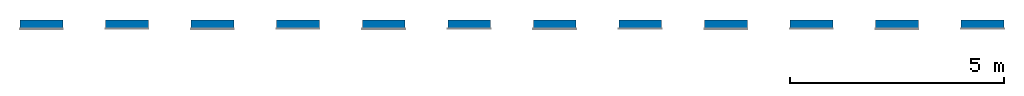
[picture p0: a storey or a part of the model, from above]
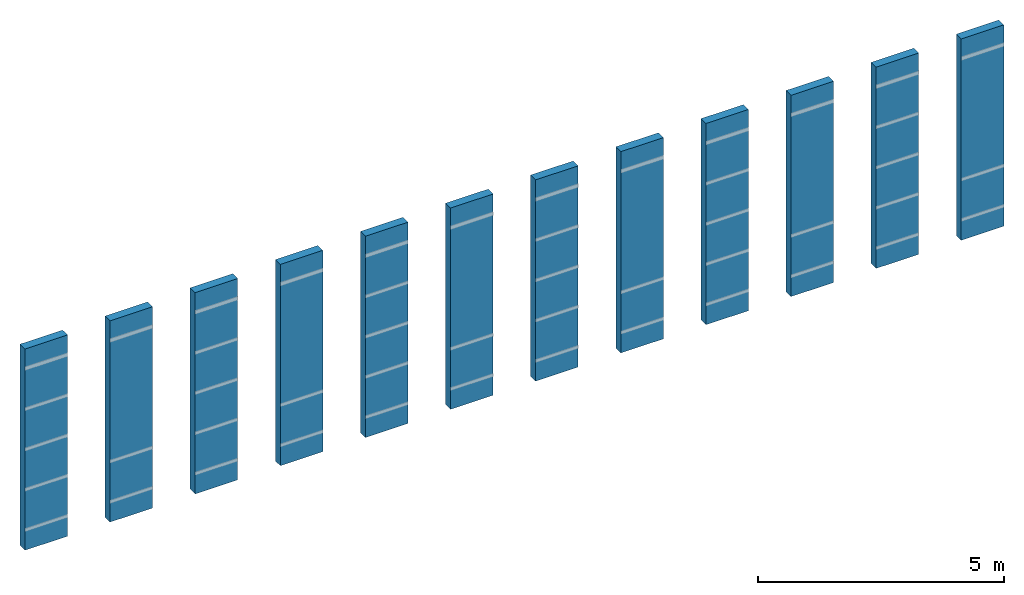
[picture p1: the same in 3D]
Properties of the parts of a building model (IFC2X3), part 1 of 3

# File
Description: ViewDefinition [CoordinationView_V2.0]
Time: 2025-06-20T15:58:29
Written by: The EXPRESS Data Manager Version 5.02.0100.07 : 28 Aug 2013
Made in: 21.1.90.15 - Exporter 21.1.90.15 - Alternate UI 21.1.90.15
Comment: STEP Physical File produced by: The EXPRESS Data Manager Version 5.02.0100.07 : 28 Aug 2013 * Module: EDMstepFileFactory/EDMstandAlone * Creation date: Fri Jun 20 15:58:29 2025 * Host: STB002 * Database: C:\Users\LARISS~1\AppData\Local\Temp\234e31d9-e186-458c-9206-d387dea7a233\60039892-82e4-4471-811b-854914402df2\ifc * Database version: 5507 * Database creation date: Fri Jun 20 15:58:27 2025 * Schema: IFC2X3 * Model: DataRepository.ifc * Model creation date: Fri Jun 20 15:58:28 2025 * Header model: DataRepository.ifc_HeaderModel * Header model creation date: Fri Jun 20 15:58:28 2025 * EDMuser: sdai-user * EDMgroup: sdai-group * License ID and type: 5605 : Permanent license. Expiry date: * EDMstepFileFactory options: 020000

# IfcSite, Default
RefLatitude: 42, 24, 53, 508911; RefLongitude: -71, -15, -29, -58837; RefElevation: 0 mm
Pset_ProductRequirements - Category: Project Information

# IfcBuilding
Pset_BuildingCommon - NumberOfStoreys: 1
Pset_ProductRequirements - Category: Project Information

# IfcBuildingStorey: Level:Level 1, Level 1
LongName: Level 1; Elevation: 0 mm
Pset_AirSideSystemInformation - Name: Level 1
Pset_ProductRequirements - Name: Level 1; Category: Levels

# IfcBuildingElementProxy: Wall Sweep:REVIGRÉS-URBAN-RB-8X120-RECT-ANTRACITE, Wall Sweep:REVIGRÉS-URBAN-RB-8X120-RECT-ANTRACITE:182745
In: Level 1
Type - Pset_ManufacturerTypeInformation - Manufacturer: REVIGRÉS
Type - Pset_ProductRequirements - Category: Wall Sweeps
Type - IFC.REVIGRÉS-Dados do fabricante-Wall Sweeps - FabricanteURL: https://www.revigres.pt/; ReferenciaModelo: Urban; Acabamento: RECT; IdentificadorDoOperadorEconomico: 501840856; UrlFabricanteArtigo: https://www.revigres.pt/colecoes/urban; PaisOrigem: Portugal
Type - IFC.REVIGRÉS-Dados de desempenho-Wall Sweeps - Rectilinearidade: ± 0.2% máx.± 0.8 mm; Ortogonalidade: ± 0.2% máx.± 1.5 mm; PlanaridadeDaSuperficie: ± 0.3% máx. ± 1.8 mm; AbsorcaoDeAgua: < 0.05%; ModuloDeRuptura: > 45 N/mm²; ResistenciaAFlexao: > 1500 N; ResistenciaAAbrasaoProfunda: < 120 mm³; DilatacaoTermicaLinear: ≤ 8,0x10-6 °C-1; ResistenciaAoChoqueTermico: Resiste; DurabilidadeResistenciaAoGeloDegelo: Resiste; ResistenciaAoEscorregamentoDIN51130: R9; ResistenciaAoEscorregamentoDIN51097: A; ResistenciaAoEscorregamentoENV51097: A; ResistenciaAoDeslizamentoENV12633: Class 1; ResistenciaAoEscorregamentoANSIA1371: ≥0,42; ResistenciaAoEscorregamentoENV12633: Class 1; ResistenciaAsManchas: Class 5; ResistenciaABaixasConcentracoesDeAcidosEAlcalis: Classe LA; ResistenciaAAltasConcentracoesDeAcidosEAlcalis: Classe HA; LibertacaoDeCadmio: 0; LibertacaoDeChumbo: 0
Type - IFC.REVIGRÉS-Dados de especificação-Wall Sweeps - VariacaoTonalidade: 2; NivelDeTrafego: 0; EPavimento: Não; ERevestimento: Sim; EExterno: Sim
Type - IFC.REVIGRÉS-Dados geométricos-Wall Sweeps - AlturaNominal: 9.8 mm; ComprimentoNominal: 8 mm; LarguraNominal: 1186 mm
Type - IFC.REVIGRÉS-Dados de sustentabilidade-Wall Sweeps - PotencialPrivacaoDeAguaConsumoDeAguaPonderado: 4.5; EnergiaTermicaExportada: 0; ItemENovo: Sim; ItemEParcialmenteReciclado: 0.29; ItemEReciclado: Sim; VidaÚtilEsperada: 50; SubstanciasPerigosas: Não; PotencialDeEsgotamentoAbioticoDosRecursosFosseis: 203; PotencialDeEsgotamentoAbioticoDosRecursosNaoFosseisMineraisEMetais: 0.000701; PotencialDeAquecimentoGlobalBiogenico: -0.48; CombustiveisFosseisComPotencialDeAquecimentoGlobal: 13.9; PotencialDeAquecimentoGlobalUsoDoSoloEMudancaDeUsoDoSolo: 0.0246; PotencialDeEutrofizacaoFraccaoDeNutrientesQueAtingemOCompartimentoFinalDeAguaDoce: 0.000189; PotencialDeEutrofizacaoFraccaoDeNutrientesQueAtingemOCompartimentoFinalMarinho: 0.0122; EnergiaRecuperada: 0.00739; ConsumoDeAguaDoce: 0.113; UtilizacaoLiquidaDeAguaDoce: 0.113; ResiduosPerigososEliminados: 0.00221; ResiduosNaoPerigososEliminados: 1.83; MassaTotalDeResiduosRadioactivosEliminados: 0.000394; EnergiaElectricaExportada: 1.55; MateriaisParaRecuperacaoDeEnergia: 0.00739; MateriaisParaReciclagem: 0.0253; UnidadeEPD: 1 m²
Type - IFC.REVIGRÉS-Dados gerais-Wall Sweeps - Nome: REVIGRÉS-URBAN-RB-8X120-RECT-URBAN ANTRACITE; TipoProduto: Prensado a seco: grupo BIa UGL | Grés porcelânico técnico; NumeroDeRegistoDAP: EPD-REV-20240006-CCC1-EN; ReferenciaDAP: -; UrlDOP: -
Pset_ProvisionForVoid - Shape: Undefined; Width: 1000 mm; Depth: 1000 mm
IFC.REVIGRÉS-Dados do fabricante-Wall Sweeps - Type: Wall Sweep: REVIGRÉS-URBAN-RB-8X120-RECT-ANTRACITE
IFC.REVIGRÉS-Dados de desempenho-Wall Sweeps - Type: Wall Sweep: REVIGRÉS-URBAN-RB-8X120-RECT-ANTRACITE
IFC.REVIGRÉS-Dados de especificação-Wall Sweeps - Type: Wall Sweep: REVIGRÉS-URBAN-RB-8X120-RECT-ANTRACITE
IFC.REVIGRÉS-Dados geométricos-Wall Sweeps - Type: Wall Sweep: REVIGRÉS-URBAN-RB-8X120-RECT-ANTRACITE
IFC.REVIGRÉS-Dados de sustentabilidade-Wall Sweeps - Type: Wall Sweep: REVIGRÉS-URBAN-RB-8X120-RECT-ANTRACITE

# IfcBuildingElementProxy: Wall Sweep:REVIGRÉS-URBAN-RB-8X120-RECT-BONE, Wall Sweep:REVIGRÉS-URBAN-RB-8X120-RECT-BONE:182755
In: Level 1
Type - Pset_ManufacturerTypeInformation - Manufacturer: REVIGRÉS
Type - Pset_ProductRequirements - Category: Wall Sweeps
Type - IFC.REVIGRÉS-Dados do fabricante-Wall Sweeps - FabricanteURL: https://www.revigres.pt/; ReferenciaModelo: Urban; Acabamento: RECT; IdentificadorDoOperadorEconomico: 501840856; UrlFabricanteArtigo: https://www.revigres.pt/colecoes/urban; PaisOrigem: Portugal
Type - IFC.REVIGRÉS-Dados de desempenho-Wall Sweeps - Rectilinearidade: ± 0.2% máx.± 0.8 mm; Ortogonalidade: ± 0.2% máx.± 1.5 mm; PlanaridadeDaSuperficie: ± 0.3% máx. ± 1.8 mm; AbsorcaoDeAgua: < 0.05%; ModuloDeRuptura: > 45 N/mm²; ResistenciaAFlexao: > 1500 N; ResistenciaAAbrasaoProfunda: < 120 mm³; DilatacaoTermicaLinear: ≤ 8,0x10-6 °C-1; ResistenciaAoChoqueTermico: Resiste; DurabilidadeResistenciaAoGeloDegelo: Resiste; ResistenciaAoEscorregamentoDIN51130: R9; ResistenciaAoEscorregamentoDIN51097: A; ResistenciaAoEscorregamentoENV51097: A; ResistenciaAoDeslizamentoENV12633: Class 1; ResistenciaAoEscorregamentoANSIA1371: ≥0,42; ResistenciaAoEscorregamentoENV12633: Class 1; ResistenciaAsManchas: Class 5; ResistenciaABaixasConcentracoesDeAcidosEAlcalis: Classe LA; ResistenciaAAltasConcentracoesDeAcidosEAlcalis: Classe HA; LibertacaoDeCadmio: 0; LibertacaoDeChumbo: 0
Type - IFC.REVIGRÉS-Dados de especificação-Wall Sweeps - VariacaoTonalidade: 2; NivelDeTrafego: 0; EPavimento: Não; ERevestimento: Sim; EExterno: Sim
Type - IFC.REVIGRÉS-Dados geométricos-Wall Sweeps - AlturaNominal: 9.8 mm; ComprimentoNominal: 8 mm; LarguraNominal: 1186 mm
Type - IFC.REVIGRÉS-Dados de sustentabilidade-Wall Sweeps - PotencialPrivacaoDeAguaConsumoDeAguaPonderado: 4.5; EnergiaTermicaExportada: 0; ItemENovo: Sim; ItemEParcialmenteReciclado: 0.03; ItemEReciclado: Sim; VidaÚtilEsperada: 50; SubstanciasPerigosas: Não; PotencialDeEsgotamentoAbioticoDosRecursosFosseis: 203; PotencialDeEsgotamentoAbioticoDosRecursosNaoFosseisMineraisEMetais: 0.000701; PotencialDeAquecimentoGlobalBiogenico: -0.48; CombustiveisFosseisComPotencialDeAquecimentoGlobal: 13.9; PotencialDeAquecimentoGlobalUsoDoSoloEMudancaDeUsoDoSolo: 0.0246; PotencialDeEutrofizacaoFraccaoDeNutrientesQueAtingemOCompartimentoFinalDeAguaDoce: 0.000189; PotencialDeEutrofizacaoFraccaoDeNutrientesQueAtingemOCompartimentoFinalMarinho: 0.0122; EnergiaRecuperada: 0.00739; ConsumoDeAguaDoce: 0.113; UtilizacaoLiquidaDeAguaDoce: 0.113; ResiduosPerigososEliminados: 0.00221; ResiduosNaoPerigososEliminados: 1.83; MassaTotalDeResiduosRadioactivosEliminados: 0.000394; EnergiaElectricaExportada: 1.55; MateriaisParaRecuperacaoDeEnergia: 0.00739; MateriaisParaReciclagem: 0.0253; UnidadeEPD: 1 m²
Type - IFC.REVIGRÉS-Dados gerais-Wall Sweeps - Nome: REVIGRÉS-URBAN-RB-8X120-RECT-URBAN BONE; TipoProduto: Prensado a seco: grupo BIa UGL | Grés porcelânico técnico; NumeroDeRegistoDAP: EPD-REV-20240006-CCC1-EN; ReferenciaDAP: -; UrlDOP: -
Pset_ProvisionForVoid - Shape: Undefined; Width: 1000 mm; Depth: 1000 mm
IFC.REVIGRÉS-Dados do fabricante-Wall Sweeps - Type: Wall Sweep: REVIGRÉS-URBAN-RB-8X120-RECT-BONE
IFC.REVIGRÉS-Dados de desempenho-Wall Sweeps - Type: Wall Sweep: REVIGRÉS-URBAN-RB-8X120-RECT-BONE
IFC.REVIGRÉS-Dados de especificação-Wall Sweeps - Type: Wall Sweep: REVIGRÉS-URBAN-RB-8X120-RECT-BONE
IFC.REVIGRÉS-Dados geométricos-Wall Sweeps - Type: Wall Sweep: REVIGRÉS-URBAN-RB-8X120-RECT-BONE
IFC.REVIGRÉS-Dados de sustentabilidade-Wall Sweeps - Type: Wall Sweep: REVIGRÉS-URBAN-RB-8X120-RECT-BONE

# IfcBuildingElementProxy: Wall Sweep:REVIGRÉS-URBAN-RB-8X120-RECT-CRAFT, Wall Sweep:REVIGRÉS-URBAN-RB-8X120-RECT-CRAFT:182765
In: Level 1
Type - Pset_ManufacturerTypeInformation - Manufacturer: REVIGRÉS
Type - Pset_ProductRequirements - Category: Wall Sweeps
Type - IFC.REVIGRÉS-Dados do fabricante-Wall Sweeps - FabricanteURL: https://www.revigres.pt/; ReferenciaModelo: Urban; Acabamento: RECT; IdentificadorDoOperadorEconomico: 501840856; UrlFabricanteArtigo: https://www.revigres.pt/colecoes/urban; PaisOrigem: Portugal
Type - IFC.REVIGRÉS-Dados de desempenho-Wall Sweeps - Rectilinearidade: ± 0.2% máx.± 0.8 mm; Ortogonalidade: ± 0.2% máx.± 1.5 mm; PlanaridadeDaSuperficie: ± 0.3% máx. ± 1.8 mm; AbsorcaoDeAgua: < 0.05%; ModuloDeRuptura: > 45 N/mm²; ResistenciaAFlexao: > 1500 N; ResistenciaAAbrasaoProfunda: < 120 mm³; DilatacaoTermicaLinear: ≤ 8,0x10-6 °C-1; ResistenciaAoChoqueTermico: Resiste; DurabilidadeResistenciaAoGeloDegelo: Resiste; ResistenciaAoEscorregamentoDIN51130: R9; ResistenciaAoEscorregamentoDIN51097: A; ResistenciaAoEscorregamentoENV51097: A; ResistenciaAoDeslizamentoENV12633: Class 1; ResistenciaAoEscorregamentoANSIA1371: ≥0,42; ResistenciaAoEscorregamentoENV12633: Class 1; ResistenciaAsManchas: Class 5; ResistenciaABaixasConcentracoesDeAcidosEAlcalis: Classe LA; ResistenciaAAltasConcentracoesDeAcidosEAlcalis: Classe HA; LibertacaoDeCadmio: 0; LibertacaoDeChumbo: 0
Type - IFC.REVIGRÉS-Dados de especificação-Wall Sweeps - VariacaoTonalidade: 2; NivelDeTrafego: 0; EPavimento: Não; ERevestimento: Sim; EExterno: Sim
Type - IFC.REVIGRÉS-Dados geométricos-Wall Sweeps - AlturaNominal: 9.8 mm; ComprimentoNominal: 8 mm; LarguraNominal: 1186 mm
Type - IFC.REVIGRÉS-Dados de sustentabilidade-Wall Sweeps - PotencialPrivacaoDeAguaConsumoDeAguaPonderado: 4.5; EnergiaTermicaExportada: 0; ItemENovo: Sim; ItemEParcialmenteReciclado: 0.19; ItemEReciclado: Sim; VidaÚtilEsperada: 50; SubstanciasPerigosas: Não; PotencialDeEsgotamentoAbioticoDosRecursosFosseis: 203; PotencialDeEsgotamentoAbioticoDosRecursosNaoFosseisMineraisEMetais: 0.000701; PotencialDeAquecimentoGlobalBiogenico: -0.48; CombustiveisFosseisComPotencialDeAquecimentoGlobal: 13.9; PotencialDeAquecimentoGlobalUsoDoSoloEMudancaDeUsoDoSolo: 0.0246; PotencialDeEutrofizacaoFraccaoDeNutrientesQueAtingemOCompartimentoFinalDeAguaDoce: 0.000189; PotencialDeEutrofizacaoFraccaoDeNutrientesQueAtingemOCompartimentoFinalMarinho: 0.0122; EnergiaRecuperada: 0.00739; ConsumoDeAguaDoce: 0.113; UtilizacaoLiquidaDeAguaDoce: 0.113; ResiduosPerigososEliminados: 0.00221; ResiduosNaoPerigososEliminados: 1.83; MassaTotalDeResiduosRadioactivosEliminados: 0.000394; EnergiaElectricaExportada: 1.55; MateriaisParaRecuperacaoDeEnergia: 0.00739; MateriaisParaReciclagem: 0.0253; UnidadeEPD: 1 m²
Type - IFC.REVIGRÉS-Dados gerais-Wall Sweeps - Nome: REVIGRÉS-URBAN-RB-8X120-RECT-URBAN CRAFT; TipoProduto: Prensado a seco: grupo BIa UGL | Grés porcelânico técnico; NumeroDeRegistoDAP: EPD-REV-20240006-CCC1-EN; ReferenciaDAP: -; UrlDOP: -
Pset_ProvisionForVoid - Shape: Undefined; Width: 1000 mm; Depth: 1000 mm
IFC.REVIGRÉS-Dados do fabricante-Wall Sweeps - Type: Wall Sweep: REVIGRÉS-URBAN-RB-8X120-RECT-CRAFT
IFC.REVIGRÉS-Dados de desempenho-Wall Sweeps - Type: Wall Sweep: REVIGRÉS-URBAN-RB-8X120-RECT-CRAFT
IFC.REVIGRÉS-Dados de especificação-Wall Sweeps - Type: Wall Sweep: REVIGRÉS-URBAN-RB-8X120-RECT-CRAFT
IFC.REVIGRÉS-Dados geométricos-Wall Sweeps - Type: Wall Sweep: REVIGRÉS-URBAN-RB-8X120-RECT-CRAFT
IFC.REVIGRÉS-Dados de sustentabilidade-Wall Sweeps - Type: Wall Sweep: REVIGRÉS-URBAN-RB-8X120-RECT-CRAFT

# IfcBuildingElementProxy: Wall Sweep:REVIGRÉS-URBAN-RB-8X120-RECT-FOG, Wall Sweep:REVIGRÉS-URBAN-RB-8X120-RECT-FOG:182775
In: Level 1
Type - Pset_ManufacturerTypeInformation - Manufacturer: REVIGRÉS
Type - Pset_ProductRequirements - Category: Wall Sweeps
Type - IFC.REVIGRÉS-Dados do fabricante-Wall Sweeps - FabricanteURL: https://www.revigres.pt/; ReferenciaModelo: Urban; Acabamento: RECT; IdentificadorDoOperadorEconomico: 501840856; UrlFabricanteArtigo: https://www.revigres.pt/colecoes/urban; PaisOrigem: Portugal
Type - IFC.REVIGRÉS-Dados de desempenho-Wall Sweeps - Rectilinearidade: ± 0.2% máx.± 0.8 mm; Ortogonalidade: ± 0.2% máx.± 1.5 mm; PlanaridadeDaSuperficie: ± 0.3% máx. ± 1.8 mm; AbsorcaoDeAgua: < 0.05%; ModuloDeRuptura: > 45 N/mm²; ResistenciaAFlexao: > 1500 N; ResistenciaAAbrasaoProfunda: < 120 mm³; DilatacaoTermicaLinear: ≤ 8,0x10-6 °C-1; ResistenciaAoChoqueTermico: Resiste; DurabilidadeResistenciaAoGeloDegelo: Resiste; ResistenciaAoEscorregamentoDIN51130: R9; ResistenciaAoEscorregamentoDIN51097: A; ResistenciaAoEscorregamentoENV51097: A; ResistenciaAoDeslizamentoENV12633: Class 1; ResistenciaAoEscorregamentoANSIA1371: ≥0,42; ResistenciaAoEscorregamentoENV12633: Class 1; ResistenciaAsManchas: Class 5; ResistenciaABaixasConcentracoesDeAcidosEAlcalis: Classe LA; ResistenciaAAltasConcentracoesDeAcidosEAlcalis: Classe HA; LibertacaoDeCadmio: 0; LibertacaoDeChumbo: 0
Type - IFC.REVIGRÉS-Dados de especificação-Wall Sweeps - VariacaoTonalidade: 2; NivelDeTrafego: 0; EPavimento: Não; ERevestimento: Sim; EExterno: Sim
Type - IFC.REVIGRÉS-Dados geométricos-Wall Sweeps - AlturaNominal: 9.8 mm; ComprimentoNominal: 8 mm; LarguraNominal: 1186 mm
Type - IFC.REVIGRÉS-Dados de sustentabilidade-Wall Sweeps - PotencialPrivacaoDeAguaConsumoDeAguaPonderado: 4.5; EnergiaTermicaExportada: 0; ItemENovo: Sim; ItemEParcialmenteReciclado: 0.23; ItemEReciclado: Sim; VidaÚtilEsperada: 50; SubstanciasPerigosas: Não; PotencialDeEsgotamentoAbioticoDosRecursosFosseis: 203; PotencialDeEsgotamentoAbioticoDosRecursosNaoFosseisMineraisEMetais: 0.000701; PotencialDeAquecimentoGlobalBiogenico: -0.48; CombustiveisFosseisComPotencialDeAquecimentoGlobal: 13.9; PotencialDeAquecimentoGlobalUsoDoSoloEMudancaDeUsoDoSolo: 0.0246; PotencialDeEutrofizacaoFraccaoDeNutrientesQueAtingemOCompartimentoFinalDeAguaDoce: 0.000189; PotencialDeEutrofizacaoFraccaoDeNutrientesQueAtingemOCompartimentoFinalMarinho: 0.0122; EnergiaRecuperada: 0.00739; ConsumoDeAguaDoce: 0.113; UtilizacaoLiquidaDeAguaDoce: 0.113; ResiduosPerigososEliminados: 0.00221; ResiduosNaoPerigososEliminados: 1.83; MassaTotalDeResiduosRadioactivosEliminados: 0.000394; EnergiaElectricaExportada: 1.55; MateriaisParaRecuperacaoDeEnergia: 0.00739; MateriaisParaReciclagem: 0.0253; UnidadeEPD: 1 m²
Type - IFC.REVIGRÉS-Dados gerais-Wall Sweeps - Nome: REVIGRÉS-URBAN-RB-8X120-RECT-URBAN FOG; TipoProduto: Prensado a seco: grupo BIa UGL | Grés porcelânico técnico; NumeroDeRegistoDAP: EPD-REV-20240006-CCC1-EN; ReferenciaDAP: -; UrlDOP: -
Pset_ProvisionForVoid - Shape: Undefined; Width: 1000 mm; Depth: 1000 mm
IFC.REVIGRÉS-Dados do fabricante-Wall Sweeps - Type: Wall Sweep: REVIGRÉS-URBAN-RB-8X120-RECT-FOG
IFC.REVIGRÉS-Dados de desempenho-Wall Sweeps - Type: Wall Sweep: REVIGRÉS-URBAN-RB-8X120-RECT-FOG
IFC.REVIGRÉS-Dados de especificação-Wall Sweeps - Type: Wall Sweep: REVIGRÉS-URBAN-RB-8X120-RECT-FOG
IFC.REVIGRÉS-Dados geométricos-Wall Sweeps - Type: Wall Sweep: REVIGRÉS-URBAN-RB-8X120-RECT-FOG
IFC.REVIGRÉS-Dados de sustentabilidade-Wall Sweeps - Type: Wall Sweep: REVIGRÉS-URBAN-RB-8X120-RECT-FOG

# IfcBuildingElementProxy: Wall Sweep:REVIGRÉS-URBAN-RB-8X120-RECT-GRIS, Wall Sweep:REVIGRÉS-URBAN-RB-8X120-RECT-GRIS:182785
In: Level 1
Type - Pset_ManufacturerTypeInformation - Manufacturer: REVIGRÉS
Type - Pset_ProductRequirements - Category: Wall Sweeps
Type - IFC.REVIGRÉS-Dados do fabricante-Wall Sweeps - FabricanteURL: https://www.revigres.pt/; ReferenciaModelo: Urban; Acabamento: RECT; IdentificadorDoOperadorEconomico: 501840856; UrlFabricanteArtigo: https://www.revigres.pt/colecoes/urban; PaisOrigem: Portugal
Type - IFC.REVIGRÉS-Dados de desempenho-Wall Sweeps - Rectilinearidade: ± 0.2% máx.± 0.8 mm; Ortogonalidade: ± 0.2% máx.± 1.5 mm; PlanaridadeDaSuperficie: ± 0.3% máx. ± 1.8 mm; AbsorcaoDeAgua: < 0.05%; ModuloDeRuptura: > 45 N/mm²; ResistenciaAFlexao: > 1500 N; ResistenciaAAbrasaoProfunda: < 120 mm³; DilatacaoTermicaLinear: ≤ 8,0x10-6 °C-1; ResistenciaAoChoqueTermico: Resiste; DurabilidadeResistenciaAoGeloDegelo: Resiste; ResistenciaAoEscorregamentoDIN51130: R9; ResistenciaAoEscorregamentoDIN51097: A; ResistenciaAoEscorregamentoENV51097: A; ResistenciaAoDeslizamentoENV12633: Class 1; ResistenciaAoEscorregamentoANSIA1371: ≥0,42; ResistenciaAoEscorregamentoENV12633: Class 1; ResistenciaAsManchas: Class 5; ResistenciaABaixasConcentracoesDeAcidosEAlcalis: Classe LA; ResistenciaAAltasConcentracoesDeAcidosEAlcalis: Classe HA; LibertacaoDeCadmio: 0; LibertacaoDeChumbo: 0
Type - IFC.REVIGRÉS-Dados de especificação-Wall Sweeps - VariacaoTonalidade: 2; NivelDeTrafego: 0; EPavimento: Não; ERevestimento: Sim; EExterno: Sim
Type - IFC.REVIGRÉS-Dados geométricos-Wall Sweeps - AlturaNominal: 9.8 mm; ComprimentoNominal: 8 mm; LarguraNominal: 1186 mm
Type - IFC.REVIGRÉS-Dados de sustentabilidade-Wall Sweeps - PotencialPrivacaoDeAguaConsumoDeAguaPonderado: 4.5; EnergiaTermicaExportada: 0; ItemENovo: Sim; ItemEParcialmenteReciclado: 0.23; ItemEReciclado: Sim; VidaÚtilEsperada: 50; SubstanciasPerigosas: Não; PotencialDeEsgotamentoAbioticoDosRecursosFosseis: 203; PotencialDeEsgotamentoAbioticoDosRecursosNaoFosseisMineraisEMetais: 0.000701; PotencialDeAquecimentoGlobalBiogenico: -0.48; CombustiveisFosseisComPotencialDeAquecimentoGlobal: 13.9; PotencialDeAquecimentoGlobalUsoDoSoloEMudancaDeUsoDoSolo: 0.0246; PotencialDeEutrofizacaoFraccaoDeNutrientesQueAtingemOCompartimentoFinalDeAguaDoce: 0.000189; PotencialDeEutrofizacaoFraccaoDeNutrientesQueAtingemOCompartimentoFinalMarinho: 0.0122; EnergiaRecuperada: 0.00739; ConsumoDeAguaDoce: 0.113; UtilizacaoLiquidaDeAguaDoce: 0.113; ResiduosPerigososEliminados: 0.00221; ResiduosNaoPerigososEliminados: 1.83; MassaTotalDeResiduosRadioactivosEliminados: 0.000394; EnergiaElectricaExportada: 1.55; MateriaisParaRecuperacaoDeEnergia: 0.00739; MateriaisParaReciclagem: 0.0253; UnidadeEPD: 1 m²
Type - IFC.REVIGRÉS-Dados gerais-Wall Sweeps - Nome: REVIGRÉS-URBAN-RB-8X120-RECT-URBAN GRIS; TipoProduto: Prensado a seco: grupo BIa UGL | Grés porcelânico técnico; NumeroDeRegistoDAP: EPD-REV-20240006-CCC1-EN; ReferenciaDAP: -; UrlDOP: -
Pset_ProvisionForVoid - Shape: Undefined; Width: 1000 mm; Depth: 1000 mm
IFC.REVIGRÉS-Dados do fabricante-Wall Sweeps - Type: Wall Sweep: REVIGRÉS-URBAN-RB-8X120-RECT-GRIS
IFC.REVIGRÉS-Dados de desempenho-Wall Sweeps - Type: Wall Sweep: REVIGRÉS-URBAN-RB-8X120-RECT-GRIS
IFC.REVIGRÉS-Dados de especificação-Wall Sweeps - Type: Wall Sweep: REVIGRÉS-URBAN-RB-8X120-RECT-GRIS
IFC.REVIGRÉS-Dados geométricos-Wall Sweeps - Type: Wall Sweep: REVIGRÉS-URBAN-RB-8X120-RECT-GRIS
IFC.REVIGRÉS-Dados de sustentabilidade-Wall Sweeps - Type: Wall Sweep: REVIGRÉS-URBAN-RB-8X120-RECT-GRIS

# IfcBuildingElementProxy: Wall Sweep:REVIGRÉS-URBAN-RB-8X120-RECT-OFFWHITE, Wall Sweep:REVIGRÉS-URBAN-RB-8X120-RECT-OFFWHITE:182795
In: Level 1
Type - Pset_ManufacturerTypeInformation - Manufacturer: REVIGRÉS
Type - Pset_ProductRequirements - Category: Wall Sweeps
Type - IFC.REVIGRÉS-Dados do fabricante-Wall Sweeps - FabricanteURL: https://www.revigres.pt/; ReferenciaModelo: Urban; Acabamento: RECT; IdentificadorDoOperadorEconomico: 501840856; UrlFabricanteArtigo: https://www.revigres.pt/colecoes/urban; PaisOrigem: Portugal
Type - IFC.REVIGRÉS-Dados de desempenho-Wall Sweeps - Rectilinearidade: ± 0.2% máx.± 0.8 mm; Ortogonalidade: ± 0.2% máx.± 1.5 mm; PlanaridadeDaSuperficie: ± 0.3% máx. ± 1.8 mm; AbsorcaoDeAgua: < 0.05%; ModuloDeRuptura: > 45 N/mm²; ResistenciaAFlexao: > 1500 N; ResistenciaAAbrasaoProfunda: < 120 mm³; DilatacaoTermicaLinear: ≤ 8,0x10-6 °C-1; ResistenciaAoChoqueTermico: Resiste; DurabilidadeResistenciaAoGeloDegelo: Resiste; ResistenciaAoEscorregamentoDIN51130: R9; ResistenciaAoEscorregamentoDIN51097: A; ResistenciaAoEscorregamentoENV51097: A; ResistenciaAoDeslizamentoENV12633: Class 1; ResistenciaAoEscorregamentoANSIA1371: ≥0,42; ResistenciaAoEscorregamentoENV12633: Class 1; ResistenciaAsManchas: Class 5; ResistenciaABaixasConcentracoesDeAcidosEAlcalis: Classe LA; ResistenciaAAltasConcentracoesDeAcidosEAlcalis: Classe HA; LibertacaoDeCadmio: 0; LibertacaoDeChumbo: 0
Type - IFC.REVIGRÉS-Dados de especificação-Wall Sweeps - VariacaoTonalidade: 2; NivelDeTrafego: 0; EPavimento: Não; ERevestimento: Sim; EExterno: Sim
Type - IFC.REVIGRÉS-Dados geométricos-Wall Sweeps - AlturaNominal: 9.8 mm; ComprimentoNominal: 8 mm; LarguraNominal: 1186 mm
Type - IFC.REVIGRÉS-Dados de sustentabilidade-Wall Sweeps - PotencialPrivacaoDeAguaConsumoDeAguaPonderado: 4.5; EnergiaTermicaExportada: 0; ItemENovo: Sim; ItemEParcialmenteReciclado: 0.03; ItemEReciclado: Sim; VidaÚtilEsperada: 50; SubstanciasPerigosas: Não; PotencialDeEsgotamentoAbioticoDosRecursosFosseis: 203; PotencialDeEsgotamentoAbioticoDosRecursosNaoFosseisMineraisEMetais: 0.000701; PotencialDeAquecimentoGlobalBiogenico: -0.48; CombustiveisFosseisComPotencialDeAquecimentoGlobal: 13.9; PotencialDeAquecimentoGlobalUsoDoSoloEMudancaDeUsoDoSolo: 0.0246; PotencialDeEutrofizacaoFraccaoDeNutrientesQueAtingemOCompartimentoFinalDeAguaDoce: 0.000189; PotencialDeEutrofizacaoFraccaoDeNutrientesQueAtingemOCompartimentoFinalMarinho: 0.0122; EnergiaRecuperada: 0.00739; ConsumoDeAguaDoce: 0.113; UtilizacaoLiquidaDeAguaDoce: 0.113; ResiduosPerigososEliminados: 0.00221; ResiduosNaoPerigososEliminados: 1.83; MassaTotalDeResiduosRadioactivosEliminados: 0.000394; EnergiaElectricaExportada: 1.55; MateriaisParaRecuperacaoDeEnergia: 0.00739; MateriaisParaReciclagem: 0.0253; UnidadeEPD: 1 m²
Type - IFC.REVIGRÉS-Dados gerais-Wall Sweeps - Nome: REVIGRÉS-URBAN-RB-8X120-RECT-URBAN OFFWHITE; TipoProduto: Prensado a seco: grupo BIa UGL | Grés porcelânico técnico; NumeroDeRegistoDAP: EPD-REV-20240006-CCC1-EN; ReferenciaDAP: -; UrlDOP: -
Pset_ProvisionForVoid - Shape: Undefined; Width: 1000 mm; Depth: 1000 mm
IFC.REVIGRÉS-Dados do fabricante-Wall Sweeps - Type: Wall Sweep: REVIGRÉS-URBAN-RB-8X120-RECT-OFFWHITE
IFC.REVIGRÉS-Dados de desempenho-Wall Sweeps - Type: Wall Sweep: REVIGRÉS-URBAN-RB-8X120-RECT-OFFWHITE
IFC.REVIGRÉS-Dados de especificação-Wall Sweeps - Type: Wall Sweep: REVIGRÉS-URBAN-RB-8X120-RECT-OFFWHITE
IFC.REVIGRÉS-Dados geométricos-Wall Sweeps - Type: Wall Sweep: REVIGRÉS-URBAN-RB-8X120-RECT-OFFWHITE
IFC.REVIGRÉS-Dados de sustentabilidade-Wall Sweeps - Type: Wall Sweep: REVIGRÉS-URBAN-RB-8X120-RECT-OFFWHITE

# IfcBuildingElementProxy: Wall Sweep:REVIGRÉS-URBAN-RB-8X45-NAT-ANTRACITE, Wall Sweep:REVIGRÉS-URBAN-RB-8X45-NAT-ANTRACITE:182748
In: Level 1
Type - Pset_ManufacturerTypeInformation - Manufacturer: REVIGRÉS
Type - Pset_ProductRequirements - Category: Wall Sweeps
Type - IFC.REVIGRÉS-Dados do fabricante-Wall Sweeps - FabricanteURL: https://www.revigres.pt/; ReferenciaModelo: Urban; Acabamento: NAT; IdentificadorDoOperadorEconomico: 501840856; UrlFabricanteArtigo: https://www.revigres.pt/colecoes/urban; PaisOrigem: Portugal
Type - IFC.REVIGRÉS-Dados de desempenho-Wall Sweeps - Rectilinearidade: ± 0.3% máx. ± 1.5 mm; Ortogonalidade: ± 0.3% máx. ± 1.8 mm; PlanaridadeDaSuperficie: ± 0.3% máx. ± 1.8 mm; AbsorcaoDeAgua: < 0.05%; ModuloDeRuptura: > 45 N/mm²; ResistenciaAFlexao: > 2000 N; ResistenciaAAbrasaoProfunda: < 120 mm³; DilatacaoTermicaLinear: ≤ 8,0x10-6 °C-1; ResistenciaAoChoqueTermico: Resiste; DurabilidadeResistenciaAoGeloDegelo: Resiste; ResistenciaAoEscorregamentoDIN51130: R9; ResistenciaAoEscorregamentoDIN51097: A; ResistenciaAoEscorregamentoENV51097: A; ResistenciaAoDeslizamentoENV12633: Class 1; ResistenciaAoEscorregamentoANSIA1371: ≥0,42; ResistenciaAoEscorregamentoENV12633: Class 1; ResistenciaAsManchas: Class 5; ResistenciaABaixasConcentracoesDeAcidosEAlcalis: Classe LA; ResistenciaAAltasConcentracoesDeAcidosEAlcalis: Classe HA; LibertacaoDeCadmio: 0; LibertacaoDeChumbo: 0
Type - IFC.REVIGRÉS-Dados de especificação-Wall Sweeps - VariacaoTonalidade: 2; NivelDeTrafego: 0; EPavimento: Não; ERevestimento: Sim; EExterno: Sim
Type - IFC.REVIGRÉS-Dados geométricos-Wall Sweeps - AlturaNominal: 8.5 mm; ComprimentoNominal: 8 mm; LarguraNominal: 45 mm
Type - IFC.REVIGRÉS-Dados de sustentabilidade-Wall Sweeps - PotencialPrivacaoDeAguaConsumoDeAguaPonderado: 4.5; EnergiaTermicaExportada: 0; ItemENovo: Sim; ItemEParcialmenteReciclado: 0.29; ItemEReciclado: Sim; VidaÚtilEsperada: 50; SubstanciasPerigosas: Não; PotencialDeEsgotamentoAbioticoDosRecursosFosseis: 203; PotencialDeEsgotamentoAbioticoDosRecursosNaoFosseisMineraisEMetais: 0.000701; PotencialDeAquecimentoGlobalBiogenico: -0.48; CombustiveisFosseisComPotencialDeAquecimentoGlobal: 13.9; PotencialDeAquecimentoGlobalUsoDoSoloEMudancaDeUsoDoSolo: 0.0246; PotencialDeEutrofizacaoFraccaoDeNutrientesQueAtingemOCompartimentoFinalDeAguaDoce: 0.000189; PotencialDeEutrofizacaoFraccaoDeNutrientesQueAtingemOCompartimentoFinalMarinho: 0.0122; EnergiaRecuperada: 0.00739; ConsumoDeAguaDoce: 0.113; UtilizacaoLiquidaDeAguaDoce: 0.113; ResiduosPerigososEliminados: 0.00221; ResiduosNaoPerigososEliminados: 1.83; MassaTotalDeResiduosRadioactivosEliminados: 0.000394; EnergiaElectricaExportada: 1.55; MateriaisParaRecuperacaoDeEnergia: 0.00739; MateriaisParaReciclagem: 0.0253; UnidadeEPD: 1 m²
Type - IFC.REVIGRÉS-Dados gerais-Wall Sweeps - Nome: REVIGRÉS-URBAN-RB-8X45-NAT-URBAN ANTRACITE; TipoProduto: Prensado a seco: grupo BIa UGL | Grés porcelânico técnico; NumeroDeRegistoDAP: EPD-REV-20240006-CCC1-EN; ReferenciaDAP: -; UrlDOP: -
Pset_ProvisionForVoid - Shape: Undefined; Width: 1000 mm; Depth: 1000 mm
IFC.REVIGRÉS-Dados do fabricante-Wall Sweeps - Type: Wall Sweep: REVIGRÉS-URBAN-RB-8X45-NAT-ANTRACITE
IFC.REVIGRÉS-Dados de desempenho-Wall Sweeps - Type: Wall Sweep: REVIGRÉS-URBAN-RB-8X45-NAT-ANTRACITE
IFC.REVIGRÉS-Dados de especificação-Wall Sweeps - Type: Wall Sweep: REVIGRÉS-URBAN-RB-8X45-NAT-ANTRACITE
IFC.REVIGRÉS-Dados geométricos-Wall Sweeps - Type: Wall Sweep: REVIGRÉS-URBAN-RB-8X45-NAT-ANTRACITE
IFC.REVIGRÉS-Dados de sustentabilidade-Wall Sweeps - Type: Wall Sweep: REVIGRÉS-URBAN-RB-8X45-NAT-ANTRACITE

# IfcBuildingElementProxy: Wall Sweep:REVIGRÉS-URBAN-RB-8X45-NAT-BONE, Wall Sweep:REVIGRÉS-URBAN-RB-8X45-NAT-BONE:182758
In: Level 1
Type - Pset_ManufacturerTypeInformation - Manufacturer: REVIGRÉS
Type - Pset_ProductRequirements - Category: Wall Sweeps
Type - IFC.REVIGRÉS-Dados do fabricante-Wall Sweeps - FabricanteURL: https://www.revigres.pt/; ReferenciaModelo: Urban; Acabamento: NAT; IdentificadorDoOperadorEconomico: 501840856; UrlFabricanteArtigo: https://www.revigres.pt/colecoes/urban; PaisOrigem: Portugal
Type - IFC.REVIGRÉS-Dados de desempenho-Wall Sweeps - Rectilinearidade: ± 0.3% máx. ± 1.5 mm; Ortogonalidade: ± 0.3% máx. ± 1.8 mm; PlanaridadeDaSuperficie: ± 0.3% máx. ± 1.8 mm; AbsorcaoDeAgua: < 0.05%; ModuloDeRuptura: > 45 N/mm²; ResistenciaAFlexao: > 2000 N; ResistenciaAAbrasaoProfunda: < 120 mm³; DilatacaoTermicaLinear: ≤ 8,0x10-6 °C-1; ResistenciaAoChoqueTermico: Resiste; DurabilidadeResistenciaAoGeloDegelo: Resiste; ResistenciaAoEscorregamentoDIN51130: R9; ResistenciaAoEscorregamentoDIN51097: A; ResistenciaAoEscorregamentoENV51097: A; ResistenciaAoDeslizamentoENV12633: Class 1; ResistenciaAoEscorregamentoANSIA1371: ≥0,42; ResistenciaAoEscorregamentoENV12633: Class 1; ResistenciaAsManchas: Class 5; ResistenciaABaixasConcentracoesDeAcidosEAlcalis: Classe LA; ResistenciaAAltasConcentracoesDeAcidosEAlcalis: Classe HA; LibertacaoDeCadmio: 0; LibertacaoDeChumbo: 0
Type - IFC.REVIGRÉS-Dados de especificação-Wall Sweeps - VariacaoTonalidade: 2; NivelDeTrafego: 0; EPavimento: Não; ERevestimento: Sim; EExterno: Sim
Type - IFC.REVIGRÉS-Dados geométricos-Wall Sweeps - AlturaNominal: 8.5 mm; ComprimentoNominal: 8 mm; LarguraNominal: 45 mm
Type - IFC.REVIGRÉS-Dados de sustentabilidade-Wall Sweeps - PotencialPrivacaoDeAguaConsumoDeAguaPonderado: 4.5; EnergiaTermicaExportada: 0; ItemENovo: Sim; ItemEParcialmenteReciclado: 0.03; ItemEReciclado: Sim; VidaÚtilEsperada: 50; SubstanciasPerigosas: Não; PotencialDeEsgotamentoAbioticoDosRecursosFosseis: 203; PotencialDeEsgotamentoAbioticoDosRecursosNaoFosseisMineraisEMetais: 0.000701; PotencialDeAquecimentoGlobalBiogenico: -0.48; CombustiveisFosseisComPotencialDeAquecimentoGlobal: 13.9; PotencialDeAquecimentoGlobalUsoDoSoloEMudancaDeUsoDoSolo: 0.0246; PotencialDeEutrofizacaoFraccaoDeNutrientesQueAtingemOCompartimentoFinalDeAguaDoce: 0.000189; PotencialDeEutrofizacaoFraccaoDeNutrientesQueAtingemOCompartimentoFinalMarinho: 0.0122; EnergiaRecuperada: 0.00739; ConsumoDeAguaDoce: 0.113; UtilizacaoLiquidaDeAguaDoce: 0.113; ResiduosPerigososEliminados: 0.00221; ResiduosNaoPerigososEliminados: 1.83; MassaTotalDeResiduosRadioactivosEliminados: 0.000394; EnergiaElectricaExportada: 1.55; MateriaisParaRecuperacaoDeEnergia: 0.00739; MateriaisParaReciclagem: 0.0253; UnidadeEPD: 1 m²
Type - IFC.REVIGRÉS-Dados gerais-Wall Sweeps - Nome: REVIGRÉS-URBAN-RB-8X45-NAT-URBAN BONE; TipoProduto: Prensado a seco: grupo BIa UGL | Grés porcelânico técnico; NumeroDeRegistoDAP: EPD-REV-20240006-CCC1-EN; ReferenciaDAP: -; UrlDOP: -
Pset_ProvisionForVoid - Shape: Undefined; Width: 1000 mm; Depth: 1000 mm
IFC.REVIGRÉS-Dados do fabricante-Wall Sweeps - Type: Wall Sweep: REVIGRÉS-URBAN-RB-8X45-NAT-BONE
IFC.REVIGRÉS-Dados de desempenho-Wall Sweeps - Type: Wall Sweep: REVIGRÉS-URBAN-RB-8X45-NAT-BONE
IFC.REVIGRÉS-Dados de especificação-Wall Sweeps - Type: Wall Sweep: REVIGRÉS-URBAN-RB-8X45-NAT-BONE
IFC.REVIGRÉS-Dados geométricos-Wall Sweeps - Type: Wall Sweep: REVIGRÉS-URBAN-RB-8X45-NAT-BONE
IFC.REVIGRÉS-Dados de sustentabilidade-Wall Sweeps - Type: Wall Sweep: REVIGRÉS-URBAN-RB-8X45-NAT-BONE

# IfcBuildingElementProxy: Wall Sweep:REVIGRÉS-URBAN-RB-8X45-NAT-CRAFT, Wall Sweep:REVIGRÉS-URBAN-RB-8X45-NAT-CRAFT:182768
In: Level 1
Type - Pset_ManufacturerTypeInformation - Manufacturer: REVIGRÉS
Type - Pset_ProductRequirements - Category: Wall Sweeps
Type - IFC.REVIGRÉS-Dados do fabricante-Wall Sweeps - FabricanteURL: https://www.revigres.pt/; ReferenciaModelo: Urban; Acabamento: NAT; IdentificadorDoOperadorEconomico: 501840856; UrlFabricanteArtigo: https://www.revigres.pt/colecoes/urban; PaisOrigem: Portugal
Type - IFC.REVIGRÉS-Dados de desempenho-Wall Sweeps - Rectilinearidade: ± 0.3% máx. ± 1.5 mm; Ortogonalidade: ± 0.3% máx. ± 1.8 mm; PlanaridadeDaSuperficie: ± 0.3% máx. ± 1.8 mm; AbsorcaoDeAgua: < 0.05%; ModuloDeRuptura: > 45 N/mm²; ResistenciaAFlexao: > 2000 N; ResistenciaAAbrasaoProfunda: < 120 mm³; DilatacaoTermicaLinear: ≤ 8,0x10-6 °C-1; ResistenciaAoChoqueTermico: Resiste; DurabilidadeResistenciaAoGeloDegelo: Resiste; ResistenciaAoEscorregamentoDIN51130: R9; ResistenciaAoEscorregamentoDIN51097: A; ResistenciaAoEscorregamentoENV51097: A; ResistenciaAoDeslizamentoENV12633: Class 1; ResistenciaAoEscorregamentoANSIA1371: ≥0,42; ResistenciaAoEscorregamentoENV12633: Class 1; ResistenciaAsManchas: Class 5; ResistenciaABaixasConcentracoesDeAcidosEAlcalis: Classe LA; ResistenciaAAltasConcentracoesDeAcidosEAlcalis: Classe HA; LibertacaoDeCadmio: 0; LibertacaoDeChumbo: 0
Type - IFC.REVIGRÉS-Dados de especificação-Wall Sweeps - VariacaoTonalidade: 2; NivelDeTrafego: 0; EPavimento: Não; ERevestimento: Sim; EExterno: Sim
Type - IFC.REVIGRÉS-Dados geométricos-Wall Sweeps - AlturaNominal: 8.5 mm; ComprimentoNominal: 8 mm; LarguraNominal: 45 mm
Type - IFC.REVIGRÉS-Dados de sustentabilidade-Wall Sweeps - PotencialPrivacaoDeAguaConsumoDeAguaPonderado: 4.5; EnergiaTermicaExportada: 0; ItemENovo: Sim; ItemEParcialmenteReciclado: 0.19; ItemEReciclado: Sim; VidaÚtilEsperada: 50; SubstanciasPerigosas: Não; PotencialDeEsgotamentoAbioticoDosRecursosFosseis: 203; PotencialDeEsgotamentoAbioticoDosRecursosNaoFosseisMineraisEMetais: 0.000701; PotencialDeAquecimentoGlobalBiogenico: -0.48; CombustiveisFosseisComPotencialDeAquecimentoGlobal: 13.9; PotencialDeAquecimentoGlobalUsoDoSoloEMudancaDeUsoDoSolo: 0.0246; PotencialDeEutrofizacaoFraccaoDeNutrientesQueAtingemOCompartimentoFinalDeAguaDoce: 0.000189; PotencialDeEutrofizacaoFraccaoDeNutrientesQueAtingemOCompartimentoFinalMarinho: 0.0122; EnergiaRecuperada: 0.00739; ConsumoDeAguaDoce: 0.113; UtilizacaoLiquidaDeAguaDoce: 0.113; ResiduosPerigososEliminados: 0.00221; ResiduosNaoPerigososEliminados: 1.83; MassaTotalDeResiduosRadioactivosEliminados: 0.000394; EnergiaElectricaExportada: 1.55; MateriaisParaRecuperacaoDeEnergia: 0.00739; MateriaisParaReciclagem: 0.0253; UnidadeEPD: 1 m²
Type - IFC.REVIGRÉS-Dados gerais-Wall Sweeps - Nome: REVIGRÉS-URBAN-RB-8X45-NAT-URBAN CRAFT; TipoProduto: Prensado a seco: grupo BIa UGL | Grés porcelânico técnico; NumeroDeRegistoDAP: EPD-REV-20240006-CCC1-EN; ReferenciaDAP: -; UrlDOP: -
Pset_ProvisionForVoid - Shape: Undefined; Width: 1000 mm; Depth: 1000 mm
IFC.REVIGRÉS-Dados do fabricante-Wall Sweeps - Type: Wall Sweep: REVIGRÉS-URBAN-RB-8X45-NAT-CRAFT
IFC.REVIGRÉS-Dados de desempenho-Wall Sweeps - Type: Wall Sweep: REVIGRÉS-URBAN-RB-8X45-NAT-CRAFT
IFC.REVIGRÉS-Dados de especificação-Wall Sweeps - Type: Wall Sweep: REVIGRÉS-URBAN-RB-8X45-NAT-CRAFT
IFC.REVIGRÉS-Dados geométricos-Wall Sweeps - Type: Wall Sweep: REVIGRÉS-URBAN-RB-8X45-NAT-CRAFT
IFC.REVIGRÉS-Dados de sustentabilidade-Wall Sweeps - Type: Wall Sweep: REVIGRÉS-URBAN-RB-8X45-NAT-CRAFT

# IfcBuildingElementProxy: Wall Sweep:REVIGRÉS-URBAN-RB-8X45-NAT-FOG, Wall Sweep:REVIGRÉS-URBAN-RB-8X45-NAT-FOG:182778
In: Level 1
Type - Pset_ManufacturerTypeInformation - Manufacturer: REVIGRÉS
Type - Pset_ProductRequirements - Category: Wall Sweeps
Type - IFC.REVIGRÉS-Dados do fabricante-Wall Sweeps - FabricanteURL: https://www.revigres.pt/; ReferenciaModelo: Urban; Acabamento: NAT; IdentificadorDoOperadorEconomico: 501840856; UrlFabricanteArtigo: https://www.revigres.pt/colecoes/urban; PaisOrigem: Portugal
Type - IFC.REVIGRÉS-Dados de desempenho-Wall Sweeps - Rectilinearidade: ± 0.3% máx. ± 1.5 mm; Ortogonalidade: ± 0.3% máx. ± 1.8 mm; PlanaridadeDaSuperficie: ± 0.3% máx. ± 1.8 mm; AbsorcaoDeAgua: < 0.05%; ModuloDeRuptura: > 45 N/mm²; ResistenciaAFlexao: > 2000 N; ResistenciaAAbrasaoProfunda: < 120 mm³; DilatacaoTermicaLinear: ≤ 8,0x10-6 °C-1; ResistenciaAoChoqueTermico: Resiste; DurabilidadeResistenciaAoGeloDegelo: Resiste; ResistenciaAoEscorregamentoDIN51130: R9; ResistenciaAoEscorregamentoDIN51097: A; ResistenciaAoEscorregamentoENV51097: A; ResistenciaAoDeslizamentoENV12633: Class 1; ResistenciaAoEscorregamentoANSIA1371: ≥0,42; ResistenciaAoEscorregamentoENV12633: Class 1; ResistenciaAsManchas: Class 5; ResistenciaABaixasConcentracoesDeAcidosEAlcalis: Classe LA; ResistenciaAAltasConcentracoesDeAcidosEAlcalis: Classe HA; LibertacaoDeCadmio: 0; LibertacaoDeChumbo: 0
Type - IFC.REVIGRÉS-Dados de especificação-Wall Sweeps - VariacaoTonalidade: 2; NivelDeTrafego: 0; EPavimento: Não; ERevestimento: Sim; EExterno: Sim
Type - IFC.REVIGRÉS-Dados geométricos-Wall Sweeps - AlturaNominal: 8.5 mm; ComprimentoNominal: 8 mm; LarguraNominal: 45 mm
Type - IFC.REVIGRÉS-Dados de sustentabilidade-Wall Sweeps - PotencialPrivacaoDeAguaConsumoDeAguaPonderado: 4.5; EnergiaTermicaExportada: 0; ItemENovo: Sim; ItemEParcialmenteReciclado: 0.23; ItemEReciclado: Sim; VidaÚtilEsperada: 50; SubstanciasPerigosas: Não; PotencialDeEsgotamentoAbioticoDosRecursosFosseis: 203; PotencialDeEsgotamentoAbioticoDosRecursosNaoFosseisMineraisEMetais: 0.000701; PotencialDeAquecimentoGlobalBiogenico: -0.48; CombustiveisFosseisComPotencialDeAquecimentoGlobal: 13.9; PotencialDeAquecimentoGlobalUsoDoSoloEMudancaDeUsoDoSolo: 0.0246; PotencialDeEutrofizacaoFraccaoDeNutrientesQueAtingemOCompartimentoFinalDeAguaDoce: 0.000189; PotencialDeEutrofizacaoFraccaoDeNutrientesQueAtingemOCompartimentoFinalMarinho: 0.0122; EnergiaRecuperada: 0.00739; ConsumoDeAguaDoce: 0.113; UtilizacaoLiquidaDeAguaDoce: 0.113; ResiduosPerigososEliminados: 0.00221; ResiduosNaoPerigososEliminados: 1.83; MassaTotalDeResiduosRadioactivosEliminados: 0.000394; EnergiaElectricaExportada: 1.55; MateriaisParaRecuperacaoDeEnergia: 0.00739; MateriaisParaReciclagem: 0.0253; UnidadeEPD: 1 m²
Type - IFC.REVIGRÉS-Dados gerais-Wall Sweeps - Nome: REVIGRÉS-URBAN-RB-8X45-NAT-URBAN FOG; TipoProduto: Prensado a seco: grupo BIa UGL | Grés porcelânico técnico; NumeroDeRegistoDAP: EPD-REV-20240006-CCC1-EN; ReferenciaDAP: -; UrlDOP: -
Pset_ProvisionForVoid - Shape: Undefined; Width: 1000 mm; Depth: 1000 mm
IFC.REVIGRÉS-Dados do fabricante-Wall Sweeps - Type: Wall Sweep: REVIGRÉS-URBAN-RB-8X45-NAT-FOG
IFC.REVIGRÉS-Dados de desempenho-Wall Sweeps - Type: Wall Sweep: REVIGRÉS-URBAN-RB-8X45-NAT-FOG
IFC.REVIGRÉS-Dados de especificação-Wall Sweeps - Type: Wall Sweep: REVIGRÉS-URBAN-RB-8X45-NAT-FOG
IFC.REVIGRÉS-Dados geométricos-Wall Sweeps - Type: Wall Sweep: REVIGRÉS-URBAN-RB-8X45-NAT-FOG
IFC.REVIGRÉS-Dados de sustentabilidade-Wall Sweeps - Type: Wall Sweep: REVIGRÉS-URBAN-RB-8X45-NAT-FOG

# IfcBuildingElementProxy: Wall Sweep:REVIGRÉS-URBAN-RB-8X45-NAT-GRIS, Wall Sweep:REVIGRÉS-URBAN-RB-8X45-NAT-GRIS:182788
In: Level 1
Type - Pset_ManufacturerTypeInformation - Manufacturer: REVIGRÉS
Type - Pset_ProductRequirements - Category: Wall Sweeps
Type - IFC.REVIGRÉS-Dados do fabricante-Wall Sweeps - FabricanteURL: https://www.revigres.pt/; ReferenciaModelo: Urban; Acabamento: NAT; IdentificadorDoOperadorEconomico: 501840856; UrlFabricanteArtigo: https://www.revigres.pt/colecoes/urban; PaisOrigem: Portugal
Type - IFC.REVIGRÉS-Dados de desempenho-Wall Sweeps - Rectilinearidade: ± 0.3% máx. ± 1.5 mm; Ortogonalidade: ± 0.3% máx. ± 1.8 mm; PlanaridadeDaSuperficie: ± 0.3% máx. ± 1.8 mm; AbsorcaoDeAgua: < 0.05%; ModuloDeRuptura: > 45 N/mm²; ResistenciaAFlexao: > 2000 N; ResistenciaAAbrasaoProfunda: < 120 mm³; DilatacaoTermicaLinear: ≤ 8,0x10-6 °C-1; ResistenciaAoChoqueTermico: Resiste; DurabilidadeResistenciaAoGeloDegelo: Resiste; ResistenciaAoEscorregamentoDIN51130: R9; ResistenciaAoEscorregamentoDIN51097: A; ResistenciaAoEscorregamentoENV51097: A; ResistenciaAoDeslizamentoENV12633: Class 1; ResistenciaAoEscorregamentoANSIA1371: ≥0,42; ResistenciaAoEscorregamentoENV12633: Class 1; ResistenciaAsManchas: Class 5; ResistenciaABaixasConcentracoesDeAcidosEAlcalis: Classe LA; ResistenciaAAltasConcentracoesDeAcidosEAlcalis: Classe HA; LibertacaoDeCadmio: 0; LibertacaoDeChumbo: 0
Type - IFC.REVIGRÉS-Dados de especificação-Wall Sweeps - VariacaoTonalidade: 2; NivelDeTrafego: 0; EPavimento: Não; ERevestimento: Sim; EExterno: Sim
Type - IFC.REVIGRÉS-Dados geométricos-Wall Sweeps - AlturaNominal: 8.5 mm; ComprimentoNominal: 8 mm; LarguraNominal: 45 mm
Type - IFC.REVIGRÉS-Dados de sustentabilidade-Wall Sweeps - PotencialPrivacaoDeAguaConsumoDeAguaPonderado: 4.5; EnergiaTermicaExportada: 0; ItemENovo: Sim; ItemEParcialmenteReciclado: 0.23; ItemEReciclado: Sim; VidaÚtilEsperada: 50; SubstanciasPerigosas: Não; PotencialDeEsgotamentoAbioticoDosRecursosFosseis: 203; PotencialDeEsgotamentoAbioticoDosRecursosNaoFosseisMineraisEMetais: 0.000701; PotencialDeAquecimentoGlobalBiogenico: -0.48; CombustiveisFosseisComPotencialDeAquecimentoGlobal: 13.9; PotencialDeAquecimentoGlobalUsoDoSoloEMudancaDeUsoDoSolo: 0.0246; PotencialDeEutrofizacaoFraccaoDeNutrientesQueAtingemOCompartimentoFinalDeAguaDoce: 0.000189; PotencialDeEutrofizacaoFraccaoDeNutrientesQueAtingemOCompartimentoFinalMarinho: 0.0122; EnergiaRecuperada: 0.00739; ConsumoDeAguaDoce: 0.113; UtilizacaoLiquidaDeAguaDoce: 0.113; ResiduosPerigososEliminados: 0.00221; ResiduosNaoPerigososEliminados: 1.83; MassaTotalDeResiduosRadioactivosEliminados: 0.000394; EnergiaElectricaExportada: 1.55; MateriaisParaRecuperacaoDeEnergia: 0.00739; MateriaisParaReciclagem: 0.0253; UnidadeEPD: 1 m²
Type - IFC.REVIGRÉS-Dados gerais-Wall Sweeps - Nome: REVIGRÉS-URBAN-RB-8X45-NAT-URBAN GRIS; TipoProduto: Prensado a seco: grupo BIa UGL | Grés porcelânico técnico; NumeroDeRegistoDAP: EPD-REV-20240006-CCC1-EN; ReferenciaDAP: -; UrlDOP: -
Pset_ProvisionForVoid - Shape: Undefined; Width: 1000 mm; Depth: 1000 mm
IFC.REVIGRÉS-Dados do fabricante-Wall Sweeps - Type: Wall Sweep: REVIGRÉS-URBAN-RB-8X45-NAT-GRIS
IFC.REVIGRÉS-Dados de desempenho-Wall Sweeps - Type: Wall Sweep: REVIGRÉS-URBAN-RB-8X45-NAT-GRIS
IFC.REVIGRÉS-Dados de especificação-Wall Sweeps - Type: Wall Sweep: REVIGRÉS-URBAN-RB-8X45-NAT-GRIS
IFC.REVIGRÉS-Dados geométricos-Wall Sweeps - Type: Wall Sweep: REVIGRÉS-URBAN-RB-8X45-NAT-GRIS
IFC.REVIGRÉS-Dados de sustentabilidade-Wall Sweeps - Type: Wall Sweep: REVIGRÉS-URBAN-RB-8X45-NAT-GRIS

# IfcBuildingElementProxy: Wall Sweep:REVIGRÉS-URBAN-RB-8X45-NAT-OFFWHITE, Wall Sweep:REVIGRÉS-URBAN-RB-8X45-NAT-OFFWHITE:182798
In: Level 1
Type - Pset_ManufacturerTypeInformation - Manufacturer: REVIGRÉS
Type - Pset_ProductRequirements - Category: Wall Sweeps
Type - IFC.REVIGRÉS-Dados do fabricante-Wall Sweeps - FabricanteURL: https://www.revigres.pt/; ReferenciaModelo: Urban; Acabamento: NAT; IdentificadorDoOperadorEconomico: 501840856; UrlFabricanteArtigo: https://www.revigres.pt/colecoes/urban; PaisOrigem: Portugal
Type - IFC.REVIGRÉS-Dados de desempenho-Wall Sweeps - Rectilinearidade: ± 0.3% máx. ± 1.5 mm; Ortogonalidade: ± 0.3% máx. ± 1.8 mm; PlanaridadeDaSuperficie: ± 0.3% máx. ± 1.8 mm; AbsorcaoDeAgua: < 0.05%; ModuloDeRuptura: > 45 N/mm²; ResistenciaAFlexao: > 2000 N; ResistenciaAAbrasaoProfunda: < 120 mm³; DilatacaoTermicaLinear: ≤ 8,0x10-6 °C-1; ResistenciaAoChoqueTermico: Resiste; DurabilidadeResistenciaAoGeloDegelo: Resiste; ResistenciaAoEscorregamentoDIN51130: R9; ResistenciaAoEscorregamentoDIN51097: A; ResistenciaAoEscorregamentoENV51097: A; ResistenciaAoDeslizamentoENV12633: Class 1; ResistenciaAoEscorregamentoANSIA1371: ≥0,42; ResistenciaAoEscorregamentoENV12633: Class 1; ResistenciaAsManchas: Class 5; ResistenciaABaixasConcentracoesDeAcidosEAlcalis: Classe LA; ResistenciaAAltasConcentracoesDeAcidosEAlcalis: Classe HA; LibertacaoDeCadmio: 0; LibertacaoDeChumbo: 0
Type - IFC.REVIGRÉS-Dados de especificação-Wall Sweeps - VariacaoTonalidade: 2; NivelDeTrafego: 0; EPavimento: Não; ERevestimento: Sim; EExterno: Sim
Type - IFC.REVIGRÉS-Dados geométricos-Wall Sweeps - AlturaNominal: 8.5 mm; ComprimentoNominal: 8 mm; LarguraNominal: 45 mm
Type - IFC.REVIGRÉS-Dados de sustentabilidade-Wall Sweeps - PotencialPrivacaoDeAguaConsumoDeAguaPonderado: 4.5; EnergiaTermicaExportada: 0; ItemENovo: Sim; ItemEParcialmenteReciclado: 0.03; ItemEReciclado: Sim; VidaÚtilEsperada: 50; SubstanciasPerigosas: Não; PotencialDeEsgotamentoAbioticoDosRecursosFosseis: 203; PotencialDeEsgotamentoAbioticoDosRecursosNaoFosseisMineraisEMetais: 0.000701; PotencialDeAquecimentoGlobalBiogenico: -0.48; CombustiveisFosseisComPotencialDeAquecimentoGlobal: 13.9; PotencialDeAquecimentoGlobalUsoDoSoloEMudancaDeUsoDoSolo: 0.0246; PotencialDeEutrofizacaoFraccaoDeNutrientesQueAtingemOCompartimentoFinalDeAguaDoce: 0.000189; PotencialDeEutrofizacaoFraccaoDeNutrientesQueAtingemOCompartimentoFinalMarinho: 0.0122; EnergiaRecuperada: 0.00739; ConsumoDeAguaDoce: 0.113; UtilizacaoLiquidaDeAguaDoce: 0.113; ResiduosPerigososEliminados: 0.00221; ResiduosNaoPerigososEliminados: 1.83; MassaTotalDeResiduosRadioactivosEliminados: 0.000394; EnergiaElectricaExportada: 1.55; MateriaisParaRecuperacaoDeEnergia: 0.00739; MateriaisParaReciclagem: 0.0253; UnidadeEPD: 1 m²
Type - IFC.REVIGRÉS-Dados gerais-Wall Sweeps - Nome: REVIGRÉS-URBAN-RB-8X45-NAT-URBAN OFFWHITE; TipoProduto: Prensado a seco: grupo BIa UGL | Grés porcelânico técnico; NumeroDeRegistoDAP: EPD-REV-20240006-CCC1-EN; ReferenciaDAP: -; UrlDOP: -
Pset_ProvisionForVoid - Shape: Undefined; Width: 1000 mm; Depth: 1000 mm
IFC.REVIGRÉS-Dados do fabricante-Wall Sweeps - Type: Wall Sweep: REVIGRÉS-URBAN-RB-8X45-NAT-OFFWHITE
IFC.REVIGRÉS-Dados de desempenho-Wall Sweeps - Type: Wall Sweep: REVIGRÉS-URBAN-RB-8X45-NAT-OFFWHITE
IFC.REVIGRÉS-Dados de especificação-Wall Sweeps - Type: Wall Sweep: REVIGRÉS-URBAN-RB-8X45-NAT-OFFWHITE
IFC.REVIGRÉS-Dados geométricos-Wall Sweeps - Type: Wall Sweep: REVIGRÉS-URBAN-RB-8X45-NAT-OFFWHITE
IFC.REVIGRÉS-Dados de sustentabilidade-Wall Sweeps - Type: Wall Sweep: REVIGRÉS-URBAN-RB-8X45-NAT-OFFWHITE

# IfcBuildingElementProxy: Wall Sweep:REVIGRÉS-URBAN-RB-8X45-RECT-ANTRACITE, Wall Sweep:REVIGRÉS-URBAN-RB-8X45-RECT-ANTRACITE:182672
In: Level 1
Type - Pset_ManufacturerTypeInformation - Manufacturer: REVIGRÉS
Type - Pset_ProductRequirements - Category: Wall Sweeps
Type - IFC.REVIGRÉS-Dados do fabricante-Wall Sweeps - FabricanteURL: https://www.revigres.pt/; ReferenciaModelo: Urban; Acabamento: RECT; IdentificadorDoOperadorEconomico: 501840856; UrlFabricanteArtigo: https://www.revigres.pt/colecoes/urban; PaisOrigem: Portugal
Type - IFC.REVIGRÉS-Dados de desempenho-Wall Sweeps - Rectilinearidade: ± 0.2% máx.± 0.8 mm; Ortogonalidade: ± 0.2% máx.± 1.5 mm; PlanaridadeDaSuperficie: ± 0.3% máx. ± 1.8 mm; AbsorcaoDeAgua: < 0.05%; ModuloDeRuptura: > 45 N/mm²; ResistenciaAFlexao: > 1500 N; ResistenciaAAbrasaoProfunda: < 120 mm³; DilatacaoTermicaLinear: ≤ 8,0x10-6 °C-1; ResistenciaAoChoqueTermico: Resiste; DurabilidadeResistenciaAoGeloDegelo: Resiste; ResistenciaAoEscorregamentoDIN51130: R9; ResistenciaAoEscorregamentoDIN51097: A; ResistenciaAoEscorregamentoENV51097: A; ResistenciaAoDeslizamentoENV12633: Class 1; ResistenciaAoEscorregamentoANSIA1371: ≥0,42; ResistenciaAoEscorregamentoENV12633: Class 1; ResistenciaAsManchas: Class 5; ResistenciaABaixasConcentracoesDeAcidosEAlcalis: Classe LA; ResistenciaAAltasConcentracoesDeAcidosEAlcalis: Classe HA; LibertacaoDeCadmio: 0; LibertacaoDeChumbo: 0
Type - IFC.REVIGRÉS-Dados de especificação-Wall Sweeps - VariacaoTonalidade: 2; NivelDeTrafego: 0; EPavimento: Não; ERevestimento: Sim; EExterno: Sim
Type - IFC.REVIGRÉS-Dados geométricos-Wall Sweeps - AlturaNominal: 8.5 mm; ComprimentoNominal: 8 mm; LarguraNominal: 4435 mm
Type - IFC.REVIGRÉS-Dados de sustentabilidade-Wall Sweeps - PotencialPrivacaoDeAguaConsumoDeAguaPonderado: 4.5; EnergiaTermicaExportada: 0; ItemENovo: Sim; ItemEParcialmenteReciclado: 0.29; ItemEReciclado: Sim; VidaÚtilEsperada: 50; SubstanciasPerigosas: Não; PotencialDeEsgotamentoAbioticoDosRecursosFosseis: 203; PotencialDeEsgotamentoAbioticoDosRecursosNaoFosseisMineraisEMetais: 0.000701; PotencialDeAquecimentoGlobalBiogenico: -0.48; CombustiveisFosseisComPotencialDeAquecimentoGlobal: 13.9; PotencialDeAquecimentoGlobalUsoDoSoloEMudancaDeUsoDoSolo: 0.0246; PotencialDeEutrofizacaoFraccaoDeNutrientesQueAtingemOCompartimentoFinalDeAguaDoce: 0.000189; PotencialDeEutrofizacaoFraccaoDeNutrientesQueAtingemOCompartimentoFinalMarinho: 0.0122; EnergiaRecuperada: 0.00739; ConsumoDeAguaDoce: 0.113; UtilizacaoLiquidaDeAguaDoce: 0.113; ResiduosPerigososEliminados: 0.00221; ResiduosNaoPerigososEliminados: 1.83; MassaTotalDeResiduosRadioactivosEliminados: 0.000394; EnergiaElectricaExportada: 1.55; MateriaisParaRecuperacaoDeEnergia: 0.00739; MateriaisParaReciclagem: 0.0253; UnidadeEPD: 1 m²
Type - IFC.REVIGRÉS-Dados gerais-Wall Sweeps - Nome: REVIGRÉS-URBAN-RB-8X45-RECT-URBAN ANTRACITE; TipoProduto: Prensado a seco: grupo BIa UGL | Grés porcelânico técnico; NumeroDeRegistoDAP: EPD-REV-20240006-CCC1-EN; ReferenciaDAP: -; UrlDOP: -
Pset_ProvisionForVoid - Shape: Undefined; Width: 1000 mm; Depth: 1000 mm
IFC.REVIGRÉS-Dados do fabricante-Wall Sweeps - Type: Wall Sweep: REVIGRÉS-URBAN-RB-8X45-RECT-ANTRACITE
IFC.REVIGRÉS-Dados de desempenho-Wall Sweeps - Type: Wall Sweep: REVIGRÉS-URBAN-RB-8X45-RECT-ANTRACITE
IFC.REVIGRÉS-Dados de especificação-Wall Sweeps - Type: Wall Sweep: REVIGRÉS-URBAN-RB-8X45-RECT-ANTRACITE
IFC.REVIGRÉS-Dados geométricos-Wall Sweeps - Type: Wall Sweep: REVIGRÉS-URBAN-RB-8X45-RECT-ANTRACITE
IFC.REVIGRÉS-Dados de sustentabilidade-Wall Sweeps - Type: Wall Sweep: REVIGRÉS-URBAN-RB-8X45-RECT-ANTRACITE

# IfcBuildingElementProxy: Wall Sweep:REVIGRÉS-URBAN-RB-8X45-RECT-BONE, Wall Sweep:REVIGRÉS-URBAN-RB-8X45-RECT-BONE:182752
In: Level 1
Type - Pset_ManufacturerTypeInformation - Manufacturer: REVIGRÉS
Type - Pset_ProductRequirements - Category: Wall Sweeps
Type - IFC.REVIGRÉS-Dados do fabricante-Wall Sweeps - FabricanteURL: https://www.revigres.pt/; ReferenciaModelo: Urban; Acabamento: RECT; IdentificadorDoOperadorEconomico: 501840856; UrlFabricanteArtigo: https://www.revigres.pt/colecoes/urban; PaisOrigem: Portugal
Type - IFC.REVIGRÉS-Dados de desempenho-Wall Sweeps - Rectilinearidade: ± 0.2% máx.± 0.8 mm; Ortogonalidade: ± 0.2% máx.± 1.5 mm; PlanaridadeDaSuperficie: ± 0.3% máx. ± 1.8 mm; AbsorcaoDeAgua: < 0.05%; ModuloDeRuptura: > 45 N/mm²; ResistenciaAFlexao: > 1500 N; ResistenciaAAbrasaoProfunda: < 120 mm³; DilatacaoTermicaLinear: ≤ 8,0x10-6 °C-1; ResistenciaAoChoqueTermico: Resiste; DurabilidadeResistenciaAoGeloDegelo: Resiste; ResistenciaAoEscorregamentoDIN51130: R9; ResistenciaAoEscorregamentoDIN51097: A; ResistenciaAoEscorregamentoENV51097: A; ResistenciaAoDeslizamentoENV12633: Class 1; ResistenciaAoEscorregamentoANSIA1371: ≥0,42; ResistenciaAoEscorregamentoENV12633: Class 1; ResistenciaAsManchas: Class 5; ResistenciaABaixasConcentracoesDeAcidosEAlcalis: Classe LA; ResistenciaAAltasConcentracoesDeAcidosEAlcalis: Classe HA; LibertacaoDeCadmio: 0; LibertacaoDeChumbo: 0
Type - IFC.REVIGRÉS-Dados de especificação-Wall Sweeps - VariacaoTonalidade: 2; NivelDeTrafego: 0; EPavimento: Não; ERevestimento: Sim; EExterno: Sim
Type - IFC.REVIGRÉS-Dados geométricos-Wall Sweeps - AlturaNominal: 8.5 mm; ComprimentoNominal: 8 mm; LarguraNominal: 4435 mm
Type - IFC.REVIGRÉS-Dados de sustentabilidade-Wall Sweeps - PotencialPrivacaoDeAguaConsumoDeAguaPonderado: 4.5; EnergiaTermicaExportada: 0; ItemENovo: Sim; ItemEParcialmenteReciclado: 0.03; ItemEReciclado: Sim; VidaÚtilEsperada: 50; SubstanciasPerigosas: Não; PotencialDeEsgotamentoAbioticoDosRecursosFosseis: 203; PotencialDeEsgotamentoAbioticoDosRecursosNaoFosseisMineraisEMetais: 0.000701; PotencialDeAquecimentoGlobalBiogenico: -0.48; CombustiveisFosseisComPotencialDeAquecimentoGlobal: 13.9; PotencialDeAquecimentoGlobalUsoDoSoloEMudancaDeUsoDoSolo: 0.0246; PotencialDeEutrofizacaoFraccaoDeNutrientesQueAtingemOCompartimentoFinalDeAguaDoce: 0.000189; PotencialDeEutrofizacaoFraccaoDeNutrientesQueAtingemOCompartimentoFinalMarinho: 0.0122; EnergiaRecuperada: 0.00739; ConsumoDeAguaDoce: 0.113; UtilizacaoLiquidaDeAguaDoce: 0.113; ResiduosPerigososEliminados: 0.00221; ResiduosNaoPerigososEliminados: 1.83; MassaTotalDeResiduosRadioactivosEliminados: 0.000394; EnergiaElectricaExportada: 1.55; MateriaisParaRecuperacaoDeEnergia: 0.00739; MateriaisParaReciclagem: 0.0253; UnidadeEPD: 1 m²
Type - IFC.REVIGRÉS-Dados gerais-Wall Sweeps - Nome: REVIGRÉS-URBAN-RB-8X45-RECT-URBAN BONE; TipoProduto: Prensado a seco: grupo BIa UGL | Grés porcelânico técnico; NumeroDeRegistoDAP: EPD-REV-20240006-CCC1-EN; ReferenciaDAP: -; UrlDOP: -
Pset_ProvisionForVoid - Shape: Undefined; Width: 1000 mm; Depth: 1000 mm
IFC.REVIGRÉS-Dados do fabricante-Wall Sweeps - Type: Wall Sweep: REVIGRÉS-URBAN-RB-8X45-RECT-BONE
IFC.REVIGRÉS-Dados de desempenho-Wall Sweeps - Type: Wall Sweep: REVIGRÉS-URBAN-RB-8X45-RECT-BONE
IFC.REVIGRÉS-Dados de especificação-Wall Sweeps - Type: Wall Sweep: REVIGRÉS-URBAN-RB-8X45-RECT-BONE
IFC.REVIGRÉS-Dados geométricos-Wall Sweeps - Type: Wall Sweep: REVIGRÉS-URBAN-RB-8X45-RECT-BONE
IFC.REVIGRÉS-Dados de sustentabilidade-Wall Sweeps - Type: Wall Sweep: REVIGRÉS-URBAN-RB-8X45-RECT-BONE

# IfcBuildingElementProxy: Wall Sweep:REVIGRÉS-URBAN-RB-8X45-RECT-CRAFT, Wall Sweep:REVIGRÉS-URBAN-RB-8X45-RECT-CRAFT:182762
In: Level 1
Type - Pset_ManufacturerTypeInformation - Manufacturer: REVIGRÉS
Type - Pset_ProductRequirements - Category: Wall Sweeps
Type - IFC.REVIGRÉS-Dados do fabricante-Wall Sweeps - FabricanteURL: https://www.revigres.pt/; ReferenciaModelo: Urban; Acabamento: RECT; IdentificadorDoOperadorEconomico: 501840856; UrlFabricanteArtigo: https://www.revigres.pt/colecoes/urban; PaisOrigem: Portugal
Type - IFC.REVIGRÉS-Dados de desempenho-Wall Sweeps - Rectilinearidade: ± 0.2% máx.± 0.8 mm; Ortogonalidade: ± 0.2% máx.± 1.5 mm; PlanaridadeDaSuperficie: ± 0.3% máx. ± 1.8 mm; AbsorcaoDeAgua: < 0.05%; ModuloDeRuptura: > 45 N/mm²; ResistenciaAFlexao: > 1500 N; ResistenciaAAbrasaoProfunda: < 120 mm³; DilatacaoTermicaLinear: ≤ 8,0x10-6 °C-1; ResistenciaAoChoqueTermico: Resiste; DurabilidadeResistenciaAoGeloDegelo: Resiste; ResistenciaAoEscorregamentoDIN51130: R9; ResistenciaAoEscorregamentoDIN51097: A; ResistenciaAoEscorregamentoENV51097: A; ResistenciaAoDeslizamentoENV12633: Class 1; ResistenciaAoEscorregamentoANSIA1371: ≥0,42; ResistenciaAoEscorregamentoENV12633: Class 1; ResistenciaAsManchas: Class 5; ResistenciaABaixasConcentracoesDeAcidosEAlcalis: Classe LA; ResistenciaAAltasConcentracoesDeAcidosEAlcalis: Classe HA; LibertacaoDeCadmio: 0; LibertacaoDeChumbo: 0
Type - IFC.REVIGRÉS-Dados de especificação-Wall Sweeps - VariacaoTonalidade: 2; NivelDeTrafego: 0; EPavimento: Não; ERevestimento: Sim; EExterno: Sim
Type - IFC.REVIGRÉS-Dados geométricos-Wall Sweeps - AlturaNominal: 8.5 mm; ComprimentoNominal: 8 mm; LarguraNominal: 4435 mm
Type - IFC.REVIGRÉS-Dados de sustentabilidade-Wall Sweeps - PotencialPrivacaoDeAguaConsumoDeAguaPonderado: 4.5; EnergiaTermicaExportada: 0; ItemENovo: Sim; ItemEParcialmenteReciclado: 0.19; ItemEReciclado: Sim; VidaÚtilEsperada: 50; SubstanciasPerigosas: Não; PotencialDeEsgotamentoAbioticoDosRecursosFosseis: 203; PotencialDeEsgotamentoAbioticoDosRecursosNaoFosseisMineraisEMetais: 0.000701; PotencialDeAquecimentoGlobalBiogenico: -0.48; CombustiveisFosseisComPotencialDeAquecimentoGlobal: 13.9; PotencialDeAquecimentoGlobalUsoDoSoloEMudancaDeUsoDoSolo: 0.0246; PotencialDeEutrofizacaoFraccaoDeNutrientesQueAtingemOCompartimentoFinalDeAguaDoce: 0.000189; PotencialDeEutrofizacaoFraccaoDeNutrientesQueAtingemOCompartimentoFinalMarinho: 0.0122; EnergiaRecuperada: 0.00739; ConsumoDeAguaDoce: 0.113; UtilizacaoLiquidaDeAguaDoce: 0.113; ResiduosPerigososEliminados: 0.00221; ResiduosNaoPerigososEliminados: 1.83; MassaTotalDeResiduosRadioactivosEliminados: 0.000394; EnergiaElectricaExportada: 1.55; MateriaisParaRecuperacaoDeEnergia: 0.00739; MateriaisParaReciclagem: 0.0253; UnidadeEPD: 1 m²
Type - IFC.REVIGRÉS-Dados gerais-Wall Sweeps - Nome: REVIGRÉS-URBAN-RB-8X45-RECT-URBAN CRAFT; TipoProduto: Prensado a seco: grupo BIa UGL | Grés porcelânico técnico; NumeroDeRegistoDAP: EPD-REV-20240006-CCC1-EN; ReferenciaDAP: -; UrlDOP: -
Pset_ProvisionForVoid - Shape: Undefined; Width: 1000 mm; Depth: 1000 mm
IFC.REVIGRÉS-Dados do fabricante-Wall Sweeps - Type: Wall Sweep: REVIGRÉS-URBAN-RB-8X45-RECT-CRAFT
IFC.REVIGRÉS-Dados de desempenho-Wall Sweeps - Type: Wall Sweep: REVIGRÉS-URBAN-RB-8X45-RECT-CRAFT
IFC.REVIGRÉS-Dados de especificação-Wall Sweeps - Type: Wall Sweep: REVIGRÉS-URBAN-RB-8X45-RECT-CRAFT
IFC.REVIGRÉS-Dados geométricos-Wall Sweeps - Type: Wall Sweep: REVIGRÉS-URBAN-RB-8X45-RECT-CRAFT
IFC.REVIGRÉS-Dados de sustentabilidade-Wall Sweeps - Type: Wall Sweep: REVIGRÉS-URBAN-RB-8X45-RECT-CRAFT

# IfcBuildingElementProxy: Wall Sweep:REVIGRÉS-URBAN-RB-8X45-RECT-FOG, Wall Sweep:REVIGRÉS-URBAN-RB-8X45-RECT-FOG:182772
In: Level 1
Type - Pset_ManufacturerTypeInformation - Manufacturer: REVIGRÉS
Type - Pset_ProductRequirements - Category: Wall Sweeps
Type - IFC.REVIGRÉS-Dados do fabricante-Wall Sweeps - FabricanteURL: https://www.revigres.pt/; ReferenciaModelo: Urban; Acabamento: RECT; IdentificadorDoOperadorEconomico: 501840856; UrlFabricanteArtigo: https://www.revigres.pt/colecoes/urban; PaisOrigem: Portugal
Type - IFC.REVIGRÉS-Dados de desempenho-Wall Sweeps - Rectilinearidade: ± 0.2% máx.± 0.8 mm; Ortogonalidade: ± 0.2% máx.± 1.5 mm; PlanaridadeDaSuperficie: ± 0.3% máx. ± 1.8 mm; AbsorcaoDeAgua: < 0.05%; ModuloDeRuptura: > 45 N/mm²; ResistenciaAFlexao: > 1500 N; ResistenciaAAbrasaoProfunda: < 120 mm³; DilatacaoTermicaLinear: ≤ 8,0x10-6 °C-1; ResistenciaAoChoqueTermico: Resiste; DurabilidadeResistenciaAoGeloDegelo: Resiste; ResistenciaAoEscorregamentoDIN51130: R9; ResistenciaAoEscorregamentoDIN51097: A; ResistenciaAoEscorregamentoENV51097: A; ResistenciaAoDeslizamentoENV12633: Class 1; ResistenciaAoEscorregamentoANSIA1371: ≥0,42; ResistenciaAoEscorregamentoENV12633: Class 1; ResistenciaAsManchas: Class 5; ResistenciaABaixasConcentracoesDeAcidosEAlcalis: Classe LA; ResistenciaAAltasConcentracoesDeAcidosEAlcalis: Classe HA; LibertacaoDeCadmio: 0; LibertacaoDeChumbo: 0
Type - IFC.REVIGRÉS-Dados de especificação-Wall Sweeps - VariacaoTonalidade: 2; NivelDeTrafego: 0; EPavimento: Não; ERevestimento: Sim; EExterno: Sim
Type - IFC.REVIGRÉS-Dados geométricos-Wall Sweeps - AlturaNominal: 8.5 mm; ComprimentoNominal: 8 mm; LarguraNominal: 4435 mm
Type - IFC.REVIGRÉS-Dados de sustentabilidade-Wall Sweeps - PotencialPrivacaoDeAguaConsumoDeAguaPonderado: 4.5; EnergiaTermicaExportada: 0; ItemENovo: Sim; ItemEParcialmenteReciclado: 0.23; ItemEReciclado: Sim; VidaÚtilEsperada: 50; SubstanciasPerigosas: Não; PotencialDeEsgotamentoAbioticoDosRecursosFosseis: 203; PotencialDeEsgotamentoAbioticoDosRecursosNaoFosseisMineraisEMetais: 0.000701; PotencialDeAquecimentoGlobalBiogenico: -0.48; CombustiveisFosseisComPotencialDeAquecimentoGlobal: 13.9; PotencialDeAquecimentoGlobalUsoDoSoloEMudancaDeUsoDoSolo: 0.0246; PotencialDeEutrofizacaoFraccaoDeNutrientesQueAtingemOCompartimentoFinalDeAguaDoce: 0.000189; PotencialDeEutrofizacaoFraccaoDeNutrientesQueAtingemOCompartimentoFinalMarinho: 0.0122; EnergiaRecuperada: 0.00739; ConsumoDeAguaDoce: 0.113; UtilizacaoLiquidaDeAguaDoce: 0.113; ResiduosPerigososEliminados: 0.00221; ResiduosNaoPerigososEliminados: 1.83; MassaTotalDeResiduosRadioactivosEliminados: 0.000394; EnergiaElectricaExportada: 1.55; MateriaisParaRecuperacaoDeEnergia: 0.00739; MateriaisParaReciclagem: 0.0253; UnidadeEPD: 1 m²
Type - IFC.REVIGRÉS-Dados gerais-Wall Sweeps - Nome: REVIGRÉS-URBAN-RB-8X45-RECT-URBAN FOG; TipoProduto: Prensado a seco: grupo BIa UGL | Grés porcelânico técnico; NumeroDeRegistoDAP: EPD-REV-20240006-CCC1-EN; ReferenciaDAP: -; UrlDOP: -
Pset_ProvisionForVoid - Shape: Undefined; Width: 1000 mm; Depth: 1000 mm
IFC.REVIGRÉS-Dados do fabricante-Wall Sweeps - Type: Wall Sweep: REVIGRÉS-URBAN-RB-8X45-RECT-FOG
IFC.REVIGRÉS-Dados de desempenho-Wall Sweeps - Type: Wall Sweep: REVIGRÉS-URBAN-RB-8X45-RECT-FOG
IFC.REVIGRÉS-Dados de especificação-Wall Sweeps - Type: Wall Sweep: REVIGRÉS-URBAN-RB-8X45-RECT-FOG
IFC.REVIGRÉS-Dados geométricos-Wall Sweeps - Type: Wall Sweep: REVIGRÉS-URBAN-RB-8X45-RECT-FOG
IFC.REVIGRÉS-Dados de sustentabilidade-Wall Sweeps - Type: Wall Sweep: REVIGRÉS-URBAN-RB-8X45-RECT-FOG

# IfcBuildingElementProxy: Wall Sweep:REVIGRÉS-URBAN-RB-8X45-RECT-GRIS, Wall Sweep:REVIGRÉS-URBAN-RB-8X45-RECT-GRIS:182782
In: Level 1
Type - Pset_ManufacturerTypeInformation - Manufacturer: REVIGRÉS
Type - Pset_ProductRequirements - Category: Wall Sweeps
Type - IFC.REVIGRÉS-Dados do fabricante-Wall Sweeps - FabricanteURL: https://www.revigres.pt/; ReferenciaModelo: Urban; Acabamento: RECT; IdentificadorDoOperadorEconomico: 501840856; UrlFabricanteArtigo: https://www.revigres.pt/colecoes/urban; PaisOrigem: Portugal
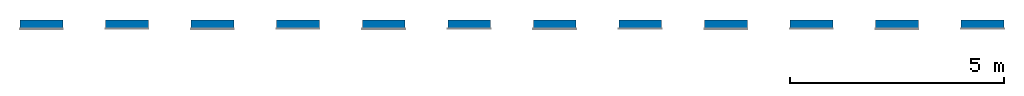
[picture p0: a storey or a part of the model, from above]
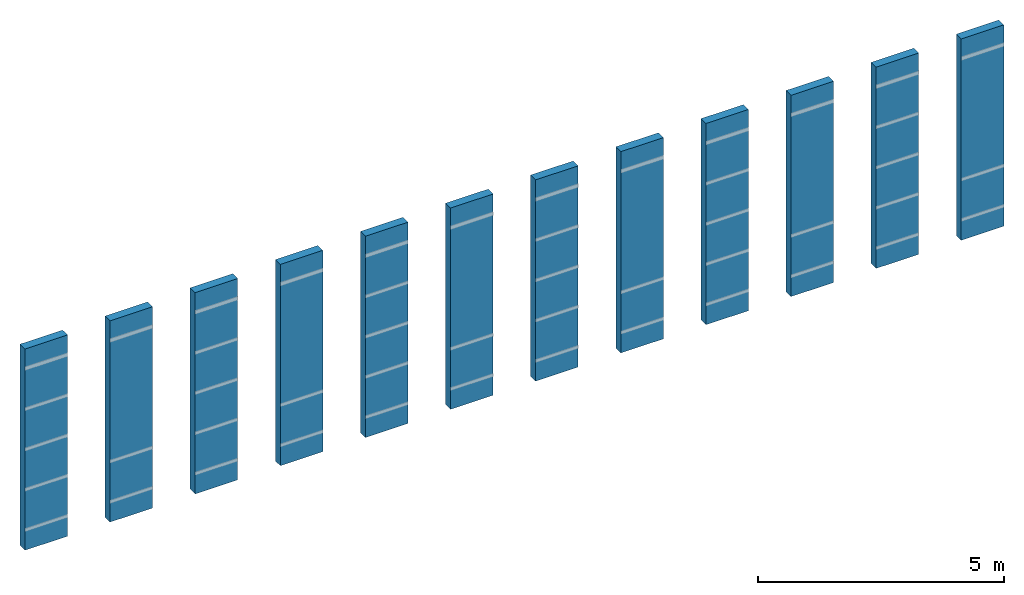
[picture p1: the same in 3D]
Properties of the parts of a building model (IFC2X3), part 2 of 3

# IfcBuildingElementProxy: Wall Sweep:REVIGRÉS-URBAN-RB-8X45-RECT-GRIS, Wall Sweep:REVIGRÉS-URBAN-RB-8X45-RECT-GRIS:182782
Type - IFC.REVIGRÉS-Dados de desempenho-Wall Sweeps - Rectilinearidade: ± 0.2% máx.± 0.8 mm; Ortogonalidade: ± 0.2% máx.± 1.5 mm; PlanaridadeDaSuperficie: ± 0.3% máx. ± 1.8 mm; AbsorcaoDeAgua: < 0.05%; ModuloDeRuptura: > 45 N/mm²; ResistenciaAFlexao: > 1500 N; ResistenciaAAbrasaoProfunda: < 120 mm³; DilatacaoTermicaLinear: ≤ 8,0x10-6 °C-1; ResistenciaAoChoqueTermico: Resiste; DurabilidadeResistenciaAoGeloDegelo: Resiste; ResistenciaAoEscorregamentoDIN51130: R9; ResistenciaAoEscorregamentoDIN51097: A; ResistenciaAoEscorregamentoENV51097: A; ResistenciaAoDeslizamentoENV12633: Class 1; ResistenciaAoEscorregamentoANSIA1371: ≥0,42; ResistenciaAoEscorregamentoENV12633: Class 1; ResistenciaAsManchas: Class 5; ResistenciaABaixasConcentracoesDeAcidosEAlcalis: Classe LA; ResistenciaAAltasConcentracoesDeAcidosEAlcalis: Classe HA; LibertacaoDeCadmio: 0; LibertacaoDeChumbo: 0
Type - IFC.REVIGRÉS-Dados de especificação-Wall Sweeps - VariacaoTonalidade: 2; NivelDeTrafego: 0; EPavimento: Não; ERevestimento: Sim; EExterno: Sim
Type - IFC.REVIGRÉS-Dados geométricos-Wall Sweeps - AlturaNominal: 8.5 mm; ComprimentoNominal: 8 mm; LarguraNominal: 4435 mm
Type - IFC.REVIGRÉS-Dados de sustentabilidade-Wall Sweeps - PotencialPrivacaoDeAguaConsumoDeAguaPonderado: 4.5; EnergiaTermicaExportada: 0; ItemENovo: Sim; ItemEParcialmenteReciclado: 0.23; ItemEReciclado: Sim; VidaÚtilEsperada: 50; SubstanciasPerigosas: Não; PotencialDeEsgotamentoAbioticoDosRecursosFosseis: 203; PotencialDeEsgotamentoAbioticoDosRecursosNaoFosseisMineraisEMetais: 0.000701; PotencialDeAquecimentoGlobalBiogenico: -0.48; CombustiveisFosseisComPotencialDeAquecimentoGlobal: 13.9; PotencialDeAquecimentoGlobalUsoDoSoloEMudancaDeUsoDoSolo: 0.0246; PotencialDeEutrofizacaoFraccaoDeNutrientesQueAtingemOCompartimentoFinalDeAguaDoce: 0.000189; PotencialDeEutrofizacaoFraccaoDeNutrientesQueAtingemOCompartimentoFinalMarinho: 0.0122; EnergiaRecuperada: 0.00739; ConsumoDeAguaDoce: 0.113; UtilizacaoLiquidaDeAguaDoce: 0.113; ResiduosPerigososEliminados: 0.00221; ResiduosNaoPerigososEliminados: 1.83; MassaTotalDeResiduosRadioactivosEliminados: 0.000394; EnergiaElectricaExportada: 1.55; MateriaisParaRecuperacaoDeEnergia: 0.00739; MateriaisParaReciclagem: 0.0253; UnidadeEPD: 1 m²
Type - IFC.REVIGRÉS-Dados gerais-Wall Sweeps - Nome: REVIGRÉS-URBAN-RB-8X45-RECT-URBAN GRIS; TipoProduto: Prensado a seco: grupo BIa UGL | Grés porcelânico técnico; NumeroDeRegistoDAP: EPD-REV-20240006-CCC1-EN; ReferenciaDAP: -; UrlDOP: -
Pset_ProvisionForVoid - Shape: Undefined; Width: 1000 mm; Depth: 1000 mm
IFC.REVIGRÉS-Dados do fabricante-Wall Sweeps - Type: Wall Sweep: REVIGRÉS-URBAN-RB-8X45-RECT-GRIS
IFC.REVIGRÉS-Dados de desempenho-Wall Sweeps - Type: Wall Sweep: REVIGRÉS-URBAN-RB-8X45-RECT-GRIS
IFC.REVIGRÉS-Dados de especificação-Wall Sweeps - Type: Wall Sweep: REVIGRÉS-URBAN-RB-8X45-RECT-GRIS
IFC.REVIGRÉS-Dados geométricos-Wall Sweeps - Type: Wall Sweep: REVIGRÉS-URBAN-RB-8X45-RECT-GRIS
IFC.REVIGRÉS-Dados de sustentabilidade-Wall Sweeps - Type: Wall Sweep: REVIGRÉS-URBAN-RB-8X45-RECT-GRIS

# IfcBuildingElementProxy: Wall Sweep:REVIGRÉS-URBAN-RB-8X45-RECT-OFFWHITE, Wall Sweep:REVIGRÉS-URBAN-RB-8X45-RECT-OFFWHITE:182792
In: Level 1
Type - Pset_ManufacturerTypeInformation - Manufacturer: REVIGRÉS
Type - Pset_ProductRequirements - Category: Wall Sweeps
Type - IFC.REVIGRÉS-Dados do fabricante-Wall Sweeps - FabricanteURL: https://www.revigres.pt/; ReferenciaModelo: Urban; Acabamento: RECT; IdentificadorDoOperadorEconomico: 501840856; UrlFabricanteArtigo: https://www.revigres.pt/colecoes/urban; PaisOrigem: Portugal
Type - IFC.REVIGRÉS-Dados de desempenho-Wall Sweeps - Rectilinearidade: ± 0.2% máx.± 0.8 mm; Ortogonalidade: ± 0.2% máx.± 1.5 mm; PlanaridadeDaSuperficie: ± 0.3% máx. ± 1.8 mm; AbsorcaoDeAgua: < 0.05%; ModuloDeRuptura: > 45 N/mm²; ResistenciaAFlexao: > 1500 N; ResistenciaAAbrasaoProfunda: < 120 mm³; DilatacaoTermicaLinear: ≤ 8,0x10-6 °C-1; ResistenciaAoChoqueTermico: Resiste; DurabilidadeResistenciaAoGeloDegelo: Resiste; ResistenciaAoEscorregamentoDIN51130: R9; ResistenciaAoEscorregamentoDIN51097: A; ResistenciaAoEscorregamentoENV51097: A; ResistenciaAoDeslizamentoENV12633: Class 1; ResistenciaAoEscorregamentoANSIA1371: ≥0,42; ResistenciaAoEscorregamentoENV12633: Class 1; ResistenciaAsManchas: Class 5; ResistenciaABaixasConcentracoesDeAcidosEAlcalis: Classe LA; ResistenciaAAltasConcentracoesDeAcidosEAlcalis: Classe HA; LibertacaoDeCadmio: 0; LibertacaoDeChumbo: 0
Type - IFC.REVIGRÉS-Dados de especificação-Wall Sweeps - VariacaoTonalidade: 2; NivelDeTrafego: 0; EPavimento: Não; ERevestimento: Sim; EExterno: Sim
Type - IFC.REVIGRÉS-Dados geométricos-Wall Sweeps - AlturaNominal: 8.5 mm; ComprimentoNominal: 8 mm; LarguraNominal: 4435 mm
Type - IFC.REVIGRÉS-Dados de sustentabilidade-Wall Sweeps - PotencialPrivacaoDeAguaConsumoDeAguaPonderado: 4.5; EnergiaTermicaExportada: 0; ItemENovo: Sim; ItemEParcialmenteReciclado: 0.03; ItemEReciclado: Sim; VidaÚtilEsperada: 50; SubstanciasPerigosas: Não; PotencialDeEsgotamentoAbioticoDosRecursosFosseis: 203; PotencialDeEsgotamentoAbioticoDosRecursosNaoFosseisMineraisEMetais: 0.000701; PotencialDeAquecimentoGlobalBiogenico: -0.48; CombustiveisFosseisComPotencialDeAquecimentoGlobal: 13.9; PotencialDeAquecimentoGlobalUsoDoSoloEMudancaDeUsoDoSolo: 0.0246; PotencialDeEutrofizacaoFraccaoDeNutrientesQueAtingemOCompartimentoFinalDeAguaDoce: 0.000189; PotencialDeEutrofizacaoFraccaoDeNutrientesQueAtingemOCompartimentoFinalMarinho: 0.0122; EnergiaRecuperada: 0.00739; ConsumoDeAguaDoce: 0.113; UtilizacaoLiquidaDeAguaDoce: 0.113; ResiduosPerigososEliminados: 0.00221; ResiduosNaoPerigososEliminados: 1.83; MassaTotalDeResiduosRadioactivosEliminados: 0.000394; EnergiaElectricaExportada: 1.55; MateriaisParaRecuperacaoDeEnergia: 0.00739; MateriaisParaReciclagem: 0.0253; UnidadeEPD: 1 m²
Type - IFC.REVIGRÉS-Dados gerais-Wall Sweeps - Nome: REVIGRÉS-URBAN-RB-8X45-RECT-URBAN OFFWHITE; TipoProduto: Prensado a seco: grupo BIa UGL | Grés porcelânico técnico; NumeroDeRegistoDAP: EPD-REV-20240006-CCC1-EN; ReferenciaDAP: -; UrlDOP: -
Pset_ProvisionForVoid - Shape: Undefined; Width: 1000 mm; Depth: 1000 mm
IFC.REVIGRÉS-Dados do fabricante-Wall Sweeps - Type: Wall Sweep: REVIGRÉS-URBAN-RB-8X45-RECT-OFFWHITE
IFC.REVIGRÉS-Dados de desempenho-Wall Sweeps - Type: Wall Sweep: REVIGRÉS-URBAN-RB-8X45-RECT-OFFWHITE
IFC.REVIGRÉS-Dados de especificação-Wall Sweeps - Type: Wall Sweep: REVIGRÉS-URBAN-RB-8X45-RECT-OFFWHITE
IFC.REVIGRÉS-Dados geométricos-Wall Sweeps - Type: Wall Sweep: REVIGRÉS-URBAN-RB-8X45-RECT-OFFWHITE
IFC.REVIGRÉS-Dados de sustentabilidade-Wall Sweeps - Type: Wall Sweep: REVIGRÉS-URBAN-RB-8X45-RECT-OFFWHITE

# IfcBuildingElementProxy: Wall Sweep:REVIGRÉS-URBAN-RB-8X60-NAT-ANTRACITE, Wall Sweep:REVIGRÉS-URBAN-RB-8X60-NAT-ANTRACITE:182749
In: Level 1
Type - Pset_ManufacturerTypeInformation - Manufacturer: REVIGRÉS
Type - Pset_ProductRequirements - Category: Wall Sweeps
Type - IFC.REVIGRÉS-Dados do fabricante-Wall Sweeps - FabricanteURL: https://www.revigres.pt/; ReferenciaModelo: Urban; Acabamento: NAT; IdentificadorDoOperadorEconomico: 501840856; UrlFabricanteArtigo: https://www.revigres.pt/colecoes/urban; PaisOrigem: Portugal
Type - IFC.REVIGRÉS-Dados de desempenho-Wall Sweeps - Rectilinearidade: ± 0.3% máx. ± 1.5 mm; Ortogonalidade: ± 0.3% máx. ± 1.8 mm; PlanaridadeDaSuperficie: ± 0.3% máx. ± 1.8 mm; AbsorcaoDeAgua: < 0.05%; ModuloDeRuptura: > 45 N/mm²; ResistenciaAFlexao: > 2000 N; ResistenciaAAbrasaoProfunda: < 120 mm³; DilatacaoTermicaLinear: ≤ 8,0x10-6 °C-1; ResistenciaAoChoqueTermico: Resiste; DurabilidadeResistenciaAoGeloDegelo: Resiste; ResistenciaAoEscorregamentoDIN51130: R9; ResistenciaAoEscorregamentoDIN51097: A; ResistenciaAoEscorregamentoENV51097: A; ResistenciaAoDeslizamentoENV12633: Class 1; ResistenciaAoEscorregamentoANSIA1371: ≥0,42; ResistenciaAoEscorregamentoENV12633: Class 1; ResistenciaAsManchas: Class 5; ResistenciaABaixasConcentracoesDeAcidosEAlcalis: Classe LA; ResistenciaAAltasConcentracoesDeAcidosEAlcalis: Classe HA; LibertacaoDeCadmio: 0; LibertacaoDeChumbo: 0
Type - IFC.REVIGRÉS-Dados de especificação-Wall Sweeps - VariacaoTonalidade: 2; NivelDeTrafego: 0; EPavimento: Não; ERevestimento: Sim; EExterno: Sim
Type - IFC.REVIGRÉS-Dados geométricos-Wall Sweeps - AlturaNominal: 8.5 mm; ComprimentoNominal: 8 mm; LarguraNominal: 60 mm
Type - IFC.REVIGRÉS-Dados de sustentabilidade-Wall Sweeps - PotencialPrivacaoDeAguaConsumoDeAguaPonderado: 4.5; EnergiaTermicaExportada: 0; ItemENovo: Sim; ItemEParcialmenteReciclado: 0.29; ItemEReciclado: Sim; VidaÚtilEsperada: 50; SubstanciasPerigosas: Não; PotencialDeEsgotamentoAbioticoDosRecursosFosseis: 203; PotencialDeEsgotamentoAbioticoDosRecursosNaoFosseisMineraisEMetais: 0.000701; PotencialDeAquecimentoGlobalBiogenico: -0.48; CombustiveisFosseisComPotencialDeAquecimentoGlobal: 13.9; PotencialDeAquecimentoGlobalUsoDoSoloEMudancaDeUsoDoSolo: 0.0246; PotencialDeEutrofizacaoFraccaoDeNutrientesQueAtingemOCompartimentoFinalDeAguaDoce: 0.000189; PotencialDeEutrofizacaoFraccaoDeNutrientesQueAtingemOCompartimentoFinalMarinho: 0.0122; EnergiaRecuperada: 0.00739; ConsumoDeAguaDoce: 0.113; UtilizacaoLiquidaDeAguaDoce: 0.113; ResiduosPerigososEliminados: 0.00221; ResiduosNaoPerigososEliminados: 1.83; MassaTotalDeResiduosRadioactivosEliminados: 0.000394; EnergiaElectricaExportada: 1.55; MateriaisParaRecuperacaoDeEnergia: 0.00739; MateriaisParaReciclagem: 0.0253; UnidadeEPD: 1 m²
Type - IFC.REVIGRÉS-Dados gerais-Wall Sweeps - Nome: REVIGRÉS-URBAN-RB-8X60-NAT-URBAN ANTRACITE; TipoProduto: Prensado a seco: grupo BIa UGL | Grés porcelânico técnico; NumeroDeRegistoDAP: EPD-REV-20240006-CCC1-EN; ReferenciaDAP: -; UrlDOP: -
Pset_ProvisionForVoid - Shape: Undefined; Width: 1000 mm; Depth: 1000 mm
IFC.REVIGRÉS-Dados do fabricante-Wall Sweeps - Type: Wall Sweep: REVIGRÉS-URBAN-RB-8X60-NAT-ANTRACITE
IFC.REVIGRÉS-Dados de desempenho-Wall Sweeps - Type: Wall Sweep: REVIGRÉS-URBAN-RB-8X60-NAT-ANTRACITE
IFC.REVIGRÉS-Dados de especificação-Wall Sweeps - Type: Wall Sweep: REVIGRÉS-URBAN-RB-8X60-NAT-ANTRACITE
IFC.REVIGRÉS-Dados geométricos-Wall Sweeps - Type: Wall Sweep: REVIGRÉS-URBAN-RB-8X60-NAT-ANTRACITE
IFC.REVIGRÉS-Dados de sustentabilidade-Wall Sweeps - Type: Wall Sweep: REVIGRÉS-URBAN-RB-8X60-NAT-ANTRACITE

# IfcBuildingElementProxy: Wall Sweep:REVIGRÉS-URBAN-RB-8X60-NAT-BONE, Wall Sweep:REVIGRÉS-URBAN-RB-8X60-NAT-BONE:182759
In: Level 1
Type - Pset_ManufacturerTypeInformation - Manufacturer: REVIGRÉS
Type - Pset_ProductRequirements - Category: Wall Sweeps
Type - IFC.REVIGRÉS-Dados do fabricante-Wall Sweeps - FabricanteURL: https://www.revigres.pt/; ReferenciaModelo: Urban; Acabamento: NAT; IdentificadorDoOperadorEconomico: 501840856; UrlFabricanteArtigo: https://www.revigres.pt/colecoes/urban; PaisOrigem: Portugal
Type - IFC.REVIGRÉS-Dados de desempenho-Wall Sweeps - Rectilinearidade: ± 0.3% máx. ± 1.5 mm; Ortogonalidade: ± 0.3% máx. ± 1.8 mm; PlanaridadeDaSuperficie: ± 0.3% máx. ± 1.8 mm; AbsorcaoDeAgua: < 0.05%; ModuloDeRuptura: > 45 N/mm²; ResistenciaAFlexao: > 2000 N; ResistenciaAAbrasaoProfunda: < 120 mm³; DilatacaoTermicaLinear: ≤ 8,0x10-6 °C-1; ResistenciaAoChoqueTermico: Resiste; DurabilidadeResistenciaAoGeloDegelo: Resiste; ResistenciaAoEscorregamentoDIN51130: R9; ResistenciaAoEscorregamentoDIN51097: A; ResistenciaAoEscorregamentoENV51097: A; ResistenciaAoDeslizamentoENV12633: Class 1; ResistenciaAoEscorregamentoANSIA1371: ≥0,42; ResistenciaAoEscorregamentoENV12633: Class 1; ResistenciaAsManchas: Class 5; ResistenciaABaixasConcentracoesDeAcidosEAlcalis: Classe LA; ResistenciaAAltasConcentracoesDeAcidosEAlcalis: Classe HA; LibertacaoDeCadmio: 0; LibertacaoDeChumbo: 0
Type - IFC.REVIGRÉS-Dados de especificação-Wall Sweeps - VariacaoTonalidade: 2; NivelDeTrafego: 0; EPavimento: Não; ERevestimento: Sim; EExterno: Sim
Type - IFC.REVIGRÉS-Dados geométricos-Wall Sweeps - AlturaNominal: 8.5 mm; ComprimentoNominal: 8 mm; LarguraNominal: 60 mm
Type - IFC.REVIGRÉS-Dados de sustentabilidade-Wall Sweeps - PotencialPrivacaoDeAguaConsumoDeAguaPonderado: 4.5; EnergiaTermicaExportada: 0; ItemENovo: Sim; ItemEParcialmenteReciclado: 0.03; ItemEReciclado: Sim; VidaÚtilEsperada: 50; SubstanciasPerigosas: Não; PotencialDeEsgotamentoAbioticoDosRecursosFosseis: 203; PotencialDeEsgotamentoAbioticoDosRecursosNaoFosseisMineraisEMetais: 0.000701; PotencialDeAquecimentoGlobalBiogenico: -0.48; CombustiveisFosseisComPotencialDeAquecimentoGlobal: 13.9; PotencialDeAquecimentoGlobalUsoDoSoloEMudancaDeUsoDoSolo: 0.0246; PotencialDeEutrofizacaoFraccaoDeNutrientesQueAtingemOCompartimentoFinalDeAguaDoce: 0.000189; PotencialDeEutrofizacaoFraccaoDeNutrientesQueAtingemOCompartimentoFinalMarinho: 0.0122; EnergiaRecuperada: 0.00739; ConsumoDeAguaDoce: 0.113; UtilizacaoLiquidaDeAguaDoce: 0.113; ResiduosPerigososEliminados: 0.00221; ResiduosNaoPerigososEliminados: 1.83; MassaTotalDeResiduosRadioactivosEliminados: 0.000394; EnergiaElectricaExportada: 1.55; MateriaisParaRecuperacaoDeEnergia: 0.00739; MateriaisParaReciclagem: 0.0253; UnidadeEPD: 1 m²
Type - IFC.REVIGRÉS-Dados gerais-Wall Sweeps - Nome: REVIGRÉS-URBAN-RB-8X60-NAT-URBAN BONE; TipoProduto: Prensado a seco: grupo BIa UGL | Grés porcelânico técnico; NumeroDeRegistoDAP: EPD-REV-20240006-CCC1-EN; ReferenciaDAP: -; UrlDOP: -
Pset_ProvisionForVoid - Shape: Undefined; Width: 1000 mm; Depth: 1000 mm
IFC.REVIGRÉS-Dados do fabricante-Wall Sweeps - Type: Wall Sweep: REVIGRÉS-URBAN-RB-8X60-NAT-BONE
IFC.REVIGRÉS-Dados de desempenho-Wall Sweeps - Type: Wall Sweep: REVIGRÉS-URBAN-RB-8X60-NAT-BONE
IFC.REVIGRÉS-Dados de especificação-Wall Sweeps - Type: Wall Sweep: REVIGRÉS-URBAN-RB-8X60-NAT-BONE
IFC.REVIGRÉS-Dados geométricos-Wall Sweeps - Type: Wall Sweep: REVIGRÉS-URBAN-RB-8X60-NAT-BONE
IFC.REVIGRÉS-Dados de sustentabilidade-Wall Sweeps - Type: Wall Sweep: REVIGRÉS-URBAN-RB-8X60-NAT-BONE

# IfcBuildingElementProxy: Wall Sweep:REVIGRÉS-URBAN-RB-8X60-NAT-CRAFT, Wall Sweep:REVIGRÉS-URBAN-RB-8X60-NAT-CRAFT:182769
In: Level 1
Type - Pset_ManufacturerTypeInformation - Manufacturer: REVIGRÉS
Type - Pset_ProductRequirements - Category: Wall Sweeps
Type - IFC.REVIGRÉS-Dados do fabricante-Wall Sweeps - FabricanteURL: https://www.revigres.pt/; ReferenciaModelo: Urban; Acabamento: NAT; IdentificadorDoOperadorEconomico: 501840856; UrlFabricanteArtigo: https://www.revigres.pt/colecoes/urban; PaisOrigem: Portugal
Type - IFC.REVIGRÉS-Dados de desempenho-Wall Sweeps - Rectilinearidade: ± 0.3% máx. ± 1.5 mm; Ortogonalidade: ± 0.3% máx. ± 1.8 mm; PlanaridadeDaSuperficie: ± 0.3% máx. ± 1.8 mm; AbsorcaoDeAgua: < 0.05%; ModuloDeRuptura: > 45 N/mm²; ResistenciaAFlexao: > 2000 N; ResistenciaAAbrasaoProfunda: < 120 mm³; DilatacaoTermicaLinear: ≤ 8,0x10-6 °C-1; ResistenciaAoChoqueTermico: Resiste; DurabilidadeResistenciaAoGeloDegelo: Resiste; ResistenciaAoEscorregamentoDIN51130: R9; ResistenciaAoEscorregamentoDIN51097: A; ResistenciaAoEscorregamentoENV51097: A; ResistenciaAoDeslizamentoENV12633: Class 1; ResistenciaAoEscorregamentoANSIA1371: ≥0,42; ResistenciaAoEscorregamentoENV12633: Class 1; ResistenciaAsManchas: Class 5; ResistenciaABaixasConcentracoesDeAcidosEAlcalis: Classe LA; ResistenciaAAltasConcentracoesDeAcidosEAlcalis: Classe HA; LibertacaoDeCadmio: 0; LibertacaoDeChumbo: 0
Type - IFC.REVIGRÉS-Dados de especificação-Wall Sweeps - VariacaoTonalidade: 2; NivelDeTrafego: 0; EPavimento: Não; ERevestimento: Sim; EExterno: Sim
Type - IFC.REVIGRÉS-Dados geométricos-Wall Sweeps - AlturaNominal: 8.5 mm; ComprimentoNominal: 8 mm; LarguraNominal: 60 mm
Type - IFC.REVIGRÉS-Dados de sustentabilidade-Wall Sweeps - PotencialPrivacaoDeAguaConsumoDeAguaPonderado: 4.5; EnergiaTermicaExportada: 0; ItemENovo: Sim; ItemEParcialmenteReciclado: 0.19; ItemEReciclado: Sim; VidaÚtilEsperada: 50; SubstanciasPerigosas: Não; PotencialDeEsgotamentoAbioticoDosRecursosFosseis: 203; PotencialDeEsgotamentoAbioticoDosRecursosNaoFosseisMineraisEMetais: 0.000701; PotencialDeAquecimentoGlobalBiogenico: -0.48; CombustiveisFosseisComPotencialDeAquecimentoGlobal: 13.9; PotencialDeAquecimentoGlobalUsoDoSoloEMudancaDeUsoDoSolo: 0.0246; PotencialDeEutrofizacaoFraccaoDeNutrientesQueAtingemOCompartimentoFinalDeAguaDoce: 0.000189; PotencialDeEutrofizacaoFraccaoDeNutrientesQueAtingemOCompartimentoFinalMarinho: 0.0122; EnergiaRecuperada: 0.00739; ConsumoDeAguaDoce: 0.113; UtilizacaoLiquidaDeAguaDoce: 0.113; ResiduosPerigososEliminados: 0.00221; ResiduosNaoPerigososEliminados: 1.83; MassaTotalDeResiduosRadioactivosEliminados: 0.000394; EnergiaElectricaExportada: 1.55; MateriaisParaRecuperacaoDeEnergia: 0.00739; MateriaisParaReciclagem: 0.0253; UnidadeEPD: 1 m²
Type - IFC.REVIGRÉS-Dados gerais-Wall Sweeps - Nome: REVIGRÉS-URBAN-RB-8X60-NAT-URBAN CRAFT; TipoProduto: Prensado a seco: grupo BIa UGL | Grés porcelânico técnico; NumeroDeRegistoDAP: EPD-REV-20240006-CCC1-EN; ReferenciaDAP: -; UrlDOP: -
Pset_ProvisionForVoid - Shape: Undefined; Width: 1000 mm; Depth: 1000 mm
IFC.REVIGRÉS-Dados do fabricante-Wall Sweeps - Type: Wall Sweep: REVIGRÉS-URBAN-RB-8X60-NAT-CRAFT
IFC.REVIGRÉS-Dados de desempenho-Wall Sweeps - Type: Wall Sweep: REVIGRÉS-URBAN-RB-8X60-NAT-CRAFT
IFC.REVIGRÉS-Dados de especificação-Wall Sweeps - Type: Wall Sweep: REVIGRÉS-URBAN-RB-8X60-NAT-CRAFT
IFC.REVIGRÉS-Dados geométricos-Wall Sweeps - Type: Wall Sweep: REVIGRÉS-URBAN-RB-8X60-NAT-CRAFT
IFC.REVIGRÉS-Dados de sustentabilidade-Wall Sweeps - Type: Wall Sweep: REVIGRÉS-URBAN-RB-8X60-NAT-CRAFT

# IfcBuildingElementProxy: Wall Sweep:REVIGRÉS-URBAN-RB-8X60-NAT-FOG, Wall Sweep:REVIGRÉS-URBAN-RB-8X60-NAT-FOG:182779
In: Level 1
Type - Pset_ManufacturerTypeInformation - Manufacturer: REVIGRÉS
Type - Pset_ProductRequirements - Category: Wall Sweeps
Type - IFC.REVIGRÉS-Dados do fabricante-Wall Sweeps - FabricanteURL: https://www.revigres.pt/; ReferenciaModelo: Urban; Acabamento: NAT; IdentificadorDoOperadorEconomico: 501840856; UrlFabricanteArtigo: https://www.revigres.pt/colecoes/urban; PaisOrigem: Portugal
Type - IFC.REVIGRÉS-Dados de desempenho-Wall Sweeps - Rectilinearidade: ± 0.3% máx. ± 1.5 mm; Ortogonalidade: ± 0.3% máx. ± 1.8 mm; PlanaridadeDaSuperficie: ± 0.3% máx. ± 1.8 mm; AbsorcaoDeAgua: < 0.05%; ModuloDeRuptura: > 45 N/mm²; ResistenciaAFlexao: > 2000 N; ResistenciaAAbrasaoProfunda: < 120 mm³; DilatacaoTermicaLinear: ≤ 8,0x10-6 °C-1; ResistenciaAoChoqueTermico: Resiste; DurabilidadeResistenciaAoGeloDegelo: Resiste; ResistenciaAoEscorregamentoDIN51130: R9; ResistenciaAoEscorregamentoDIN51097: A; ResistenciaAoEscorregamentoENV51097: A; ResistenciaAoDeslizamentoENV12633: Class 1; ResistenciaAoEscorregamentoANSIA1371: ≥0,42; ResistenciaAoEscorregamentoENV12633: Class 1; ResistenciaAsManchas: Class 5; ResistenciaABaixasConcentracoesDeAcidosEAlcalis: Classe LA; ResistenciaAAltasConcentracoesDeAcidosEAlcalis: Classe HA; LibertacaoDeCadmio: 0; LibertacaoDeChumbo: 0
Type - IFC.REVIGRÉS-Dados de especificação-Wall Sweeps - VariacaoTonalidade: 2; NivelDeTrafego: 0; EPavimento: Não; ERevestimento: Sim; EExterno: Sim
Type - IFC.REVIGRÉS-Dados geométricos-Wall Sweeps - AlturaNominal: 8.5 mm; ComprimentoNominal: 8 mm; LarguraNominal: 60 mm
Type - IFC.REVIGRÉS-Dados de sustentabilidade-Wall Sweeps - PotencialPrivacaoDeAguaConsumoDeAguaPonderado: 4.5; EnergiaTermicaExportada: 0; ItemENovo: Sim; ItemEParcialmenteReciclado: 0.23; ItemEReciclado: Sim; VidaÚtilEsperada: 50; SubstanciasPerigosas: Não; PotencialDeEsgotamentoAbioticoDosRecursosFosseis: 203; PotencialDeEsgotamentoAbioticoDosRecursosNaoFosseisMineraisEMetais: 0.000701; PotencialDeAquecimentoGlobalBiogenico: -0.48; CombustiveisFosseisComPotencialDeAquecimentoGlobal: 13.9; PotencialDeAquecimentoGlobalUsoDoSoloEMudancaDeUsoDoSolo: 0.0246; PotencialDeEutrofizacaoFraccaoDeNutrientesQueAtingemOCompartimentoFinalDeAguaDoce: 0.000189; PotencialDeEutrofizacaoFraccaoDeNutrientesQueAtingemOCompartimentoFinalMarinho: 0.0122; EnergiaRecuperada: 0.00739; ConsumoDeAguaDoce: 0.113; UtilizacaoLiquidaDeAguaDoce: 0.113; ResiduosPerigososEliminados: 0.00221; ResiduosNaoPerigososEliminados: 1.83; MassaTotalDeResiduosRadioactivosEliminados: 0.000394; EnergiaElectricaExportada: 1.55; MateriaisParaRecuperacaoDeEnergia: 0.00739; MateriaisParaReciclagem: 0.0253; UnidadeEPD: 1 m²
Type - IFC.REVIGRÉS-Dados gerais-Wall Sweeps - Nome: REVIGRÉS-URBAN-RB-8X60-NAT-URBAN FOG; TipoProduto: Prensado a seco: grupo BIa UGL | Grés porcelânico técnico; NumeroDeRegistoDAP: EPD-REV-20240006-CCC1-EN; ReferenciaDAP: -; UrlDOP: -
Pset_ProvisionForVoid - Shape: Undefined; Width: 1000 mm; Depth: 1000 mm
IFC.REVIGRÉS-Dados do fabricante-Wall Sweeps - Type: Wall Sweep: REVIGRÉS-URBAN-RB-8X60-NAT-FOG
IFC.REVIGRÉS-Dados de desempenho-Wall Sweeps - Type: Wall Sweep: REVIGRÉS-URBAN-RB-8X60-NAT-FOG
IFC.REVIGRÉS-Dados de especificação-Wall Sweeps - Type: Wall Sweep: REVIGRÉS-URBAN-RB-8X60-NAT-FOG
IFC.REVIGRÉS-Dados geométricos-Wall Sweeps - Type: Wall Sweep: REVIGRÉS-URBAN-RB-8X60-NAT-FOG
IFC.REVIGRÉS-Dados de sustentabilidade-Wall Sweeps - Type: Wall Sweep: REVIGRÉS-URBAN-RB-8X60-NAT-FOG

# IfcBuildingElementProxy: Wall Sweep:REVIGRÉS-URBAN-RB-8X60-NAT-GRIS, Wall Sweep:REVIGRÉS-URBAN-RB-8X60-NAT-GRIS:182789
In: Level 1
Type - Pset_ManufacturerTypeInformation - Manufacturer: REVIGRÉS
Type - Pset_ProductRequirements - Category: Wall Sweeps
Type - IFC.REVIGRÉS-Dados do fabricante-Wall Sweeps - FabricanteURL: https://www.revigres.pt/; ReferenciaModelo: Urban; Acabamento: NAT; IdentificadorDoOperadorEconomico: 501840856; UrlFabricanteArtigo: https://www.revigres.pt/colecoes/urban; PaisOrigem: Portugal
Type - IFC.REVIGRÉS-Dados de desempenho-Wall Sweeps - Rectilinearidade: ± 0.3% máx. ± 1.5 mm; Ortogonalidade: ± 0.3% máx. ± 1.8 mm; PlanaridadeDaSuperficie: ± 0.3% máx. ± 1.8 mm; AbsorcaoDeAgua: < 0.05%; ModuloDeRuptura: > 45 N/mm²; ResistenciaAFlexao: > 2000 N; ResistenciaAAbrasaoProfunda: < 120 mm³; DilatacaoTermicaLinear: ≤ 8,0x10-6 °C-1; ResistenciaAoChoqueTermico: Resiste; DurabilidadeResistenciaAoGeloDegelo: Resiste; ResistenciaAoEscorregamentoDIN51130: R9; ResistenciaAoEscorregamentoDIN51097: A; ResistenciaAoEscorregamentoENV51097: A; ResistenciaAoDeslizamentoENV12633: Class 1; ResistenciaAoEscorregamentoANSIA1371: ≥0,42; ResistenciaAoEscorregamentoENV12633: Class 1; ResistenciaAsManchas: Class 5; ResistenciaABaixasConcentracoesDeAcidosEAlcalis: Classe LA; ResistenciaAAltasConcentracoesDeAcidosEAlcalis: Classe HA; LibertacaoDeCadmio: 0; LibertacaoDeChumbo: 0
Type - IFC.REVIGRÉS-Dados de especificação-Wall Sweeps - VariacaoTonalidade: 2; NivelDeTrafego: 0; EPavimento: Não; ERevestimento: Sim; EExterno: Sim
Type - IFC.REVIGRÉS-Dados geométricos-Wall Sweeps - AlturaNominal: 8.5 mm; ComprimentoNominal: 8 mm; LarguraNominal: 60 mm
Type - IFC.REVIGRÉS-Dados de sustentabilidade-Wall Sweeps - PotencialPrivacaoDeAguaConsumoDeAguaPonderado: 4.5; EnergiaTermicaExportada: 0; ItemENovo: Sim; ItemEParcialmenteReciclado: 0.23; ItemEReciclado: Sim; VidaÚtilEsperada: 50; SubstanciasPerigosas: Não; PotencialDeEsgotamentoAbioticoDosRecursosFosseis: 203; PotencialDeEsgotamentoAbioticoDosRecursosNaoFosseisMineraisEMetais: 0.000701; PotencialDeAquecimentoGlobalBiogenico: -0.48; CombustiveisFosseisComPotencialDeAquecimentoGlobal: 13.9; PotencialDeAquecimentoGlobalUsoDoSoloEMudancaDeUsoDoSolo: 0.0246; PotencialDeEutrofizacaoFraccaoDeNutrientesQueAtingemOCompartimentoFinalDeAguaDoce: 0.000189; PotencialDeEutrofizacaoFraccaoDeNutrientesQueAtingemOCompartimentoFinalMarinho: 0.0122; EnergiaRecuperada: 0.00739; ConsumoDeAguaDoce: 0.113; UtilizacaoLiquidaDeAguaDoce: 0.113; ResiduosPerigososEliminados: 0.00221; ResiduosNaoPerigososEliminados: 1.83; MassaTotalDeResiduosRadioactivosEliminados: 0.000394; EnergiaElectricaExportada: 1.55; MateriaisParaRecuperacaoDeEnergia: 0.00739; MateriaisParaReciclagem: 0.0253; UnidadeEPD: 1 m²
Type - IFC.REVIGRÉS-Dados gerais-Wall Sweeps - Nome: REVIGRÉS-URBAN-RB-8X60-NAT-URBAN GRIS; TipoProduto: Prensado a seco: grupo BIa UGL | Grés porcelânico técnico; NumeroDeRegistoDAP: EPD-REV-20240006-CCC1-EN; ReferenciaDAP: -; UrlDOP: -
Pset_ProvisionForVoid - Shape: Undefined; Width: 1000 mm; Depth: 1000 mm
IFC.REVIGRÉS-Dados do fabricante-Wall Sweeps - Type: Wall Sweep: REVIGRÉS-URBAN-RB-8X60-NAT-GRIS
IFC.REVIGRÉS-Dados de desempenho-Wall Sweeps - Type: Wall Sweep: REVIGRÉS-URBAN-RB-8X60-NAT-GRIS
IFC.REVIGRÉS-Dados de especificação-Wall Sweeps - Type: Wall Sweep: REVIGRÉS-URBAN-RB-8X60-NAT-GRIS
IFC.REVIGRÉS-Dados geométricos-Wall Sweeps - Type: Wall Sweep: REVIGRÉS-URBAN-RB-8X60-NAT-GRIS
IFC.REVIGRÉS-Dados de sustentabilidade-Wall Sweeps - Type: Wall Sweep: REVIGRÉS-URBAN-RB-8X60-NAT-GRIS

# IfcBuildingElementProxy: Wall Sweep:REVIGRÉS-URBAN-RB-8X60-NAT-OFFWHITE, Wall Sweep:REVIGRÉS-URBAN-RB-8X60-NAT-OFFWHITE:182799
In: Level 1
Type - Pset_ManufacturerTypeInformation - Manufacturer: REVIGRÉS
Type - Pset_ProductRequirements - Category: Wall Sweeps
Type - IFC.REVIGRÉS-Dados do fabricante-Wall Sweeps - FabricanteURL: https://www.revigres.pt/; ReferenciaModelo: Urban; Acabamento: NAT; IdentificadorDoOperadorEconomico: 501840856; UrlFabricanteArtigo: https://www.revigres.pt/colecoes/urban; PaisOrigem: Portugal
Type - IFC.REVIGRÉS-Dados de desempenho-Wall Sweeps - Rectilinearidade: ± 0.3% máx. ± 1.5 mm; Ortogonalidade: ± 0.3% máx. ± 1.8 mm; PlanaridadeDaSuperficie: ± 0.3% máx. ± 1.8 mm; AbsorcaoDeAgua: < 0.05%; ModuloDeRuptura: > 45 N/mm²; ResistenciaAFlexao: > 2000 N; ResistenciaAAbrasaoProfunda: < 120 mm³; DilatacaoTermicaLinear: ≤ 8,0x10-6 °C-1; ResistenciaAoChoqueTermico: Resiste; DurabilidadeResistenciaAoGeloDegelo: Resiste; ResistenciaAoEscorregamentoDIN51130: R9; ResistenciaAoEscorregamentoDIN51097: A; ResistenciaAoEscorregamentoENV51097: A; ResistenciaAoDeslizamentoENV12633: Class 1; ResistenciaAoEscorregamentoANSIA1371: ≥0,42; ResistenciaAoEscorregamentoENV12633: Class 1; ResistenciaAsManchas: Class 5; ResistenciaABaixasConcentracoesDeAcidosEAlcalis: Classe LA; ResistenciaAAltasConcentracoesDeAcidosEAlcalis: Classe HA; LibertacaoDeCadmio: 0; LibertacaoDeChumbo: 0
Type - IFC.REVIGRÉS-Dados de especificação-Wall Sweeps - VariacaoTonalidade: 2; NivelDeTrafego: 0; EPavimento: Não; ERevestimento: Sim; EExterno: Sim
Type - IFC.REVIGRÉS-Dados geométricos-Wall Sweeps - AlturaNominal: 8.5 mm; ComprimentoNominal: 8 mm; LarguraNominal: 60 mm
Type - IFC.REVIGRÉS-Dados de sustentabilidade-Wall Sweeps - PotencialPrivacaoDeAguaConsumoDeAguaPonderado: 4.5; EnergiaTermicaExportada: 0; ItemENovo: Sim; ItemEParcialmenteReciclado: 0.03; ItemEReciclado: Sim; VidaÚtilEsperada: 50; SubstanciasPerigosas: Não; PotencialDeEsgotamentoAbioticoDosRecursosFosseis: 203; PotencialDeEsgotamentoAbioticoDosRecursosNaoFosseisMineraisEMetais: 0.000701; PotencialDeAquecimentoGlobalBiogenico: -0.48; CombustiveisFosseisComPotencialDeAquecimentoGlobal: 13.9; PotencialDeAquecimentoGlobalUsoDoSoloEMudancaDeUsoDoSolo: 0.0246; PotencialDeEutrofizacaoFraccaoDeNutrientesQueAtingemOCompartimentoFinalDeAguaDoce: 0.000189; PotencialDeEutrofizacaoFraccaoDeNutrientesQueAtingemOCompartimentoFinalMarinho: 0.0122; EnergiaRecuperada: 0.00739; ConsumoDeAguaDoce: 0.113; UtilizacaoLiquidaDeAguaDoce: 0.113; ResiduosPerigososEliminados: 0.00221; ResiduosNaoPerigososEliminados: 1.83; MassaTotalDeResiduosRadioactivosEliminados: 0.000394; EnergiaElectricaExportada: 1.55; MateriaisParaRecuperacaoDeEnergia: 0.00739; MateriaisParaReciclagem: 0.0253; UnidadeEPD: 1 m²
Type - IFC.REVIGRÉS-Dados gerais-Wall Sweeps - Nome: REVIGRÉS-URBAN-RB-8X60-NAT-URBAN OFFWHITE; TipoProduto: Prensado a seco: grupo BIa UGL | Grés porcelânico técnico; NumeroDeRegistoDAP: EPD-REV-20240006-CCC1-EN; ReferenciaDAP: -; UrlDOP: -
Pset_ProvisionForVoid - Shape: Undefined; Width: 1000 mm; Depth: 1000 mm
IFC.REVIGRÉS-Dados do fabricante-Wall Sweeps - Type: Wall Sweep: REVIGRÉS-URBAN-RB-8X60-NAT-OFFWHITE
IFC.REVIGRÉS-Dados de desempenho-Wall Sweeps - Type: Wall Sweep: REVIGRÉS-URBAN-RB-8X60-NAT-OFFWHITE
IFC.REVIGRÉS-Dados de especificação-Wall Sweeps - Type: Wall Sweep: REVIGRÉS-URBAN-RB-8X60-NAT-OFFWHITE
IFC.REVIGRÉS-Dados geométricos-Wall Sweeps - Type: Wall Sweep: REVIGRÉS-URBAN-RB-8X60-NAT-OFFWHITE
IFC.REVIGRÉS-Dados de sustentabilidade-Wall Sweeps - Type: Wall Sweep: REVIGRÉS-URBAN-RB-8X60-NAT-OFFWHITE

# IfcBuildingElementProxy: Wall Sweep:REVIGRÉS-URBAN-RB-8X60-RECT-ANTRACITE, Wall Sweep:REVIGRÉS-URBAN-RB-8X60-RECT-ANTRACITE:182743
In: Level 1
Type - Pset_ManufacturerTypeInformation - Manufacturer: REVIGRÉS
Type - Pset_ProductRequirements - Category: Wall Sweeps
Type - IFC.REVIGRÉS-Dados do fabricante-Wall Sweeps - FabricanteURL: https://www.revigres.pt/; ReferenciaModelo: Urban; Acabamento: RECT; IdentificadorDoOperadorEconomico: 501840856; UrlFabricanteArtigo: https://www.revigres.pt/colecoes/urban; PaisOrigem: Portugal
Type - IFC.REVIGRÉS-Dados de desempenho-Wall Sweeps - Rectilinearidade: ± 0.2% máx.± 0.8 mm; Ortogonalidade: ± 0.2% máx.± 1.5 mm; PlanaridadeDaSuperficie: ± 0.3% máx. ± 1.8 mm; AbsorcaoDeAgua: < 0.05%; ModuloDeRuptura: > 45 N/mm²; ResistenciaAFlexao: > 1500 N; ResistenciaAAbrasaoProfunda: < 120 mm³; DilatacaoTermicaLinear: ≤ 8,0x10-6 °C-1; ResistenciaAoChoqueTermico: Resiste; DurabilidadeResistenciaAoGeloDegelo: Resiste; ResistenciaAoEscorregamentoDIN51130: R9; ResistenciaAoEscorregamentoDIN51097: A; ResistenciaAoEscorregamentoENV51097: A; ResistenciaAoDeslizamentoENV12633: Class 1; ResistenciaAoEscorregamentoANSIA1371: ≥0,42; ResistenciaAoEscorregamentoENV12633: Class 1; ResistenciaAsManchas: Class 5; ResistenciaABaixasConcentracoesDeAcidosEAlcalis: Classe LA; ResistenciaAAltasConcentracoesDeAcidosEAlcalis: Classe HA; LibertacaoDeCadmio: 0; LibertacaoDeChumbo: 0
Type - IFC.REVIGRÉS-Dados de especificação-Wall Sweeps - VariacaoTonalidade: 2; NivelDeTrafego: 0; EPavimento: Não; ERevestimento: Sim; EExterno: Sim
Type - IFC.REVIGRÉS-Dados geométricos-Wall Sweeps - AlturaNominal: 8.5 mm; ComprimentoNominal: 8 mm; LarguraNominal: 592 mm
Type - IFC.REVIGRÉS-Dados de sustentabilidade-Wall Sweeps - PotencialPrivacaoDeAguaConsumoDeAguaPonderado: 4.5; EnergiaTermicaExportada: 0; ItemENovo: Sim; ItemEParcialmenteReciclado: 0.29; ItemEReciclado: Sim; VidaÚtilEsperada: 50; SubstanciasPerigosas: Não; PotencialDeEsgotamentoAbioticoDosRecursosFosseis: 203; PotencialDeEsgotamentoAbioticoDosRecursosNaoFosseisMineraisEMetais: 0.000701; PotencialDeAquecimentoGlobalBiogenico: -0.48; CombustiveisFosseisComPotencialDeAquecimentoGlobal: 13.9; PotencialDeAquecimentoGlobalUsoDoSoloEMudancaDeUsoDoSolo: 0.0246; PotencialDeEutrofizacaoFraccaoDeNutrientesQueAtingemOCompartimentoFinalDeAguaDoce: 0.000189; PotencialDeEutrofizacaoFraccaoDeNutrientesQueAtingemOCompartimentoFinalMarinho: 0.0122; EnergiaRecuperada: 0.00739; ConsumoDeAguaDoce: 0.113; UtilizacaoLiquidaDeAguaDoce: 0.113; ResiduosPerigososEliminados: 0.00221; ResiduosNaoPerigososEliminados: 1.83; MassaTotalDeResiduosRadioactivosEliminados: 0.000394; EnergiaElectricaExportada: 1.55; MateriaisParaRecuperacaoDeEnergia: 0.00739; MateriaisParaReciclagem: 0.0253; UnidadeEPD: 1 m²
Type - IFC.REVIGRÉS-Dados gerais-Wall Sweeps - Nome: REVIGRÉS-URBAN-RB-8X60-RECT-URBAN ANTRACITE; TipoProduto: Prensado a seco: grupo BIa UGL | Grés porcelânico técnico; NumeroDeRegistoDAP: EPD-REV-20240006-CCC1-EN; ReferenciaDAP: -; UrlDOP: -
Pset_ProvisionForVoid - Shape: Undefined; Width: 1000 mm; Depth: 1000 mm
IFC.REVIGRÉS-Dados do fabricante-Wall Sweeps - Type: Wall Sweep: REVIGRÉS-URBAN-RB-8X60-RECT-ANTRACITE
IFC.REVIGRÉS-Dados de desempenho-Wall Sweeps - Type: Wall Sweep: REVIGRÉS-URBAN-RB-8X60-RECT-ANTRACITE
IFC.REVIGRÉS-Dados de especificação-Wall Sweeps - Type: Wall Sweep: REVIGRÉS-URBAN-RB-8X60-RECT-ANTRACITE
IFC.REVIGRÉS-Dados geométricos-Wall Sweeps - Type: Wall Sweep: REVIGRÉS-URBAN-RB-8X60-RECT-ANTRACITE
IFC.REVIGRÉS-Dados de sustentabilidade-Wall Sweeps - Type: Wall Sweep: REVIGRÉS-URBAN-RB-8X60-RECT-ANTRACITE

# IfcBuildingElementProxy: Wall Sweep:REVIGRÉS-URBAN-RB-8X60-RECT-BONE, Wall Sweep:REVIGRÉS-URBAN-RB-8X60-RECT-BONE:182753
In: Level 1
Type - Pset_ManufacturerTypeInformation - Manufacturer: REVIGRÉS
Type - Pset_ProductRequirements - Category: Wall Sweeps
Type - IFC.REVIGRÉS-Dados do fabricante-Wall Sweeps - FabricanteURL: https://www.revigres.pt/; ReferenciaModelo: Urban; Acabamento: RECT; IdentificadorDoOperadorEconomico: 501840856; UrlFabricanteArtigo: https://www.revigres.pt/colecoes/urban; PaisOrigem: Portugal
Type - IFC.REVIGRÉS-Dados de desempenho-Wall Sweeps - Rectilinearidade: ± 0.2% máx.± 0.8 mm; Ortogonalidade: ± 0.2% máx.± 1.5 mm; PlanaridadeDaSuperficie: ± 0.3% máx. ± 1.8 mm; AbsorcaoDeAgua: < 0.05%; ModuloDeRuptura: > 45 N/mm²; ResistenciaAFlexao: > 1500 N; ResistenciaAAbrasaoProfunda: < 120 mm³; DilatacaoTermicaLinear: ≤ 8,0x10-6 °C-1; ResistenciaAoChoqueTermico: Resiste; DurabilidadeResistenciaAoGeloDegelo: Resiste; ResistenciaAoEscorregamentoDIN51130: R9; ResistenciaAoEscorregamentoDIN51097: A; ResistenciaAoEscorregamentoENV51097: A; ResistenciaAoDeslizamentoENV12633: Class 1; ResistenciaAoEscorregamentoANSIA1371: ≥0,42; ResistenciaAoEscorregamentoENV12633: Class 1; ResistenciaAsManchas: Class 5; ResistenciaABaixasConcentracoesDeAcidosEAlcalis: Classe LA; ResistenciaAAltasConcentracoesDeAcidosEAlcalis: Classe HA; LibertacaoDeCadmio: 0; LibertacaoDeChumbo: 0
Type - IFC.REVIGRÉS-Dados de especificação-Wall Sweeps - VariacaoTonalidade: 2; NivelDeTrafego: 0; EPavimento: Não; ERevestimento: Sim; EExterno: Sim
Type - IFC.REVIGRÉS-Dados geométricos-Wall Sweeps - AlturaNominal: 8.5 mm; ComprimentoNominal: 8 mm; LarguraNominal: 592 mm
Type - IFC.REVIGRÉS-Dados de sustentabilidade-Wall Sweeps - PotencialPrivacaoDeAguaConsumoDeAguaPonderado: 4.5; EnergiaTermicaExportada: 0; ItemENovo: Sim; ItemEParcialmenteReciclado: 0.03; ItemEReciclado: Sim; VidaÚtilEsperada: 50; SubstanciasPerigosas: Não; PotencialDeEsgotamentoAbioticoDosRecursosFosseis: 203; PotencialDeEsgotamentoAbioticoDosRecursosNaoFosseisMineraisEMetais: 0.000701; PotencialDeAquecimentoGlobalBiogenico: -0.48; CombustiveisFosseisComPotencialDeAquecimentoGlobal: 13.9; PotencialDeAquecimentoGlobalUsoDoSoloEMudancaDeUsoDoSolo: 0.0246; PotencialDeEutrofizacaoFraccaoDeNutrientesQueAtingemOCompartimentoFinalDeAguaDoce: 0.000189; PotencialDeEutrofizacaoFraccaoDeNutrientesQueAtingemOCompartimentoFinalMarinho: 0.0122; EnergiaRecuperada: 0.00739; ConsumoDeAguaDoce: 0.113; UtilizacaoLiquidaDeAguaDoce: 0.113; ResiduosPerigososEliminados: 0.00221; ResiduosNaoPerigososEliminados: 1.83; MassaTotalDeResiduosRadioactivosEliminados: 0.000394; EnergiaElectricaExportada: 1.55; MateriaisParaRecuperacaoDeEnergia: 0.00739; MateriaisParaReciclagem: 0.0253; UnidadeEPD: 1 m²
Type - IFC.REVIGRÉS-Dados gerais-Wall Sweeps - Nome: REVIGRÉS-URBAN-RB-8X60-RECT-URBAN BONE; TipoProduto: Prensado a seco: grupo BIa UGL | Grés porcelânico técnico; NumeroDeRegistoDAP: EPD-REV-20240006-CCC1-EN; ReferenciaDAP: -; UrlDOP: -
Pset_ProvisionForVoid - Shape: Undefined; Width: 1000 mm; Depth: 1000 mm
IFC.REVIGRÉS-Dados do fabricante-Wall Sweeps - Type: Wall Sweep: REVIGRÉS-URBAN-RB-8X60-RECT-BONE
IFC.REVIGRÉS-Dados de desempenho-Wall Sweeps - Type: Wall Sweep: REVIGRÉS-URBAN-RB-8X60-RECT-BONE
IFC.REVIGRÉS-Dados de especificação-Wall Sweeps - Type: Wall Sweep: REVIGRÉS-URBAN-RB-8X60-RECT-BONE
IFC.REVIGRÉS-Dados geométricos-Wall Sweeps - Type: Wall Sweep: REVIGRÉS-URBAN-RB-8X60-RECT-BONE
IFC.REVIGRÉS-Dados de sustentabilidade-Wall Sweeps - Type: Wall Sweep: REVIGRÉS-URBAN-RB-8X60-RECT-BONE

# IfcBuildingElementProxy: Wall Sweep:REVIGRÉS-URBAN-RB-8X60-RECT-CRAFT, Wall Sweep:REVIGRÉS-URBAN-RB-8X60-RECT-CRAFT:182763
In: Level 1
Type - Pset_ManufacturerTypeInformation - Manufacturer: REVIGRÉS
Type - Pset_ProductRequirements - Category: Wall Sweeps
Type - IFC.REVIGRÉS-Dados do fabricante-Wall Sweeps - FabricanteURL: https://www.revigres.pt/; ReferenciaModelo: Urban; Acabamento: RECT; IdentificadorDoOperadorEconomico: 501840856; UrlFabricanteArtigo: https://www.revigres.pt/colecoes/urban; PaisOrigem: Portugal
Type - IFC.REVIGRÉS-Dados de desempenho-Wall Sweeps - Rectilinearidade: ± 0.2% máx.± 0.8 mm; Ortogonalidade: ± 0.2% máx.± 1.5 mm; PlanaridadeDaSuperficie: ± 0.3% máx. ± 1.8 mm; AbsorcaoDeAgua: < 0.05%; ModuloDeRuptura: > 45 N/mm²; ResistenciaAFlexao: > 1500 N; ResistenciaAAbrasaoProfunda: < 120 mm³; DilatacaoTermicaLinear: ≤ 8,0x10-6 °C-1; ResistenciaAoChoqueTermico: Resiste; DurabilidadeResistenciaAoGeloDegelo: Resiste; ResistenciaAoEscorregamentoDIN51130: R9; ResistenciaAoEscorregamentoDIN51097: A; ResistenciaAoEscorregamentoENV51097: A; ResistenciaAoDeslizamentoENV12633: Class 1; ResistenciaAoEscorregamentoANSIA1371: ≥0,42; ResistenciaAoEscorregamentoENV12633: Class 1; ResistenciaAsManchas: Class 5; ResistenciaABaixasConcentracoesDeAcidosEAlcalis: Classe LA; ResistenciaAAltasConcentracoesDeAcidosEAlcalis: Classe HA; LibertacaoDeCadmio: 0; LibertacaoDeChumbo: 0
Type - IFC.REVIGRÉS-Dados de especificação-Wall Sweeps - VariacaoTonalidade: 2; NivelDeTrafego: 0; EPavimento: Não; ERevestimento: Sim; EExterno: Sim
Type - IFC.REVIGRÉS-Dados geométricos-Wall Sweeps - AlturaNominal: 8.5 mm; ComprimentoNominal: 8 mm; LarguraNominal: 592 mm
Type - IFC.REVIGRÉS-Dados de sustentabilidade-Wall Sweeps - PotencialPrivacaoDeAguaConsumoDeAguaPonderado: 4.5; EnergiaTermicaExportada: 0; ItemENovo: Sim; ItemEParcialmenteReciclado: 0.19; ItemEReciclado: Sim; VidaÚtilEsperada: 50; SubstanciasPerigosas: Não; PotencialDeEsgotamentoAbioticoDosRecursosFosseis: 203; PotencialDeEsgotamentoAbioticoDosRecursosNaoFosseisMineraisEMetais: 0.000701; PotencialDeAquecimentoGlobalBiogenico: -0.48; CombustiveisFosseisComPotencialDeAquecimentoGlobal: 13.9; PotencialDeAquecimentoGlobalUsoDoSoloEMudancaDeUsoDoSolo: 0.0246; PotencialDeEutrofizacaoFraccaoDeNutrientesQueAtingemOCompartimentoFinalDeAguaDoce: 0.000189; PotencialDeEutrofizacaoFraccaoDeNutrientesQueAtingemOCompartimentoFinalMarinho: 0.0122; EnergiaRecuperada: 0.00739; ConsumoDeAguaDoce: 0.113; UtilizacaoLiquidaDeAguaDoce: 0.113; ResiduosPerigososEliminados: 0.00221; ResiduosNaoPerigososEliminados: 1.83; MassaTotalDeResiduosRadioactivosEliminados: 0.000394; EnergiaElectricaExportada: 1.55; MateriaisParaRecuperacaoDeEnergia: 0.00739; MateriaisParaReciclagem: 0.0253; UnidadeEPD: 1 m²
Type - IFC.REVIGRÉS-Dados gerais-Wall Sweeps - Nome: REVIGRÉS-URBAN-RB-8X60-RECT-URBAN CRAFT; TipoProduto: Prensado a seco: grupo BIa UGL | Grés porcelânico técnico; NumeroDeRegistoDAP: EPD-REV-20240006-CCC1-EN; ReferenciaDAP: -; UrlDOP: -
Pset_ProvisionForVoid - Shape: Undefined; Width: 1000 mm; Depth: 1000 mm
IFC.REVIGRÉS-Dados do fabricante-Wall Sweeps - Type: Wall Sweep: REVIGRÉS-URBAN-RB-8X60-RECT-CRAFT
IFC.REVIGRÉS-Dados de desempenho-Wall Sweeps - Type: Wall Sweep: REVIGRÉS-URBAN-RB-8X60-RECT-CRAFT
IFC.REVIGRÉS-Dados de especificação-Wall Sweeps - Type: Wall Sweep: REVIGRÉS-URBAN-RB-8X60-RECT-CRAFT
IFC.REVIGRÉS-Dados geométricos-Wall Sweeps - Type: Wall Sweep: REVIGRÉS-URBAN-RB-8X60-RECT-CRAFT
IFC.REVIGRÉS-Dados de sustentabilidade-Wall Sweeps - Type: Wall Sweep: REVIGRÉS-URBAN-RB-8X60-RECT-CRAFT

# IfcBuildingElementProxy: Wall Sweep:REVIGRÉS-URBAN-RB-8X60-RECT-FOG, Wall Sweep:REVIGRÉS-URBAN-RB-8X60-RECT-FOG:182773
In: Level 1
Type - Pset_ManufacturerTypeInformation - Manufacturer: REVIGRÉS
Type - Pset_ProductRequirements - Category: Wall Sweeps
Type - IFC.REVIGRÉS-Dados do fabricante-Wall Sweeps - FabricanteURL: https://www.revigres.pt/; ReferenciaModelo: Urban; Acabamento: RECT; IdentificadorDoOperadorEconomico: 501840856; UrlFabricanteArtigo: https://www.revigres.pt/colecoes/urban; PaisOrigem: Portugal
Type - IFC.REVIGRÉS-Dados de desempenho-Wall Sweeps - Rectilinearidade: ± 0.2% máx.± 0.8 mm; Ortogonalidade: ± 0.2% máx.± 1.5 mm; PlanaridadeDaSuperficie: ± 0.3% máx. ± 1.8 mm; AbsorcaoDeAgua: < 0.05%; ModuloDeRuptura: > 45 N/mm²; ResistenciaAFlexao: > 1500 N; ResistenciaAAbrasaoProfunda: < 120 mm³; DilatacaoTermicaLinear: ≤ 8,0x10-6 °C-1; ResistenciaAoChoqueTermico: Resiste; DurabilidadeResistenciaAoGeloDegelo: Resiste; ResistenciaAoEscorregamentoDIN51130: R9; ResistenciaAoEscorregamentoDIN51097: A; ResistenciaAoEscorregamentoENV51097: A; ResistenciaAoDeslizamentoENV12633: Class 1; ResistenciaAoEscorregamentoANSIA1371: ≥0,42; ResistenciaAoEscorregamentoENV12633: Class 1; ResistenciaAsManchas: Class 5; ResistenciaABaixasConcentracoesDeAcidosEAlcalis: Classe LA; ResistenciaAAltasConcentracoesDeAcidosEAlcalis: Classe HA; LibertacaoDeCadmio: 0; LibertacaoDeChumbo: 0
Type - IFC.REVIGRÉS-Dados de especificação-Wall Sweeps - VariacaoTonalidade: 2; NivelDeTrafego: 0; EPavimento: Não; ERevestimento: Sim; EExterno: Sim
Type - IFC.REVIGRÉS-Dados geométricos-Wall Sweeps - AlturaNominal: 8.5 mm; ComprimentoNominal: 8 mm; LarguraNominal: 592 mm
Type - IFC.REVIGRÉS-Dados de sustentabilidade-Wall Sweeps - PotencialPrivacaoDeAguaConsumoDeAguaPonderado: 4.5; EnergiaTermicaExportada: 0; ItemENovo: Sim; ItemEParcialmenteReciclado: 0.23; ItemEReciclado: Sim; VidaÚtilEsperada: 50; SubstanciasPerigosas: Não; PotencialDeEsgotamentoAbioticoDosRecursosFosseis: 203; PotencialDeEsgotamentoAbioticoDosRecursosNaoFosseisMineraisEMetais: 0.000701; PotencialDeAquecimentoGlobalBiogenico: -0.48; CombustiveisFosseisComPotencialDeAquecimentoGlobal: 13.9; PotencialDeAquecimentoGlobalUsoDoSoloEMudancaDeUsoDoSolo: 0.0246; PotencialDeEutrofizacaoFraccaoDeNutrientesQueAtingemOCompartimentoFinalDeAguaDoce: 0.000189; PotencialDeEutrofizacaoFraccaoDeNutrientesQueAtingemOCompartimentoFinalMarinho: 0.0122; EnergiaRecuperada: 0.00739; ConsumoDeAguaDoce: 0.113; UtilizacaoLiquidaDeAguaDoce: 0.113; ResiduosPerigososEliminados: 0.00221; ResiduosNaoPerigososEliminados: 1.83; MassaTotalDeResiduosRadioactivosEliminados: 0.000394; EnergiaElectricaExportada: 1.55; MateriaisParaRecuperacaoDeEnergia: 0.00739; MateriaisParaReciclagem: 0.0253; UnidadeEPD: 1 m²
Type - IFC.REVIGRÉS-Dados gerais-Wall Sweeps - Nome: REVIGRÉS-URBAN-RB-8X60-RECT-URBAN FOG; TipoProduto: Prensado a seco: grupo BIa UGL | Grés porcelânico técnico; NumeroDeRegistoDAP: EPD-REV-20240006-CCC1-EN; ReferenciaDAP: -; UrlDOP: -
Pset_ProvisionForVoid - Shape: Undefined; Width: 1000 mm; Depth: 1000 mm
IFC.REVIGRÉS-Dados do fabricante-Wall Sweeps - Type: Wall Sweep: REVIGRÉS-URBAN-RB-8X60-RECT-FOG
IFC.REVIGRÉS-Dados de desempenho-Wall Sweeps - Type: Wall Sweep: REVIGRÉS-URBAN-RB-8X60-RECT-FOG
IFC.REVIGRÉS-Dados de especificação-Wall Sweeps - Type: Wall Sweep: REVIGRÉS-URBAN-RB-8X60-RECT-FOG
IFC.REVIGRÉS-Dados geométricos-Wall Sweeps - Type: Wall Sweep: REVIGRÉS-URBAN-RB-8X60-RECT-FOG
IFC.REVIGRÉS-Dados de sustentabilidade-Wall Sweeps - Type: Wall Sweep: REVIGRÉS-URBAN-RB-8X60-RECT-FOG

# IfcBuildingElementProxy: Wall Sweep:REVIGRÉS-URBAN-RB-8X60-RECT-GRIS, Wall Sweep:REVIGRÉS-URBAN-RB-8X60-RECT-GRIS:182783
In: Level 1
Type - Pset_ManufacturerTypeInformation - Manufacturer: REVIGRÉS
Type - Pset_ProductRequirements - Category: Wall Sweeps
Type - IFC.REVIGRÉS-Dados do fabricante-Wall Sweeps - FabricanteURL: https://www.revigres.pt/; ReferenciaModelo: Urban; Acabamento: RECT; IdentificadorDoOperadorEconomico: 501840856; UrlFabricanteArtigo: https://www.revigres.pt/colecoes/urban; PaisOrigem: Portugal
Type - IFC.REVIGRÉS-Dados de desempenho-Wall Sweeps - Rectilinearidade: ± 0.2% máx.± 0.8 mm; Ortogonalidade: ± 0.2% máx.± 1.5 mm; PlanaridadeDaSuperficie: ± 0.3% máx. ± 1.8 mm; AbsorcaoDeAgua: < 0.05%; ModuloDeRuptura: > 45 N/mm²; ResistenciaAFlexao: > 1500 N; ResistenciaAAbrasaoProfunda: < 120 mm³; DilatacaoTermicaLinear: ≤ 8,0x10-6 °C-1; ResistenciaAoChoqueTermico: Resiste; DurabilidadeResistenciaAoGeloDegelo: Resiste; ResistenciaAoEscorregamentoDIN51130: R9; ResistenciaAoEscorregamentoDIN51097: A; ResistenciaAoEscorregamentoENV51097: A; ResistenciaAoDeslizamentoENV12633: Class 1; ResistenciaAoEscorregamentoANSIA1371: ≥0,42; ResistenciaAoEscorregamentoENV12633: Class 1; ResistenciaAsManchas: Class 5; ResistenciaABaixasConcentracoesDeAcidosEAlcalis: Classe LA; ResistenciaAAltasConcentracoesDeAcidosEAlcalis: Classe HA; LibertacaoDeCadmio: 0; LibertacaoDeChumbo: 0
Type - IFC.REVIGRÉS-Dados de especificação-Wall Sweeps - VariacaoTonalidade: 2; NivelDeTrafego: 0; EPavimento: Não; ERevestimento: Sim; EExterno: Sim
Type - IFC.REVIGRÉS-Dados geométricos-Wall Sweeps - AlturaNominal: 8.5 mm; ComprimentoNominal: 8 mm; LarguraNominal: 592 mm
Type - IFC.REVIGRÉS-Dados de sustentabilidade-Wall Sweeps - PotencialPrivacaoDeAguaConsumoDeAguaPonderado: 4.5; EnergiaTermicaExportada: 0; ItemENovo: Sim; ItemEParcialmenteReciclado: 0.23; ItemEReciclado: Sim; VidaÚtilEsperada: 50; SubstanciasPerigosas: Não; PotencialDeEsgotamentoAbioticoDosRecursosFosseis: 203; PotencialDeEsgotamentoAbioticoDosRecursosNaoFosseisMineraisEMetais: 0.000701; PotencialDeAquecimentoGlobalBiogenico: -0.48; CombustiveisFosseisComPotencialDeAquecimentoGlobal: 13.9; PotencialDeAquecimentoGlobalUsoDoSoloEMudancaDeUsoDoSolo: 0.0246; PotencialDeEutrofizacaoFraccaoDeNutrientesQueAtingemOCompartimentoFinalDeAguaDoce: 0.000189; PotencialDeEutrofizacaoFraccaoDeNutrientesQueAtingemOCompartimentoFinalMarinho: 0.0122; EnergiaRecuperada: 0.00739; ConsumoDeAguaDoce: 0.113; UtilizacaoLiquidaDeAguaDoce: 0.113; ResiduosPerigososEliminados: 0.00221; ResiduosNaoPerigososEliminados: 1.83; MassaTotalDeResiduosRadioactivosEliminados: 0.000394; EnergiaElectricaExportada: 1.55; MateriaisParaRecuperacaoDeEnergia: 0.00739; MateriaisParaReciclagem: 0.0253; UnidadeEPD: 1 m²
Type - IFC.REVIGRÉS-Dados gerais-Wall Sweeps - Nome: REVIGRÉS-URBAN-RB-8X60-RECT-URBAN GRIS; TipoProduto: Prensado a seco: grupo BIa UGL | Grés porcelânico técnico; NumeroDeRegistoDAP: EPD-REV-20240006-CCC1-EN; ReferenciaDAP: -; UrlDOP: -
Pset_ProvisionForVoid - Shape: Undefined; Width: 1000 mm; Depth: 1000 mm
IFC.REVIGRÉS-Dados do fabricante-Wall Sweeps - Type: Wall Sweep: REVIGRÉS-URBAN-RB-8X60-RECT-GRIS
IFC.REVIGRÉS-Dados de desempenho-Wall Sweeps - Type: Wall Sweep: REVIGRÉS-URBAN-RB-8X60-RECT-GRIS
IFC.REVIGRÉS-Dados de especificação-Wall Sweeps - Type: Wall Sweep: REVIGRÉS-URBAN-RB-8X60-RECT-GRIS
IFC.REVIGRÉS-Dados geométricos-Wall Sweeps - Type: Wall Sweep: REVIGRÉS-URBAN-RB-8X60-RECT-GRIS
IFC.REVIGRÉS-Dados de sustentabilidade-Wall Sweeps - Type: Wall Sweep: REVIGRÉS-URBAN-RB-8X60-RECT-GRIS

# IfcBuildingElementProxy: Wall Sweep:REVIGRÉS-URBAN-RB-8X60-RECT-OFFWHITE, Wall Sweep:REVIGRÉS-URBAN-RB-8X60-RECT-OFFWHITE:182793
In: Level 1
Type - Pset_ManufacturerTypeInformation - Manufacturer: REVIGRÉS
Type - Pset_ProductRequirements - Category: Wall Sweeps
Type - IFC.REVIGRÉS-Dados do fabricante-Wall Sweeps - FabricanteURL: https://www.revigres.pt/; ReferenciaModelo: Urban; Acabamento: RECT; IdentificadorDoOperadorEconomico: 501840856; UrlFabricanteArtigo: https://www.revigres.pt/colecoes/urban; PaisOrigem: Portugal
Type - IFC.REVIGRÉS-Dados de desempenho-Wall Sweeps - Rectilinearidade: ± 0.2% máx.± 0.8 mm; Ortogonalidade: ± 0.2% máx.± 1.5 mm; PlanaridadeDaSuperficie: ± 0.3% máx. ± 1.8 mm; AbsorcaoDeAgua: < 0.05%; ModuloDeRuptura: > 45 N/mm²; ResistenciaAFlexao: > 1500 N; ResistenciaAAbrasaoProfunda: < 120 mm³; DilatacaoTermicaLinear: ≤ 8,0x10-6 °C-1; ResistenciaAoChoqueTermico: Resiste; DurabilidadeResistenciaAoGeloDegelo: Resiste; ResistenciaAoEscorregamentoDIN51130: R9; ResistenciaAoEscorregamentoDIN51097: A; ResistenciaAoEscorregamentoENV51097: A; ResistenciaAoDeslizamentoENV12633: Class 1; ResistenciaAoEscorregamentoANSIA1371: ≥0,42; ResistenciaAoEscorregamentoENV12633: Class 1; ResistenciaAsManchas: Class 5; ResistenciaABaixasConcentracoesDeAcidosEAlcalis: Classe LA; ResistenciaAAltasConcentracoesDeAcidosEAlcalis: Classe HA; LibertacaoDeCadmio: 0; LibertacaoDeChumbo: 0
Type - IFC.REVIGRÉS-Dados de especificação-Wall Sweeps - VariacaoTonalidade: 2; NivelDeTrafego: 0; EPavimento: Não; ERevestimento: Sim; EExterno: Sim
Type - IFC.REVIGRÉS-Dados geométricos-Wall Sweeps - AlturaNominal: 8.5 mm; ComprimentoNominal: 8 mm; LarguraNominal: 592 mm
Type - IFC.REVIGRÉS-Dados de sustentabilidade-Wall Sweeps - PotencialPrivacaoDeAguaConsumoDeAguaPonderado: 4.5; EnergiaTermicaExportada: 0; ItemENovo: Sim; ItemEParcialmenteReciclado: 0.03; ItemEReciclado: Sim; VidaÚtilEsperada: 50; SubstanciasPerigosas: Não; PotencialDeEsgotamentoAbioticoDosRecursosFosseis: 203; PotencialDeEsgotamentoAbioticoDosRecursosNaoFosseisMineraisEMetais: 0.000701; PotencialDeAquecimentoGlobalBiogenico: -0.48; CombustiveisFosseisComPotencialDeAquecimentoGlobal: 13.9; PotencialDeAquecimentoGlobalUsoDoSoloEMudancaDeUsoDoSolo: 0.0246; PotencialDeEutrofizacaoFraccaoDeNutrientesQueAtingemOCompartimentoFinalDeAguaDoce: 0.000189; PotencialDeEutrofizacaoFraccaoDeNutrientesQueAtingemOCompartimentoFinalMarinho: 0.0122; EnergiaRecuperada: 0.00739; ConsumoDeAguaDoce: 0.113; UtilizacaoLiquidaDeAguaDoce: 0.113; ResiduosPerigososEliminados: 0.00221; ResiduosNaoPerigososEliminados: 1.83; MassaTotalDeResiduosRadioactivosEliminados: 0.000394; EnergiaElectricaExportada: 1.55; MateriaisParaRecuperacaoDeEnergia: 0.00739; MateriaisParaReciclagem: 0.0253; UnidadeEPD: 1 m²
Type - IFC.REVIGRÉS-Dados gerais-Wall Sweeps - Nome: REVIGRÉS-URBAN-RB-8X60-RECT-URBAN OFFWHITE; TipoProduto: Prensado a seco: grupo BIa UGL | Grés porcelânico técnico; NumeroDeRegistoDAP: EPD-REV-20240006-CCC1-EN; ReferenciaDAP: -; UrlDOP: -
Pset_ProvisionForVoid - Shape: Undefined; Width: 1000 mm; Depth: 1000 mm
IFC.REVIGRÉS-Dados do fabricante-Wall Sweeps - Type: Wall Sweep: REVIGRÉS-URBAN-RB-8X60-RECT-OFFWHITE
IFC.REVIGRÉS-Dados de desempenho-Wall Sweeps - Type: Wall Sweep: REVIGRÉS-URBAN-RB-8X60-RECT-OFFWHITE
IFC.REVIGRÉS-Dados de especificação-Wall Sweeps - Type: Wall Sweep: REVIGRÉS-URBAN-RB-8X60-RECT-OFFWHITE
IFC.REVIGRÉS-Dados geométricos-Wall Sweeps - Type: Wall Sweep: REVIGRÉS-URBAN-RB-8X60-RECT-OFFWHITE
IFC.REVIGRÉS-Dados de sustentabilidade-Wall Sweeps - Type: Wall Sweep: REVIGRÉS-URBAN-RB-8X60-RECT-OFFWHITE

# IfcBuildingElementProxy: Wall Sweep:REVIGRÉS-URBAN-RB-8X90-RECT-ANTRACITE, Wall Sweep:REVIGRÉS-URBAN-RB-8X90-RECT-ANTRACITE:182744
In: Level 1
Type - Pset_ManufacturerTypeInformation - Manufacturer: REVIGRÉS
Type - Pset_ProductRequirements - Category: Wall Sweeps
Type - IFC.REVIGRÉS-Dados do fabricante-Wall Sweeps - FabricanteURL: https://www.revigres.pt/; ReferenciaModelo: Urban; Acabamento: NAT; IdentificadorDoOperadorEconomico: 501840856; UrlFabricanteArtigo: https://www.revigres.pt/colecoes/urban; PaisOrigem: Portugal
Type - IFC.REVIGRÉS-Dados de desempenho-Wall Sweeps - Rectilinearidade: ± 0.3% máx. ± 1.5 mm; Ortogonalidade: ± 0.3% máx. ± 1.8 mm; PlanaridadeDaSuperficie: ± 0.3% máx. ± 1.8 mm; AbsorcaoDeAgua: < 0.05%; ModuloDeRuptura: > 45 N/mm²; ResistenciaAFlexao: > 2000 N; ResistenciaAAbrasaoProfunda: < 120 mm³; DilatacaoTermicaLinear: ≤ 8,0x10-6 °C-1; ResistenciaAoChoqueTermico: Resiste; DurabilidadeResistenciaAoGeloDegelo: Resiste; ResistenciaAoEscorregamentoDIN51130: R9; ResistenciaAoEscorregamentoDIN51097: A; ResistenciaAoEscorregamentoENV51097: A; ResistenciaAoDeslizamentoENV12633: Class 1; ResistenciaAoEscorregamentoANSIA1371: ≥0,42; ResistenciaAoEscorregamentoENV12633: Class 1; ResistenciaAsManchas: Class 5; ResistenciaABaixasConcentracoesDeAcidosEAlcalis: Classe LA; ResistenciaAAltasConcentracoesDeAcidosEAlcalis: Classe HA; LibertacaoDeCadmio: 0; LibertacaoDeChumbo: 0
Type - IFC.REVIGRÉS-Dados de especificação-Wall Sweeps - VariacaoTonalidade: 2; NivelDeTrafego: 0; EPavimento: Não; ERevestimento: Sim; EExterno: Sim
Type - IFC.REVIGRÉS-Dados geométricos-Wall Sweeps - AlturaNominal: 10.5 mm; ComprimentoNominal: 8 mm; LarguraNominal: 889 mm
Type - IFC.REVIGRÉS-Dados de sustentabilidade-Wall Sweeps - PotencialPrivacaoDeAguaConsumoDeAguaPonderado: 4.5; EnergiaTermicaExportada: 0; ItemENovo: Sim; ItemEParcialmenteReciclado: 0.29; ItemEReciclado: Sim; VidaÚtilEsperada: 50; SubstanciasPerigosas: Não; PotencialDeEsgotamentoAbioticoDosRecursosFosseis: 203; PotencialDeEsgotamentoAbioticoDosRecursosNaoFosseisMineraisEMetais: 0.000701; PotencialDeAquecimentoGlobalBiogenico: -0.48; CombustiveisFosseisComPotencialDeAquecimentoGlobal: 13.9; PotencialDeAquecimentoGlobalUsoDoSoloEMudancaDeUsoDoSolo: 0.0246; PotencialDeEutrofizacaoFraccaoDeNutrientesQueAtingemOCompartimentoFinalDeAguaDoce: 0.000189; PotencialDeEutrofizacaoFraccaoDeNutrientesQueAtingemOCompartimentoFinalMarinho: 0.0122; EnergiaRecuperada: 0.00739; ConsumoDeAguaDoce: 0.113; UtilizacaoLiquidaDeAguaDoce: 0.113; ResiduosPerigososEliminados: 0.00221; ResiduosNaoPerigososEliminados: 1.83; MassaTotalDeResiduosRadioactivosEliminados: 0.000394; EnergiaElectricaExportada: 1.55; MateriaisParaRecuperacaoDeEnergia: 0.00739; MateriaisParaReciclagem: 0.0253; UnidadeEPD: 1 m²
Type - IFC.REVIGRÉS-Dados gerais-Wall Sweeps - Nome: REVIGRÉS-URBAN-RB-8X90-RECT-URBAN ANTRACITE; TipoProduto: Prensado a seco: grupo BIa UGL | Grés porcelânico técnico; NumeroDeRegistoDAP: EPD-REV-20240006-CCC1-EN; ReferenciaDAP: -; UrlDOP: -
Pset_ProvisionForVoid - Shape: Undefined; Width: 1000 mm; Depth: 1000 mm
IFC.REVIGRÉS-Dados do fabricante-Wall Sweeps - Type: Wall Sweep: REVIGRÉS-URBAN-RB-8X90-RECT-ANTRACITE
IFC.REVIGRÉS-Dados de desempenho-Wall Sweeps - Type: Wall Sweep: REVIGRÉS-URBAN-RB-8X90-RECT-ANTRACITE
IFC.REVIGRÉS-Dados de especificação-Wall Sweeps - Type: Wall Sweep: REVIGRÉS-URBAN-RB-8X90-RECT-ANTRACITE
IFC.REVIGRÉS-Dados geométricos-Wall Sweeps - Type: Wall Sweep: REVIGRÉS-URBAN-RB-8X90-RECT-ANTRACITE
IFC.REVIGRÉS-Dados de sustentabilidade-Wall Sweeps - Type: Wall Sweep: REVIGRÉS-URBAN-RB-8X90-RECT-ANTRACITE

# IfcBuildingElementProxy: Wall Sweep:REVIGRÉS-URBAN-RB-8X90-RECT-BONE, Wall Sweep:REVIGRÉS-URBAN-RB-8X90-RECT-BONE:182754
In: Level 1
Type - Pset_ManufacturerTypeInformation - Manufacturer: REVIGRÉS
Type - Pset_ProductRequirements - Category: Wall Sweeps
Type - IFC.REVIGRÉS-Dados do fabricante-Wall Sweeps - FabricanteURL: https://www.revigres.pt/; ReferenciaModelo: Urban; Acabamento: NAT; IdentificadorDoOperadorEconomico: 501840856; UrlFabricanteArtigo: https://www.revigres.pt/colecoes/urban; PaisOrigem: Portugal
Type - IFC.REVIGRÉS-Dados de desempenho-Wall Sweeps - Rectilinearidade: ± 0.3% máx. ± 1.5 mm; Ortogonalidade: ± 0.3% máx. ± 1.8 mm; PlanaridadeDaSuperficie: ± 0.3% máx. ± 1.8 mm; AbsorcaoDeAgua: < 0.05%; ModuloDeRuptura: > 45 N/mm²; ResistenciaAFlexao: > 2000 N; ResistenciaAAbrasaoProfunda: < 120 mm³; DilatacaoTermicaLinear: ≤ 8,0x10-6 °C-1; ResistenciaAoChoqueTermico: Resiste; DurabilidadeResistenciaAoGeloDegelo: Resiste; ResistenciaAoEscorregamentoDIN51130: R9; ResistenciaAoEscorregamentoDIN51097: A; ResistenciaAoEscorregamentoENV51097: A; ResistenciaAoDeslizamentoENV12633: Class 1; ResistenciaAoEscorregamentoANSIA1371: ≥0,42; ResistenciaAoEscorregamentoENV12633: Class 1; ResistenciaAsManchas: Class 5; ResistenciaABaixasConcentracoesDeAcidosEAlcalis: Classe LA; ResistenciaAAltasConcentracoesDeAcidosEAlcalis: Classe HA; LibertacaoDeCadmio: 0; LibertacaoDeChumbo: 0
Type - IFC.REVIGRÉS-Dados de especificação-Wall Sweeps - VariacaoTonalidade: 2; NivelDeTrafego: 0; EPavimento: Não; ERevestimento: Sim; EExterno: Sim
Type - IFC.REVIGRÉS-Dados geométricos-Wall Sweeps - AlturaNominal: 10.5 mm; ComprimentoNominal: 8 mm; LarguraNominal: 889 mm
Type - IFC.REVIGRÉS-Dados de sustentabilidade-Wall Sweeps - PotencialPrivacaoDeAguaConsumoDeAguaPonderado: 4.5; EnergiaTermicaExportada: 0; ItemENovo: Sim; ItemEParcialmenteReciclado: 0.03; ItemEReciclado: Sim; VidaÚtilEsperada: 50; SubstanciasPerigosas: Não; PotencialDeEsgotamentoAbioticoDosRecursosFosseis: 203; PotencialDeEsgotamentoAbioticoDosRecursosNaoFosseisMineraisEMetais: 0.000701; PotencialDeAquecimentoGlobalBiogenico: -0.48; CombustiveisFosseisComPotencialDeAquecimentoGlobal: 13.9; PotencialDeAquecimentoGlobalUsoDoSoloEMudancaDeUsoDoSolo: 0.0246; PotencialDeEutrofizacaoFraccaoDeNutrientesQueAtingemOCompartimentoFinalDeAguaDoce: 0.000189; PotencialDeEutrofizacaoFraccaoDeNutrientesQueAtingemOCompartimentoFinalMarinho: 0.0122; EnergiaRecuperada: 0.00739; ConsumoDeAguaDoce: 0.113; UtilizacaoLiquidaDeAguaDoce: 0.113; ResiduosPerigososEliminados: 0.00221; ResiduosNaoPerigososEliminados: 1.83; MassaTotalDeResiduosRadioactivosEliminados: 0.000394; EnergiaElectricaExportada: 1.55; MateriaisParaRecuperacaoDeEnergia: 0.00739; MateriaisParaReciclagem: 0.0253; UnidadeEPD: 1 m²
Type - IFC.REVIGRÉS-Dados gerais-Wall Sweeps - Nome: REVIGRÉS-URBAN-RB-8X90-RECT-URBAN BONE; TipoProduto: Prensado a seco: grupo BIa UGL | Grés porcelânico técnico; NumeroDeRegistoDAP: EPD-REV-20240006-CCC1-EN; ReferenciaDAP: -; UrlDOP: -
Pset_ProvisionForVoid - Shape: Undefined; Width: 1000 mm; Depth: 1000 mm
IFC.REVIGRÉS-Dados do fabricante-Wall Sweeps - Type: Wall Sweep: REVIGRÉS-URBAN-RB-8X90-RECT-BONE
IFC.REVIGRÉS-Dados de desempenho-Wall Sweeps - Type: Wall Sweep: REVIGRÉS-URBAN-RB-8X90-RECT-BONE
IFC.REVIGRÉS-Dados de especificação-Wall Sweeps - Type: Wall Sweep: REVIGRÉS-URBAN-RB-8X90-RECT-BONE
IFC.REVIGRÉS-Dados geométricos-Wall Sweeps - Type: Wall Sweep: REVIGRÉS-URBAN-RB-8X90-RECT-BONE
IFC.REVIGRÉS-Dados de sustentabilidade-Wall Sweeps - Type: Wall Sweep: REVIGRÉS-URBAN-RB-8X90-RECT-BONE

# IfcBuildingElementProxy: Wall Sweep:REVIGRÉS-URBAN-RB-8X90-RECT-CRAFT, Wall Sweep:REVIGRÉS-URBAN-RB-8X90-RECT-CRAFT:182764
In: Level 1
Type - Pset_ManufacturerTypeInformation - Manufacturer: REVIGRÉS
Type - Pset_ProductRequirements - Category: Wall Sweeps
Type - IFC.REVIGRÉS-Dados do fabricante-Wall Sweeps - FabricanteURL: https://www.revigres.pt/; ReferenciaModelo: Urban; Acabamento: NAT; IdentificadorDoOperadorEconomico: 501840856; UrlFabricanteArtigo: https://www.revigres.pt/colecoes/urban; PaisOrigem: Portugal
Type - IFC.REVIGRÉS-Dados de desempenho-Wall Sweeps - Rectilinearidade: ± 0.3% máx. ± 1.5 mm; Ortogonalidade: ± 0.3% máx. ± 1.8 mm; PlanaridadeDaSuperficie: ± 0.3% máx. ± 1.8 mm; AbsorcaoDeAgua: < 0.05%; ModuloDeRuptura: > 45 N/mm²; ResistenciaAFlexao: > 2000 N; ResistenciaAAbrasaoProfunda: < 120 mm³; DilatacaoTermicaLinear: ≤ 8,0x10-6 °C-1; ResistenciaAoChoqueTermico: Resiste; DurabilidadeResistenciaAoGeloDegelo: Resiste; ResistenciaAoEscorregamentoDIN51130: R9; ResistenciaAoEscorregamentoDIN51097: A; ResistenciaAoEscorregamentoENV51097: A; ResistenciaAoDeslizamentoENV12633: Class 1; ResistenciaAoEscorregamentoANSIA1371: ≥0,42; ResistenciaAoEscorregamentoENV12633: Class 1; ResistenciaAsManchas: Class 5; ResistenciaABaixasConcentracoesDeAcidosEAlcalis: Classe LA; ResistenciaAAltasConcentracoesDeAcidosEAlcalis: Classe HA; LibertacaoDeCadmio: 0; LibertacaoDeChumbo: 0
Type - IFC.REVIGRÉS-Dados de especificação-Wall Sweeps - VariacaoTonalidade: 2; NivelDeTrafego: 0; EPavimento: Não; ERevestimento: Sim; EExterno: Sim
Type - IFC.REVIGRÉS-Dados geométricos-Wall Sweeps - AlturaNominal: 10.5 mm; ComprimentoNominal: 8 mm; LarguraNominal: 889 mm
Type - IFC.REVIGRÉS-Dados de sustentabilidade-Wall Sweeps - PotencialPrivacaoDeAguaConsumoDeAguaPonderado: 4.5; EnergiaTermicaExportada: 0; ItemENovo: Sim; ItemEParcialmenteReciclado: 0.19; ItemEReciclado: Sim; VidaÚtilEsperada: 50; SubstanciasPerigosas: Não; PotencialDeEsgotamentoAbioticoDosRecursosFosseis: 203; PotencialDeEsgotamentoAbioticoDosRecursosNaoFosseisMineraisEMetais: 0.000701; PotencialDeAquecimentoGlobalBiogenico: -0.48; CombustiveisFosseisComPotencialDeAquecimentoGlobal: 13.9; PotencialDeAquecimentoGlobalUsoDoSoloEMudancaDeUsoDoSolo: 0.0246; PotencialDeEutrofizacaoFraccaoDeNutrientesQueAtingemOCompartimentoFinalDeAguaDoce: 0.000189; PotencialDeEutrofizacaoFraccaoDeNutrientesQueAtingemOCompartimentoFinalMarinho: 0.0122; EnergiaRecuperada: 0.00739; ConsumoDeAguaDoce: 0.113; UtilizacaoLiquidaDeAguaDoce: 0.113; ResiduosPerigososEliminados: 0.00221; ResiduosNaoPerigososEliminados: 1.83; MassaTotalDeResiduosRadioactivosEliminados: 0.000394; EnergiaElectricaExportada: 1.55; MateriaisParaRecuperacaoDeEnergia: 0.00739; MateriaisParaReciclagem: 0.0253; UnidadeEPD: 1 m²
Type - IFC.REVIGRÉS-Dados gerais-Wall Sweeps - Nome: REVIGRÉS-URBAN-RB-8X90-RECT-URBAN CRAFT; TipoProduto: Prensado a seco: grupo BIa UGL | Grés porcelânico técnico; NumeroDeRegistoDAP: EPD-REV-20240006-CCC1-EN; ReferenciaDAP: -; UrlDOP: -
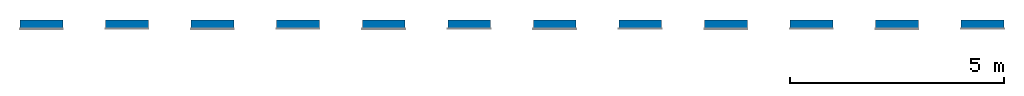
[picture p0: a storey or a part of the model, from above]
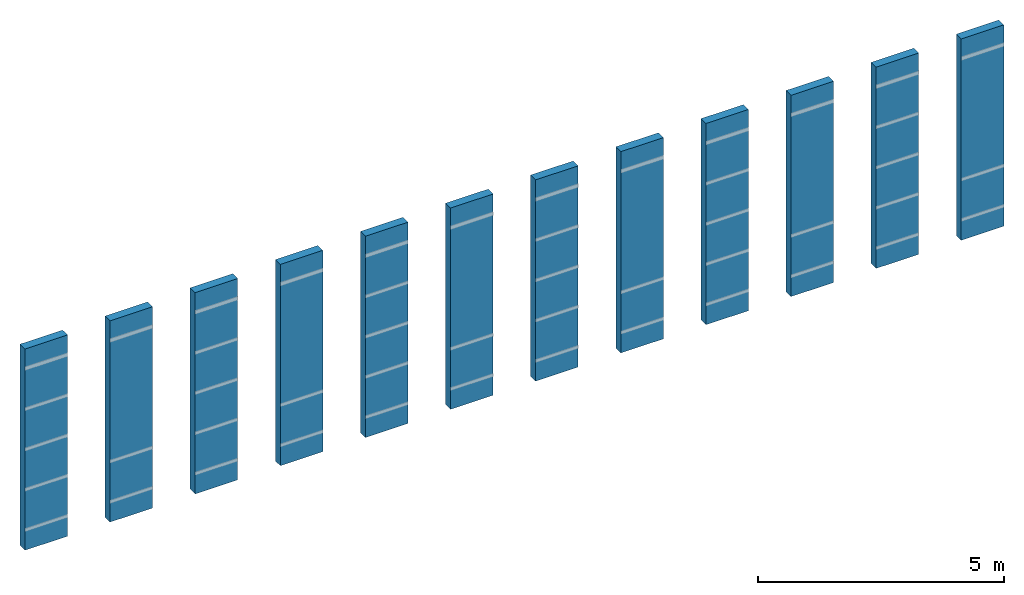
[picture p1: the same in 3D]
Properties of the parts of a building model (IFC2X3), part 3 of 3

# IfcBuildingElementProxy: Wall Sweep:REVIGRÉS-URBAN-RB-8X90-RECT-CRAFT, Wall Sweep:REVIGRÉS-URBAN-RB-8X90-RECT-CRAFT:182764
Pset_ProvisionForVoid - Shape: Undefined; Width: 1000 mm; Depth: 1000 mm
IFC.REVIGRÉS-Dados do fabricante-Wall Sweeps - Type: Wall Sweep: REVIGRÉS-URBAN-RB-8X90-RECT-CRAFT
IFC.REVIGRÉS-Dados de desempenho-Wall Sweeps - Type: Wall Sweep: REVIGRÉS-URBAN-RB-8X90-RECT-CRAFT
IFC.REVIGRÉS-Dados de especificação-Wall Sweeps - Type: Wall Sweep: REVIGRÉS-URBAN-RB-8X90-RECT-CRAFT
IFC.REVIGRÉS-Dados geométricos-Wall Sweeps - Type: Wall Sweep: REVIGRÉS-URBAN-RB-8X90-RECT-CRAFT
IFC.REVIGRÉS-Dados de sustentabilidade-Wall Sweeps - Type: Wall Sweep: REVIGRÉS-URBAN-RB-8X90-RECT-CRAFT

# IfcBuildingElementProxy: Wall Sweep:REVIGRÉS-URBAN-RB-8X90-RECT-FOG, Wall Sweep:REVIGRÉS-URBAN-RB-8X90-RECT-FOG:182774
In: Level 1
Type - Pset_ManufacturerTypeInformation - Manufacturer: REVIGRÉS
Type - Pset_ProductRequirements - Category: Wall Sweeps
Type - IFC.REVIGRÉS-Dados do fabricante-Wall Sweeps - FabricanteURL: https://www.revigres.pt/; ReferenciaModelo: Urban; Acabamento: NAT; IdentificadorDoOperadorEconomico: 501840856; UrlFabricanteArtigo: https://www.revigres.pt/colecoes/urban; PaisOrigem: Portugal
Type - IFC.REVIGRÉS-Dados de desempenho-Wall Sweeps - Rectilinearidade: ± 0.3% máx. ± 1.5 mm; Ortogonalidade: ± 0.3% máx. ± 1.8 mm; PlanaridadeDaSuperficie: ± 0.3% máx. ± 1.8 mm; AbsorcaoDeAgua: < 0.05%; ModuloDeRuptura: > 45 N/mm²; ResistenciaAFlexao: > 2000 N; ResistenciaAAbrasaoProfunda: < 120 mm³; DilatacaoTermicaLinear: ≤ 8,0x10-6 °C-1; ResistenciaAoChoqueTermico: Resiste; DurabilidadeResistenciaAoGeloDegelo: Resiste; ResistenciaAoEscorregamentoDIN51130: R9; ResistenciaAoEscorregamentoDIN51097: A; ResistenciaAoEscorregamentoENV51097: A; ResistenciaAoDeslizamentoENV12633: Class 1; ResistenciaAoEscorregamentoANSIA1371: ≥0,42; ResistenciaAoEscorregamentoENV12633: Class 1; ResistenciaAsManchas: Class 5; ResistenciaABaixasConcentracoesDeAcidosEAlcalis: Classe LA; ResistenciaAAltasConcentracoesDeAcidosEAlcalis: Classe HA; LibertacaoDeCadmio: 0; LibertacaoDeChumbo: 0
Type - IFC.REVIGRÉS-Dados de especificação-Wall Sweeps - VariacaoTonalidade: 2; NivelDeTrafego: 0; EPavimento: Não; ERevestimento: Sim; EExterno: Sim
Type - IFC.REVIGRÉS-Dados geométricos-Wall Sweeps - AlturaNominal: 10.5 mm; ComprimentoNominal: 8 mm; LarguraNominal: 889 mm
Type - IFC.REVIGRÉS-Dados de sustentabilidade-Wall Sweeps - PotencialPrivacaoDeAguaConsumoDeAguaPonderado: 4.5; EnergiaTermicaExportada: 0; ItemENovo: Sim; ItemEParcialmenteReciclado: 0.23; ItemEReciclado: Sim; VidaÚtilEsperada: 50; SubstanciasPerigosas: Não; PotencialDeEsgotamentoAbioticoDosRecursosFosseis: 203; PotencialDeEsgotamentoAbioticoDosRecursosNaoFosseisMineraisEMetais: 0.000701; PotencialDeAquecimentoGlobalBiogenico: -0.48; CombustiveisFosseisComPotencialDeAquecimentoGlobal: 13.9; PotencialDeAquecimentoGlobalUsoDoSoloEMudancaDeUsoDoSolo: 0.0246; PotencialDeEutrofizacaoFraccaoDeNutrientesQueAtingemOCompartimentoFinalDeAguaDoce: 0.000189; PotencialDeEutrofizacaoFraccaoDeNutrientesQueAtingemOCompartimentoFinalMarinho: 0.0122; EnergiaRecuperada: 0.00739; ConsumoDeAguaDoce: 0.113; UtilizacaoLiquidaDeAguaDoce: 0.113; ResiduosPerigososEliminados: 0.00221; ResiduosNaoPerigososEliminados: 1.83; MassaTotalDeResiduosRadioactivosEliminados: 0.000394; EnergiaElectricaExportada: 1.55; MateriaisParaRecuperacaoDeEnergia: 0.00739; MateriaisParaReciclagem: 0.0253; UnidadeEPD: 1 m²
Type - IFC.REVIGRÉS-Dados gerais-Wall Sweeps - Nome: REVIGRÉS-URBAN-RB-8X90-RECT-URBAN FOG; TipoProduto: Prensado a seco: grupo BIa UGL | Grés porcelânico técnico; NumeroDeRegistoDAP: EPD-REV-20240006-CCC1-EN; ReferenciaDAP: -; UrlDOP: -
Pset_ProvisionForVoid - Shape: Undefined; Width: 1000 mm; Depth: 1000 mm
IFC.REVIGRÉS-Dados do fabricante-Wall Sweeps - Type: Wall Sweep: REVIGRÉS-URBAN-RB-8X90-RECT-FOG
IFC.REVIGRÉS-Dados de desempenho-Wall Sweeps - Type: Wall Sweep: REVIGRÉS-URBAN-RB-8X90-RECT-FOG
IFC.REVIGRÉS-Dados de especificação-Wall Sweeps - Type: Wall Sweep: REVIGRÉS-URBAN-RB-8X90-RECT-FOG
IFC.REVIGRÉS-Dados geométricos-Wall Sweeps - Type: Wall Sweep: REVIGRÉS-URBAN-RB-8X90-RECT-FOG
IFC.REVIGRÉS-Dados de sustentabilidade-Wall Sweeps - Type: Wall Sweep: REVIGRÉS-URBAN-RB-8X90-RECT-FOG

# IfcBuildingElementProxy: Wall Sweep:REVIGRÉS-URBAN-RB-8X90-RECT-GRIS, Wall Sweep:REVIGRÉS-URBAN-RB-8X90-RECT-GRIS:182784
In: Level 1
Type - Pset_ManufacturerTypeInformation - Manufacturer: REVIGRÉS
Type - Pset_ProductRequirements - Category: Wall Sweeps
Type - IFC.REVIGRÉS-Dados do fabricante-Wall Sweeps - FabricanteURL: https://www.revigres.pt/; ReferenciaModelo: Urban; Acabamento: NAT; IdentificadorDoOperadorEconomico: 501840856; UrlFabricanteArtigo: https://www.revigres.pt/colecoes/urban; PaisOrigem: Portugal
Type - IFC.REVIGRÉS-Dados de desempenho-Wall Sweeps - Rectilinearidade: ± 0.3% máx. ± 1.5 mm; Ortogonalidade: ± 0.3% máx. ± 1.8 mm; PlanaridadeDaSuperficie: ± 0.3% máx. ± 1.8 mm; AbsorcaoDeAgua: < 0.05%; ModuloDeRuptura: > 45 N/mm²; ResistenciaAFlexao: > 2000 N; ResistenciaAAbrasaoProfunda: < 120 mm³; DilatacaoTermicaLinear: ≤ 8,0x10-6 °C-1; ResistenciaAoChoqueTermico: Resiste; DurabilidadeResistenciaAoGeloDegelo: Resiste; ResistenciaAoEscorregamentoDIN51130: R9; ResistenciaAoEscorregamentoDIN51097: A; ResistenciaAoEscorregamentoENV51097: A; ResistenciaAoDeslizamentoENV12633: Class 1; ResistenciaAoEscorregamentoANSIA1371: ≥0,42; ResistenciaAoEscorregamentoENV12633: Class 1; ResistenciaAsManchas: Class 5; ResistenciaABaixasConcentracoesDeAcidosEAlcalis: Classe LA; ResistenciaAAltasConcentracoesDeAcidosEAlcalis: Classe HA; LibertacaoDeCadmio: 0; LibertacaoDeChumbo: 0
Type - IFC.REVIGRÉS-Dados de especificação-Wall Sweeps - VariacaoTonalidade: 2; NivelDeTrafego: 0; EPavimento: Não; ERevestimento: Sim; EExterno: Sim
Type - IFC.REVIGRÉS-Dados geométricos-Wall Sweeps - AlturaNominal: 10.5 mm; ComprimentoNominal: 8 mm; LarguraNominal: 889 mm
Type - IFC.REVIGRÉS-Dados de sustentabilidade-Wall Sweeps - PotencialPrivacaoDeAguaConsumoDeAguaPonderado: 4.5; EnergiaTermicaExportada: 0; ItemENovo: Sim; ItemEParcialmenteReciclado: 0.23; ItemEReciclado: Sim; VidaÚtilEsperada: 50; SubstanciasPerigosas: Não; PotencialDeEsgotamentoAbioticoDosRecursosFosseis: 203; PotencialDeEsgotamentoAbioticoDosRecursosNaoFosseisMineraisEMetais: 0.000701; PotencialDeAquecimentoGlobalBiogenico: -0.48; CombustiveisFosseisComPotencialDeAquecimentoGlobal: 13.9; PotencialDeAquecimentoGlobalUsoDoSoloEMudancaDeUsoDoSolo: 0.0246; PotencialDeEutrofizacaoFraccaoDeNutrientesQueAtingemOCompartimentoFinalDeAguaDoce: 0.000189; PotencialDeEutrofizacaoFraccaoDeNutrientesQueAtingemOCompartimentoFinalMarinho: 0.0122; EnergiaRecuperada: 0.00739; ConsumoDeAguaDoce: 0.113; UtilizacaoLiquidaDeAguaDoce: 0.113; ResiduosPerigososEliminados: 0.00221; ResiduosNaoPerigososEliminados: 1.83; MassaTotalDeResiduosRadioactivosEliminados: 0.000394; EnergiaElectricaExportada: 1.55; MateriaisParaRecuperacaoDeEnergia: 0.00739; MateriaisParaReciclagem: 0.0253; UnidadeEPD: 1 m²
Type - IFC.REVIGRÉS-Dados gerais-Wall Sweeps - Nome: REVIGRÉS-URBAN-RB-8X90-RECT-URBAN GRIS; TipoProduto: Prensado a seco: grupo BIa UGL | Grés porcelânico técnico; NumeroDeRegistoDAP: EPD-REV-20240006-CCC1-EN; ReferenciaDAP: -; UrlDOP: -
Pset_ProvisionForVoid - Shape: Undefined; Width: 1000 mm; Depth: 1000 mm
IFC.REVIGRÉS-Dados do fabricante-Wall Sweeps - Type: Wall Sweep: REVIGRÉS-URBAN-RB-8X90-RECT-GRIS
IFC.REVIGRÉS-Dados de desempenho-Wall Sweeps - Type: Wall Sweep: REVIGRÉS-URBAN-RB-8X90-RECT-GRIS
IFC.REVIGRÉS-Dados de especificação-Wall Sweeps - Type: Wall Sweep: REVIGRÉS-URBAN-RB-8X90-RECT-GRIS
IFC.REVIGRÉS-Dados geométricos-Wall Sweeps - Type: Wall Sweep: REVIGRÉS-URBAN-RB-8X90-RECT-GRIS
IFC.REVIGRÉS-Dados de sustentabilidade-Wall Sweeps - Type: Wall Sweep: REVIGRÉS-URBAN-RB-8X90-RECT-GRIS

# IfcBuildingElementProxy: Wall Sweep:REVIGRÉS-URBAN-RB-8X90-RECT-OFFWHITE, Wall Sweep:REVIGRÉS-URBAN-RB-8X90-RECT-OFFWHITE:182794
In: Level 1
Type - Pset_ManufacturerTypeInformation - Manufacturer: REVIGRÉS
Type - Pset_ProductRequirements - Category: Wall Sweeps
Type - IFC.REVIGRÉS-Dados do fabricante-Wall Sweeps - FabricanteURL: https://www.revigres.pt/; ReferenciaModelo: Urban; Acabamento: NAT; IdentificadorDoOperadorEconomico: 501840856; UrlFabricanteArtigo: https://www.revigres.pt/colecoes/urban; PaisOrigem: Portugal
Type - IFC.REVIGRÉS-Dados de desempenho-Wall Sweeps - Rectilinearidade: ± 0.3% máx. ± 1.5 mm; Ortogonalidade: ± 0.3% máx. ± 1.8 mm; PlanaridadeDaSuperficie: ± 0.3% máx. ± 1.8 mm; AbsorcaoDeAgua: < 0.05%; ModuloDeRuptura: > 45 N/mm²; ResistenciaAFlexao: > 2000 N; ResistenciaAAbrasaoProfunda: < 120 mm³; DilatacaoTermicaLinear: ≤ 8,0x10-6 °C-1; ResistenciaAoChoqueTermico: Resiste; DurabilidadeResistenciaAoGeloDegelo: Resiste; ResistenciaAoEscorregamentoDIN51130: R9; ResistenciaAoEscorregamentoDIN51097: A; ResistenciaAoEscorregamentoENV51097: A; ResistenciaAoDeslizamentoENV12633: Class 1; ResistenciaAoEscorregamentoANSIA1371: ≥0,42; ResistenciaAoEscorregamentoENV12633: Class 1; ResistenciaAsManchas: Class 5; ResistenciaABaixasConcentracoesDeAcidosEAlcalis: Classe LA; ResistenciaAAltasConcentracoesDeAcidosEAlcalis: Classe HA; LibertacaoDeCadmio: 0; LibertacaoDeChumbo: 0
Type - IFC.REVIGRÉS-Dados de especificação-Wall Sweeps - VariacaoTonalidade: 2; NivelDeTrafego: 0; EPavimento: Não; ERevestimento: Sim; EExterno: Sim
Type - IFC.REVIGRÉS-Dados geométricos-Wall Sweeps - AlturaNominal: 10.5 mm; ComprimentoNominal: 8 mm; LarguraNominal: 889 mm
Type - IFC.REVIGRÉS-Dados de sustentabilidade-Wall Sweeps - PotencialPrivacaoDeAguaConsumoDeAguaPonderado: 4.5; EnergiaTermicaExportada: 0; ItemENovo: Sim; ItemEParcialmenteReciclado: 0.03; ItemEReciclado: Sim; VidaÚtilEsperada: 50; SubstanciasPerigosas: Não; PotencialDeEsgotamentoAbioticoDosRecursosFosseis: 203; PotencialDeEsgotamentoAbioticoDosRecursosNaoFosseisMineraisEMetais: 0.000701; PotencialDeAquecimentoGlobalBiogenico: -0.48; CombustiveisFosseisComPotencialDeAquecimentoGlobal: 13.9; PotencialDeAquecimentoGlobalUsoDoSoloEMudancaDeUsoDoSolo: 0.0246; PotencialDeEutrofizacaoFraccaoDeNutrientesQueAtingemOCompartimentoFinalDeAguaDoce: 0.000189; PotencialDeEutrofizacaoFraccaoDeNutrientesQueAtingemOCompartimentoFinalMarinho: 0.0122; EnergiaRecuperada: 0.00739; ConsumoDeAguaDoce: 0.113; UtilizacaoLiquidaDeAguaDoce: 0.113; ResiduosPerigososEliminados: 0.00221; ResiduosNaoPerigososEliminados: 1.83; MassaTotalDeResiduosRadioactivosEliminados: 0.000394; EnergiaElectricaExportada: 1.55; MateriaisParaRecuperacaoDeEnergia: 0.00739; MateriaisParaReciclagem: 0.0253; UnidadeEPD: 1 m²
Type - IFC.REVIGRÉS-Dados gerais-Wall Sweeps - Nome: REVIGRÉS-URBAN-RB-8X90-RECT-URBAN OFFWHITE; TipoProduto: Prensado a seco: grupo BIa UGL | Grés porcelânico técnico; NumeroDeRegistoDAP: EPD-REV-20240006-CCC1-EN; ReferenciaDAP: -; UrlDOP: -
Pset_ProvisionForVoid - Shape: Undefined; Width: 1000 mm; Depth: 1000 mm
IFC.REVIGRÉS-Dados do fabricante-Wall Sweeps - Type: Wall Sweep: REVIGRÉS-URBAN-RB-8X90-RECT-OFFWHITE
IFC.REVIGRÉS-Dados de desempenho-Wall Sweeps - Type: Wall Sweep: REVIGRÉS-URBAN-RB-8X90-RECT-OFFWHITE
IFC.REVIGRÉS-Dados de especificação-Wall Sweeps - Type: Wall Sweep: REVIGRÉS-URBAN-RB-8X90-RECT-OFFWHITE
IFC.REVIGRÉS-Dados geométricos-Wall Sweeps - Type: Wall Sweep: REVIGRÉS-URBAN-RB-8X90-RECT-OFFWHITE
IFC.REVIGRÉS-Dados de sustentabilidade-Wall Sweeps - Type: Wall Sweep: REVIGRÉS-URBAN-RB-8X90-RECT-OFFWHITE

# IfcBuildingElementProxy: Wall Sweep:REVIGRÉS-URBAN-RB-9.5X30-NAT-ANTRACITE, Wall Sweep:REVIGRÉS-URBAN-RB-9.5X30-NAT-ANTRACITE:182750
In: Level 1
Type - Pset_ManufacturerTypeInformation - Manufacturer: REVIGRÉS
Type - Pset_ProductRequirements - Category: Wall Sweeps
Type - IFC.REVIGRÉS-Dados do fabricante-Wall Sweeps - FabricanteURL: https://www.revigres.pt/; ReferenciaModelo: Urban; Acabamento: RECT; IdentificadorDoOperadorEconomico: 501840856; UrlFabricanteArtigo: https://www.revigres.pt/colecoes/urban; PaisOrigem: Portugal
Type - IFC.REVIGRÉS-Dados de desempenho-Wall Sweeps - Rectilinearidade: ± 0.2% máx.± 0.8 mm; Ortogonalidade: ± 0.2% máx.± 1.5 mm; PlanaridadeDaSuperficie: ± 0.3% máx. ± 1.8 mm; AbsorcaoDeAgua: < 0.05%; ModuloDeRuptura: > 45 N/mm²; ResistenciaAFlexao: > 1500 N; ResistenciaAAbrasaoProfunda: < 120 mm³; DilatacaoTermicaLinear: ≤ 8,0x10-6 °C-1; ResistenciaAoChoqueTermico: Resiste; DurabilidadeResistenciaAoGeloDegelo: Resiste; ResistenciaAoEscorregamentoDIN51130: R9; ResistenciaAoEscorregamentoDIN51097: A; ResistenciaAoEscorregamentoENV51097: A; ResistenciaAoDeslizamentoENV12633: Class 1; ResistenciaAoEscorregamentoANSIA1371: ≥0,42; ResistenciaAoEscorregamentoENV12633: Class 1; ResistenciaAsManchas: Class 5; ResistenciaABaixasConcentracoesDeAcidosEAlcalis: Classe LA; ResistenciaAAltasConcentracoesDeAcidosEAlcalis: Classe HA; LibertacaoDeCadmio: 0; LibertacaoDeChumbo: 0
Type - IFC.REVIGRÉS-Dados de especificação-Wall Sweeps - VariacaoTonalidade: 2; NivelDeTrafego: 0; EPavimento: Não; ERevestimento: Sim; EExterno: Sim
Type - IFC.REVIGRÉS-Dados geométricos-Wall Sweeps - AlturaNominal: 7.7 mm; ComprimentoNominal: 9.5 mm; LarguraNominal: 30 mm
Type - IFC.REVIGRÉS-Dados de sustentabilidade-Wall Sweeps - PotencialPrivacaoDeAguaConsumoDeAguaPonderado: 4.5; EnergiaTermicaExportada: 0; ItemENovo: Sim; ItemEParcialmenteReciclado: 0.29; ItemEReciclado: Sim; VidaÚtilEsperada: 50; SubstanciasPerigosas: Não; PotencialDeEsgotamentoAbioticoDosRecursosFosseis: 203; PotencialDeEsgotamentoAbioticoDosRecursosNaoFosseisMineraisEMetais: 0.000701; PotencialDeAquecimentoGlobalBiogenico: -0.48; CombustiveisFosseisComPotencialDeAquecimentoGlobal: 13.9; PotencialDeAquecimentoGlobalUsoDoSoloEMudancaDeUsoDoSolo: 0.0246; PotencialDeEutrofizacaoFraccaoDeNutrientesQueAtingemOCompartimentoFinalDeAguaDoce: 0.000189; PotencialDeEutrofizacaoFraccaoDeNutrientesQueAtingemOCompartimentoFinalMarinho: 0.0122; EnergiaRecuperada: 0.00739; ConsumoDeAguaDoce: 0.113; UtilizacaoLiquidaDeAguaDoce: 0.113; ResiduosPerigososEliminados: 0.00221; ResiduosNaoPerigososEliminados: 1.83; MassaTotalDeResiduosRadioactivosEliminados: 0.000394; EnergiaElectricaExportada: 1.55; MateriaisParaRecuperacaoDeEnergia: 0.00739; MateriaisParaReciclagem: 0.0253; UnidadeEPD: 1 m²
Type - IFC.REVIGRÉS-Dados gerais-Wall Sweeps - Nome: REVIGRÉS-URBAN-RB-9,5X30-NAT-URBAN ANTRACITE; TipoProduto: Prensado a seco: grupo BIa UGL | Grés porcelânico técnico; NumeroDeRegistoDAP: EPD-REV-20240006-CCC1-EN; ReferenciaDAP: -; UrlDOP: -
Pset_ProvisionForVoid - Shape: Undefined; Width: 1000 mm; Depth: 1000 mm
IFC.REVIGRÉS-Dados do fabricante-Wall Sweeps - Type: Wall Sweep: REVIGRÉS-URBAN-RB-9.5X30-NAT-ANTRACITE
IFC.REVIGRÉS-Dados de desempenho-Wall Sweeps - Type: Wall Sweep: REVIGRÉS-URBAN-RB-9.5X30-NAT-ANTRACITE
IFC.REVIGRÉS-Dados de especificação-Wall Sweeps - Type: Wall Sweep: REVIGRÉS-URBAN-RB-9.5X30-NAT-ANTRACITE
IFC.REVIGRÉS-Dados geométricos-Wall Sweeps - Type: Wall Sweep: REVIGRÉS-URBAN-RB-9.5X30-NAT-ANTRACITE
IFC.REVIGRÉS-Dados de sustentabilidade-Wall Sweeps - Type: Wall Sweep: REVIGRÉS-URBAN-RB-9.5X30-NAT-ANTRACITE

# IfcBuildingElementProxy: Wall Sweep:REVIGRÉS-URBAN-RB-9.5X30-NAT-BONE, Wall Sweep:REVIGRÉS-URBAN-RB-9.5X30-NAT-BONE:182760
In: Level 1
Type - Pset_ManufacturerTypeInformation - Manufacturer: REVIGRÉS
Type - Pset_ProductRequirements - Category: Wall Sweeps
Type - IFC.REVIGRÉS-Dados do fabricante-Wall Sweeps - FabricanteURL: https://www.revigres.pt/; ReferenciaModelo: Urban; Acabamento: RECT; IdentificadorDoOperadorEconomico: 501840856; UrlFabricanteArtigo: https://www.revigres.pt/colecoes/urban; PaisOrigem: Portugal
Type - IFC.REVIGRÉS-Dados de desempenho-Wall Sweeps - Rectilinearidade: ± 0.2% máx.± 0.8 mm; Ortogonalidade: ± 0.2% máx.± 1.5 mm; PlanaridadeDaSuperficie: ± 0.3% máx. ± 1.8 mm; AbsorcaoDeAgua: < 0.05%; ModuloDeRuptura: > 45 N/mm²; ResistenciaAFlexao: > 1500 N; ResistenciaAAbrasaoProfunda: < 120 mm³; DilatacaoTermicaLinear: ≤ 8,0x10-6 °C-1; ResistenciaAoChoqueTermico: Resiste; DurabilidadeResistenciaAoGeloDegelo: Resiste; ResistenciaAoEscorregamentoDIN51130: R9; ResistenciaAoEscorregamentoDIN51097: A; ResistenciaAoEscorregamentoENV51097: A; ResistenciaAoDeslizamentoENV12633: Class 1; ResistenciaAoEscorregamentoANSIA1371: ≥0,42; ResistenciaAoEscorregamentoENV12633: Class 1; ResistenciaAsManchas: Class 5; ResistenciaABaixasConcentracoesDeAcidosEAlcalis: Classe LA; ResistenciaAAltasConcentracoesDeAcidosEAlcalis: Classe HA; LibertacaoDeCadmio: 0; LibertacaoDeChumbo: 0
Type - IFC.REVIGRÉS-Dados de especificação-Wall Sweeps - VariacaoTonalidade: 2; NivelDeTrafego: 0; EPavimento: Não; ERevestimento: Sim; EExterno: Sim
Type - IFC.REVIGRÉS-Dados geométricos-Wall Sweeps - AlturaNominal: 7.7 mm; ComprimentoNominal: 9.5 mm; LarguraNominal: 30 mm
Type - IFC.REVIGRÉS-Dados de sustentabilidade-Wall Sweeps - PotencialPrivacaoDeAguaConsumoDeAguaPonderado: 4.5; EnergiaTermicaExportada: 0; ItemENovo: Sim; ItemEParcialmenteReciclado: 0.03; ItemEReciclado: Sim; VidaÚtilEsperada: 50; SubstanciasPerigosas: Não; PotencialDeEsgotamentoAbioticoDosRecursosFosseis: 203; PotencialDeEsgotamentoAbioticoDosRecursosNaoFosseisMineraisEMetais: 0.000701; PotencialDeAquecimentoGlobalBiogenico: -0.48; CombustiveisFosseisComPotencialDeAquecimentoGlobal: 13.9; PotencialDeAquecimentoGlobalUsoDoSoloEMudancaDeUsoDoSolo: 0.0246; PotencialDeEutrofizacaoFraccaoDeNutrientesQueAtingemOCompartimentoFinalDeAguaDoce: 0.000189; PotencialDeEutrofizacaoFraccaoDeNutrientesQueAtingemOCompartimentoFinalMarinho: 0.0122; EnergiaRecuperada: 0.00739; ConsumoDeAguaDoce: 0.113; UtilizacaoLiquidaDeAguaDoce: 0.113; ResiduosPerigososEliminados: 0.00221; ResiduosNaoPerigososEliminados: 1.83; MassaTotalDeResiduosRadioactivosEliminados: 0.000394; EnergiaElectricaExportada: 1.55; MateriaisParaRecuperacaoDeEnergia: 0.00739; MateriaisParaReciclagem: 0.0253; UnidadeEPD: 1 m²
Type - IFC.REVIGRÉS-Dados gerais-Wall Sweeps - Nome: REVIGRÉS-URBAN-RB-9,5X30-NAT-URBAN BONE; TipoProduto: Prensado a seco: grupo BIa UGL | Grés porcelânico técnico; NumeroDeRegistoDAP: EPD-REV-20240006-CCC1-EN; ReferenciaDAP: -; UrlDOP: -
Pset_ProvisionForVoid - Shape: Undefined; Width: 1000 mm; Depth: 1000 mm
IFC.REVIGRÉS-Dados do fabricante-Wall Sweeps - Type: Wall Sweep: REVIGRÉS-URBAN-RB-9.5X30-NAT-BONE
IFC.REVIGRÉS-Dados de desempenho-Wall Sweeps - Type: Wall Sweep: REVIGRÉS-URBAN-RB-9.5X30-NAT-BONE
IFC.REVIGRÉS-Dados de especificação-Wall Sweeps - Type: Wall Sweep: REVIGRÉS-URBAN-RB-9.5X30-NAT-BONE
IFC.REVIGRÉS-Dados geométricos-Wall Sweeps - Type: Wall Sweep: REVIGRÉS-URBAN-RB-9.5X30-NAT-BONE
IFC.REVIGRÉS-Dados de sustentabilidade-Wall Sweeps - Type: Wall Sweep: REVIGRÉS-URBAN-RB-9.5X30-NAT-BONE

# IfcBuildingElementProxy: Wall Sweep:REVIGRÉS-URBAN-RB-9.5X30-NAT-CRAFT, Wall Sweep:REVIGRÉS-URBAN-RB-9.5X30-NAT-CRAFT:182770
In: Level 1
Type - Pset_ManufacturerTypeInformation - Manufacturer: REVIGRÉS
Type - Pset_ProductRequirements - Category: Wall Sweeps
Type - IFC.REVIGRÉS-Dados do fabricante-Wall Sweeps - FabricanteURL: https://www.revigres.pt/; ReferenciaModelo: Urban; Acabamento: RECT; IdentificadorDoOperadorEconomico: 501840856; UrlFabricanteArtigo: https://www.revigres.pt/colecoes/urban; PaisOrigem: Portugal
Type - IFC.REVIGRÉS-Dados de desempenho-Wall Sweeps - Rectilinearidade: ± 0.2% máx.± 0.8 mm; Ortogonalidade: ± 0.2% máx.± 1.5 mm; PlanaridadeDaSuperficie: ± 0.3% máx. ± 1.8 mm; AbsorcaoDeAgua: < 0.05%; ModuloDeRuptura: > 45 N/mm²; ResistenciaAFlexao: > 1500 N; ResistenciaAAbrasaoProfunda: < 120 mm³; DilatacaoTermicaLinear: ≤ 8,0x10-6 °C-1; ResistenciaAoChoqueTermico: Resiste; DurabilidadeResistenciaAoGeloDegelo: Resiste; ResistenciaAoEscorregamentoDIN51130: R9; ResistenciaAoEscorregamentoDIN51097: A; ResistenciaAoEscorregamentoENV51097: A; ResistenciaAoDeslizamentoENV12633: Class 1; ResistenciaAoEscorregamentoANSIA1371: ≥0,42; ResistenciaAoEscorregamentoENV12633: Class 1; ResistenciaAsManchas: Class 5; ResistenciaABaixasConcentracoesDeAcidosEAlcalis: Classe LA; ResistenciaAAltasConcentracoesDeAcidosEAlcalis: Classe HA; LibertacaoDeCadmio: 0; LibertacaoDeChumbo: 0
Type - IFC.REVIGRÉS-Dados de especificação-Wall Sweeps - VariacaoTonalidade: 2; NivelDeTrafego: 0; EPavimento: Não; ERevestimento: Sim; EExterno: Sim
Type - IFC.REVIGRÉS-Dados geométricos-Wall Sweeps - AlturaNominal: 7.7 mm; ComprimentoNominal: 9.5 mm; LarguraNominal: 30 mm
Type - IFC.REVIGRÉS-Dados de sustentabilidade-Wall Sweeps - PotencialPrivacaoDeAguaConsumoDeAguaPonderado: 4.5; EnergiaTermicaExportada: 0; ItemENovo: Sim; ItemEParcialmenteReciclado: 0.19; ItemEReciclado: Sim; VidaÚtilEsperada: 50; SubstanciasPerigosas: Não; PotencialDeEsgotamentoAbioticoDosRecursosFosseis: 203; PotencialDeEsgotamentoAbioticoDosRecursosNaoFosseisMineraisEMetais: 0.000701; PotencialDeAquecimentoGlobalBiogenico: -0.48; CombustiveisFosseisComPotencialDeAquecimentoGlobal: 13.9; PotencialDeAquecimentoGlobalUsoDoSoloEMudancaDeUsoDoSolo: 0.0246; PotencialDeEutrofizacaoFraccaoDeNutrientesQueAtingemOCompartimentoFinalDeAguaDoce: 0.000189; PotencialDeEutrofizacaoFraccaoDeNutrientesQueAtingemOCompartimentoFinalMarinho: 0.0122; EnergiaRecuperada: 0.00739; ConsumoDeAguaDoce: 0.113; UtilizacaoLiquidaDeAguaDoce: 0.113; ResiduosPerigososEliminados: 0.00221; ResiduosNaoPerigososEliminados: 1.83; MassaTotalDeResiduosRadioactivosEliminados: 0.000394; EnergiaElectricaExportada: 1.55; MateriaisParaRecuperacaoDeEnergia: 0.00739; MateriaisParaReciclagem: 0.0253; UnidadeEPD: 1 m²
Type - IFC.REVIGRÉS-Dados gerais-Wall Sweeps - Nome: REVIGRÉS-URBAN-RB-9,5X30-NAT-URBAN CRAFT; TipoProduto: Prensado a seco: grupo BIa UGL | Grés porcelânico técnico; NumeroDeRegistoDAP: EPD-REV-20240006-CCC1-EN; ReferenciaDAP: -; UrlDOP: -
Pset_ProvisionForVoid - Shape: Undefined; Width: 1000 mm; Depth: 1000 mm
IFC.REVIGRÉS-Dados do fabricante-Wall Sweeps - Type: Wall Sweep: REVIGRÉS-URBAN-RB-9.5X30-NAT-CRAFT
IFC.REVIGRÉS-Dados de desempenho-Wall Sweeps - Type: Wall Sweep: REVIGRÉS-URBAN-RB-9.5X30-NAT-CRAFT
IFC.REVIGRÉS-Dados de especificação-Wall Sweeps - Type: Wall Sweep: REVIGRÉS-URBAN-RB-9.5X30-NAT-CRAFT
IFC.REVIGRÉS-Dados geométricos-Wall Sweeps - Type: Wall Sweep: REVIGRÉS-URBAN-RB-9.5X30-NAT-CRAFT
IFC.REVIGRÉS-Dados de sustentabilidade-Wall Sweeps - Type: Wall Sweep: REVIGRÉS-URBAN-RB-9.5X30-NAT-CRAFT

# IfcBuildingElementProxy: Wall Sweep:REVIGRÉS-URBAN-RB-9.5X30-NAT-FOG, Wall Sweep:REVIGRÉS-URBAN-RB-9.5X30-NAT-FOG:182780
In: Level 1
Type - Pset_ManufacturerTypeInformation - Manufacturer: REVIGRÉS
Type - Pset_ProductRequirements - Category: Wall Sweeps
Type - IFC.REVIGRÉS-Dados do fabricante-Wall Sweeps - FabricanteURL: https://www.revigres.pt/; ReferenciaModelo: Urban; Acabamento: RECT; IdentificadorDoOperadorEconomico: 501840856; UrlFabricanteArtigo: https://www.revigres.pt/colecoes/urban; PaisOrigem: Portugal
Type - IFC.REVIGRÉS-Dados de desempenho-Wall Sweeps - Rectilinearidade: ± 0.2% máx.± 0.8 mm; Ortogonalidade: ± 0.2% máx.± 1.5 mm; PlanaridadeDaSuperficie: ± 0.3% máx. ± 1.8 mm; AbsorcaoDeAgua: < 0.05%; ModuloDeRuptura: > 45 N/mm²; ResistenciaAFlexao: > 1500 N; ResistenciaAAbrasaoProfunda: < 120 mm³; DilatacaoTermicaLinear: ≤ 8,0x10-6 °C-1; ResistenciaAoChoqueTermico: Resiste; DurabilidadeResistenciaAoGeloDegelo: Resiste; ResistenciaAoEscorregamentoDIN51130: R9; ResistenciaAoEscorregamentoDIN51097: A; ResistenciaAoEscorregamentoENV51097: A; ResistenciaAoDeslizamentoENV12633: Class 1; ResistenciaAoEscorregamentoANSIA1371: ≥0,42; ResistenciaAoEscorregamentoENV12633: Class 1; ResistenciaAsManchas: Class 5; ResistenciaABaixasConcentracoesDeAcidosEAlcalis: Classe LA; ResistenciaAAltasConcentracoesDeAcidosEAlcalis: Classe HA; LibertacaoDeCadmio: 0; LibertacaoDeChumbo: 0
Type - IFC.REVIGRÉS-Dados de especificação-Wall Sweeps - VariacaoTonalidade: 2; NivelDeTrafego: 0; EPavimento: Não; ERevestimento: Sim; EExterno: Sim
Type - IFC.REVIGRÉS-Dados geométricos-Wall Sweeps - AlturaNominal: 7.7 mm; ComprimentoNominal: 9.5 mm; LarguraNominal: 30 mm
Type - IFC.REVIGRÉS-Dados de sustentabilidade-Wall Sweeps - PotencialPrivacaoDeAguaConsumoDeAguaPonderado: 4.5; EnergiaTermicaExportada: 0; ItemENovo: Sim; ItemEParcialmenteReciclado: 0.23; ItemEReciclado: Sim; VidaÚtilEsperada: 50; SubstanciasPerigosas: Não; PotencialDeEsgotamentoAbioticoDosRecursosFosseis: 203; PotencialDeEsgotamentoAbioticoDosRecursosNaoFosseisMineraisEMetais: 0.000701; PotencialDeAquecimentoGlobalBiogenico: -0.48; CombustiveisFosseisComPotencialDeAquecimentoGlobal: 13.9; PotencialDeAquecimentoGlobalUsoDoSoloEMudancaDeUsoDoSolo: 0.0246; PotencialDeEutrofizacaoFraccaoDeNutrientesQueAtingemOCompartimentoFinalDeAguaDoce: 0.000189; PotencialDeEutrofizacaoFraccaoDeNutrientesQueAtingemOCompartimentoFinalMarinho: 0.0122; EnergiaRecuperada: 0.00739; ConsumoDeAguaDoce: 0.113; UtilizacaoLiquidaDeAguaDoce: 0.113; ResiduosPerigososEliminados: 0.00221; ResiduosNaoPerigososEliminados: 1.83; MassaTotalDeResiduosRadioactivosEliminados: 0.000394; EnergiaElectricaExportada: 1.55; MateriaisParaRecuperacaoDeEnergia: 0.00739; MateriaisParaReciclagem: 0.0253; UnidadeEPD: 1 m²
Type - IFC.REVIGRÉS-Dados gerais-Wall Sweeps - Nome: REVIGRÉS-URBAN-RB-9,5X30-NAT-URBAN FOG; TipoProduto: Prensado a seco: grupo BIa UGL | Grés porcelânico técnico; NumeroDeRegistoDAP: EPD-REV-20240006-CCC1-EN; ReferenciaDAP: -; UrlDOP: -
Pset_ProvisionForVoid - Shape: Undefined; Width: 1000 mm; Depth: 1000 mm
IFC.REVIGRÉS-Dados do fabricante-Wall Sweeps - Type: Wall Sweep: REVIGRÉS-URBAN-RB-9.5X30-NAT-FOG
IFC.REVIGRÉS-Dados de desempenho-Wall Sweeps - Type: Wall Sweep: REVIGRÉS-URBAN-RB-9.5X30-NAT-FOG
IFC.REVIGRÉS-Dados de especificação-Wall Sweeps - Type: Wall Sweep: REVIGRÉS-URBAN-RB-9.5X30-NAT-FOG
IFC.REVIGRÉS-Dados geométricos-Wall Sweeps - Type: Wall Sweep: REVIGRÉS-URBAN-RB-9.5X30-NAT-FOG
IFC.REVIGRÉS-Dados de sustentabilidade-Wall Sweeps - Type: Wall Sweep: REVIGRÉS-URBAN-RB-9.5X30-NAT-FOG

# IfcBuildingElementProxy: Wall Sweep:REVIGRÉS-URBAN-RB-9.5X30-NAT-GRIS, Wall Sweep:REVIGRÉS-URBAN-RB-9.5X30-NAT-GRIS:182790
In: Level 1
Type - Pset_ManufacturerTypeInformation - Manufacturer: REVIGRÉS
Type - Pset_ProductRequirements - Category: Wall Sweeps
Type - IFC.REVIGRÉS-Dados do fabricante-Wall Sweeps - FabricanteURL: https://www.revigres.pt/; ReferenciaModelo: Urban; Acabamento: RECT; IdentificadorDoOperadorEconomico: 501840856; UrlFabricanteArtigo: https://www.revigres.pt/colecoes/urban; PaisOrigem: Portugal
Type - IFC.REVIGRÉS-Dados de desempenho-Wall Sweeps - Rectilinearidade: ± 0.2% máx.± 0.8 mm; Ortogonalidade: ± 0.2% máx.± 1.5 mm; PlanaridadeDaSuperficie: ± 0.3% máx. ± 1.8 mm; AbsorcaoDeAgua: < 0.05%; ModuloDeRuptura: > 45 N/mm²; ResistenciaAFlexao: > 1500 N; ResistenciaAAbrasaoProfunda: < 120 mm³; DilatacaoTermicaLinear: ≤ 8,0x10-6 °C-1; ResistenciaAoChoqueTermico: Resiste; DurabilidadeResistenciaAoGeloDegelo: Resiste; ResistenciaAoEscorregamentoDIN51130: R9; ResistenciaAoEscorregamentoDIN51097: A; ResistenciaAoEscorregamentoENV51097: A; ResistenciaAoDeslizamentoENV12633: Class 1; ResistenciaAoEscorregamentoANSIA1371: ≥0,42; ResistenciaAoEscorregamentoENV12633: Class 1; ResistenciaAsManchas: Class 5; ResistenciaABaixasConcentracoesDeAcidosEAlcalis: Classe LA; ResistenciaAAltasConcentracoesDeAcidosEAlcalis: Classe HA; LibertacaoDeCadmio: 0; LibertacaoDeChumbo: 0
Type - IFC.REVIGRÉS-Dados de especificação-Wall Sweeps - VariacaoTonalidade: 2; NivelDeTrafego: 0; EPavimento: Não; ERevestimento: Sim; EExterno: Sim
Type - IFC.REVIGRÉS-Dados geométricos-Wall Sweeps - AlturaNominal: 7.7 mm; ComprimentoNominal: 9.5 mm; LarguraNominal: 30 mm
Type - IFC.REVIGRÉS-Dados de sustentabilidade-Wall Sweeps - PotencialPrivacaoDeAguaConsumoDeAguaPonderado: 4.5; EnergiaTermicaExportada: 0; ItemENovo: Sim; ItemEParcialmenteReciclado: 0.23; ItemEReciclado: Sim; VidaÚtilEsperada: 50; SubstanciasPerigosas: Não; PotencialDeEsgotamentoAbioticoDosRecursosFosseis: 203; PotencialDeEsgotamentoAbioticoDosRecursosNaoFosseisMineraisEMetais: 0.000701; PotencialDeAquecimentoGlobalBiogenico: -0.48; CombustiveisFosseisComPotencialDeAquecimentoGlobal: 13.9; PotencialDeAquecimentoGlobalUsoDoSoloEMudancaDeUsoDoSolo: 0.0246; PotencialDeEutrofizacaoFraccaoDeNutrientesQueAtingemOCompartimentoFinalDeAguaDoce: 0.000189; PotencialDeEutrofizacaoFraccaoDeNutrientesQueAtingemOCompartimentoFinalMarinho: 0.0122; EnergiaRecuperada: 0.00739; ConsumoDeAguaDoce: 0.113; UtilizacaoLiquidaDeAguaDoce: 0.113; ResiduosPerigososEliminados: 0.00221; ResiduosNaoPerigososEliminados: 1.83; MassaTotalDeResiduosRadioactivosEliminados: 0.000394; EnergiaElectricaExportada: 1.55; MateriaisParaRecuperacaoDeEnergia: 0.00739; MateriaisParaReciclagem: 0.0253; UnidadeEPD: 1 m²
Type - IFC.REVIGRÉS-Dados gerais-Wall Sweeps - Nome: REVIGRÉS-URBAN-RB-9,5X30-NAT-URBAN GRIS; TipoProduto: Prensado a seco: grupo BIa UGL | Grés porcelânico técnico; NumeroDeRegistoDAP: EPD-REV-20240006-CCC1-EN; ReferenciaDAP: -; UrlDOP: -
Pset_ProvisionForVoid - Shape: Undefined; Width: 1000 mm; Depth: 1000 mm
IFC.REVIGRÉS-Dados do fabricante-Wall Sweeps - Type: Wall Sweep: REVIGRÉS-URBAN-RB-9.5X30-NAT-GRIS
IFC.REVIGRÉS-Dados de desempenho-Wall Sweeps - Type: Wall Sweep: REVIGRÉS-URBAN-RB-9.5X30-NAT-GRIS
IFC.REVIGRÉS-Dados de especificação-Wall Sweeps - Type: Wall Sweep: REVIGRÉS-URBAN-RB-9.5X30-NAT-GRIS
IFC.REVIGRÉS-Dados geométricos-Wall Sweeps - Type: Wall Sweep: REVIGRÉS-URBAN-RB-9.5X30-NAT-GRIS
IFC.REVIGRÉS-Dados de sustentabilidade-Wall Sweeps - Type: Wall Sweep: REVIGRÉS-URBAN-RB-9.5X30-NAT-GRIS

# IfcBuildingElementProxy: Wall Sweep:REVIGRÉS-URBAN-RB-9.5X30-NAT-OFFWHITE, Wall Sweep:REVIGRÉS-URBAN-RB-9.5X30-NAT-OFFWHITE:182800
In: Level 1
Type - Pset_ManufacturerTypeInformation - Manufacturer: REVIGRÉS
Type - Pset_ProductRequirements - Category: Wall Sweeps
Type - IFC.REVIGRÉS-Dados do fabricante-Wall Sweeps - FabricanteURL: https://www.revigres.pt/; ReferenciaModelo: Urban; Acabamento: RECT; IdentificadorDoOperadorEconomico: 501840856; UrlFabricanteArtigo: https://www.revigres.pt/colecoes/urban; PaisOrigem: Portugal
Type - IFC.REVIGRÉS-Dados de desempenho-Wall Sweeps - Rectilinearidade: ± 0.2% máx.± 0.8 mm; Ortogonalidade: ± 0.2% máx.± 1.5 mm; PlanaridadeDaSuperficie: ± 0.3% máx. ± 1.8 mm; AbsorcaoDeAgua: < 0.05%; ModuloDeRuptura: > 45 N/mm²; ResistenciaAFlexao: > 1500 N; ResistenciaAAbrasaoProfunda: < 120 mm³; DilatacaoTermicaLinear: ≤ 8,0x10-6 °C-1; ResistenciaAoChoqueTermico: Resiste; DurabilidadeResistenciaAoGeloDegelo: Resiste; ResistenciaAoEscorregamentoDIN51130: R9; ResistenciaAoEscorregamentoDIN51097: A; ResistenciaAoEscorregamentoENV51097: A; ResistenciaAoDeslizamentoENV12633: Class 1; ResistenciaAoEscorregamentoANSIA1371: ≥0,42; ResistenciaAoEscorregamentoENV12633: Class 1; ResistenciaAsManchas: Class 5; ResistenciaABaixasConcentracoesDeAcidosEAlcalis: Classe LA; ResistenciaAAltasConcentracoesDeAcidosEAlcalis: Classe HA; LibertacaoDeCadmio: 0; LibertacaoDeChumbo: 0
Type - IFC.REVIGRÉS-Dados de especificação-Wall Sweeps - VariacaoTonalidade: 2; NivelDeTrafego: 0; EPavimento: Não; ERevestimento: Sim; EExterno: Sim
Type - IFC.REVIGRÉS-Dados geométricos-Wall Sweeps - AlturaNominal: 7.7 mm; ComprimentoNominal: 9.5 mm; LarguraNominal: 30 mm
Type - IFC.REVIGRÉS-Dados de sustentabilidade-Wall Sweeps - PotencialPrivacaoDeAguaConsumoDeAguaPonderado: 4.5; EnergiaTermicaExportada: 0; ItemENovo: Sim; ItemEParcialmenteReciclado: 0.03; ItemEReciclado: Sim; VidaÚtilEsperada: 50; SubstanciasPerigosas: Não; PotencialDeEsgotamentoAbioticoDosRecursosFosseis: 203; PotencialDeEsgotamentoAbioticoDosRecursosNaoFosseisMineraisEMetais: 0.000701; PotencialDeAquecimentoGlobalBiogenico: -0.48; CombustiveisFosseisComPotencialDeAquecimentoGlobal: 13.9; PotencialDeAquecimentoGlobalUsoDoSoloEMudancaDeUsoDoSolo: 0.0246; PotencialDeEutrofizacaoFraccaoDeNutrientesQueAtingemOCompartimentoFinalDeAguaDoce: 0.000189; PotencialDeEutrofizacaoFraccaoDeNutrientesQueAtingemOCompartimentoFinalMarinho: 0.0122; EnergiaRecuperada: 0.00739; ConsumoDeAguaDoce: 0.113; UtilizacaoLiquidaDeAguaDoce: 0.113; ResiduosPerigososEliminados: 0.00221; ResiduosNaoPerigososEliminados: 1.83; MassaTotalDeResiduosRadioactivosEliminados: 0.000394; EnergiaElectricaExportada: 1.55; MateriaisParaRecuperacaoDeEnergia: 0.00739; MateriaisParaReciclagem: 0.0253; UnidadeEPD: 1 m²
Type - IFC.REVIGRÉS-Dados gerais-Wall Sweeps - Nome: REVIGRÉS-URBAN-RB-9,5X30-NAT-URBAN OFFWHITE; TipoProduto: Prensado a seco: grupo BIa UGL | Grés porcelânico técnico; NumeroDeRegistoDAP: EPD-REV-20240006-CCC1-EN; ReferenciaDAP: -; UrlDOP: -
Pset_ProvisionForVoid - Shape: Undefined; Width: 1000 mm; Depth: 1000 mm
IFC.REVIGRÉS-Dados do fabricante-Wall Sweeps - Type: Wall Sweep: REVIGRÉS-URBAN-RB-9.5X30-NAT-OFFWHITE
IFC.REVIGRÉS-Dados de desempenho-Wall Sweeps - Type: Wall Sweep: REVIGRÉS-URBAN-RB-9.5X30-NAT-OFFWHITE
IFC.REVIGRÉS-Dados de especificação-Wall Sweeps - Type: Wall Sweep: REVIGRÉS-URBAN-RB-9.5X30-NAT-OFFWHITE
IFC.REVIGRÉS-Dados geométricos-Wall Sweeps - Type: Wall Sweep: REVIGRÉS-URBAN-RB-9.5X30-NAT-OFFWHITE
IFC.REVIGRÉS-Dados de sustentabilidade-Wall Sweeps - Type: Wall Sweep: REVIGRÉS-URBAN-RB-9.5X30-NAT-OFFWHITE

# IfcBuildingElementProxy: Wall Sweep:REVIGRÉS-URBAN-RB-9.5X30-RECT-ANTRACITE, Wall Sweep:REVIGRÉS-URBAN-RB-9.5X30-RECT-ANTRACITE:182746
In: Level 1
Type - Pset_ManufacturerTypeInformation - Manufacturer: REVIGRÉS
Type - Pset_ProductRequirements - Category: Wall Sweeps
Type - IFC.REVIGRÉS-Dados do fabricante-Wall Sweeps - FabricanteURL: https://www.revigres.pt/; ReferenciaModelo: Urban; Acabamento: NAT; IdentificadorDoOperadorEconomico: 501840856; UrlFabricanteArtigo: https://www.revigres.pt/colecoes/urban; PaisOrigem: Portugal
Type - IFC.REVIGRÉS-Dados de desempenho-Wall Sweeps - Rectilinearidade: ± 0.3% máx. ± 1.5 mm; Ortogonalidade: ± 0.3% máx. ± 1.8 mm; PlanaridadeDaSuperficie: ± 0.3% máx. ± 1.8 mm; AbsorcaoDeAgua: < 0.05%; ModuloDeRuptura: > 45 N/mm²; ResistenciaAFlexao: > 2000 N; ResistenciaAAbrasaoProfunda: < 120 mm³; DilatacaoTermicaLinear: ≤ 8,0x10-6 °C-1; ResistenciaAoChoqueTermico: Resiste; DurabilidadeResistenciaAoGeloDegelo: Resiste; ResistenciaAoEscorregamentoDIN51130: R9; ResistenciaAoEscorregamentoDIN51097: A; ResistenciaAoEscorregamentoENV51097: A; ResistenciaAoDeslizamentoENV12633: Class 1; ResistenciaAoEscorregamentoANSIA1371: ≥0,42; ResistenciaAoEscorregamentoENV12633: Class 1; ResistenciaAsManchas: Class 5; ResistenciaABaixasConcentracoesDeAcidosEAlcalis: Classe LA; ResistenciaAAltasConcentracoesDeAcidosEAlcalis: Classe HA; LibertacaoDeCadmio: 0; LibertacaoDeChumbo: 0
Type - IFC.REVIGRÉS-Dados de especificação-Wall Sweeps - VariacaoTonalidade: 2; NivelDeTrafego: 0; EPavimento: Não; ERevestimento: Sim; EExterno: Sim
Type - IFC.REVIGRÉS-Dados geométricos-Wall Sweeps - AlturaNominal: 7.7 mm; ComprimentoNominal: 9.5 mm; LarguraNominal: 295 mm
Type - IFC.REVIGRÉS-Dados de sustentabilidade-Wall Sweeps - PotencialPrivacaoDeAguaConsumoDeAguaPonderado: 4.5; EnergiaTermicaExportada: 0; ItemENovo: Sim; ItemEParcialmenteReciclado: 0.29; ItemEReciclado: Sim; VidaÚtilEsperada: 50; SubstanciasPerigosas: Não; PotencialDeEsgotamentoAbioticoDosRecursosFosseis: 203; PotencialDeEsgotamentoAbioticoDosRecursosNaoFosseisMineraisEMetais: 0.000701; PotencialDeAquecimentoGlobalBiogenico: -0.48; CombustiveisFosseisComPotencialDeAquecimentoGlobal: 13.9; PotencialDeAquecimentoGlobalUsoDoSoloEMudancaDeUsoDoSolo: 0.0246; PotencialDeEutrofizacaoFraccaoDeNutrientesQueAtingemOCompartimentoFinalDeAguaDoce: 0.000189; PotencialDeEutrofizacaoFraccaoDeNutrientesQueAtingemOCompartimentoFinalMarinho: 0.0122; EnergiaRecuperada: 0.00739; ConsumoDeAguaDoce: 0.113; UtilizacaoLiquidaDeAguaDoce: 0.113; ResiduosPerigososEliminados: 0.00221; ResiduosNaoPerigososEliminados: 1.83; MassaTotalDeResiduosRadioactivosEliminados: 0.000394; EnergiaElectricaExportada: 1.55; MateriaisParaRecuperacaoDeEnergia: 0.00739; MateriaisParaReciclagem: 0.0253; UnidadeEPD: 1 m²
Type - IFC.REVIGRÉS-Dados gerais-Wall Sweeps - Nome: REVIGRÉS-URBAN-RB-9,5X30-RECT-URBAN ANTRACITE; TipoProduto: Prensado a seco: grupo BIa UGL | Grés porcelânico técnico; NumeroDeRegistoDAP: EPD-REV-20240006-CCC1-EN; ReferenciaDAP: -; UrlDOP: -
Pset_ProvisionForVoid - Shape: Undefined; Width: 1000 mm; Depth: 1000 mm
IFC.REVIGRÉS-Dados do fabricante-Wall Sweeps - Type: Wall Sweep: REVIGRÉS-URBAN-RB-9.5X30-RECT-ANTRACITE
IFC.REVIGRÉS-Dados de desempenho-Wall Sweeps - Type: Wall Sweep: REVIGRÉS-URBAN-RB-9.5X30-RECT-ANTRACITE
IFC.REVIGRÉS-Dados de especificação-Wall Sweeps - Type: Wall Sweep: REVIGRÉS-URBAN-RB-9.5X30-RECT-ANTRACITE
IFC.REVIGRÉS-Dados geométricos-Wall Sweeps - Type: Wall Sweep: REVIGRÉS-URBAN-RB-9.5X30-RECT-ANTRACITE
IFC.REVIGRÉS-Dados de sustentabilidade-Wall Sweeps - Type: Wall Sweep: REVIGRÉS-URBAN-RB-9.5X30-RECT-ANTRACITE

# IfcBuildingElementProxy: Wall Sweep:REVIGRÉS-URBAN-RB-9.5X30-RECT-BONE, Wall Sweep:REVIGRÉS-URBAN-RB-9.5X30-RECT-BONE:182756
In: Level 1
Type - Pset_ManufacturerTypeInformation - Manufacturer: REVIGRÉS
Type - Pset_ProductRequirements - Category: Wall Sweeps
Type - IFC.REVIGRÉS-Dados do fabricante-Wall Sweeps - FabricanteURL: https://www.revigres.pt/; ReferenciaModelo: Urban; Acabamento: NAT; IdentificadorDoOperadorEconomico: 501840856; UrlFabricanteArtigo: https://www.revigres.pt/colecoes/urban; PaisOrigem: Portugal
Type - IFC.REVIGRÉS-Dados de desempenho-Wall Sweeps - Rectilinearidade: ± 0.3% máx. ± 1.5 mm; Ortogonalidade: ± 0.3% máx. ± 1.8 mm; PlanaridadeDaSuperficie: ± 0.3% máx. ± 1.8 mm; AbsorcaoDeAgua: < 0.05%; ModuloDeRuptura: > 45 N/mm²; ResistenciaAFlexao: > 2000 N; ResistenciaAAbrasaoProfunda: < 120 mm³; DilatacaoTermicaLinear: ≤ 8,0x10-6 °C-1; ResistenciaAoChoqueTermico: Resiste; DurabilidadeResistenciaAoGeloDegelo: Resiste; ResistenciaAoEscorregamentoDIN51130: R9; ResistenciaAoEscorregamentoDIN51097: A; ResistenciaAoEscorregamentoENV51097: A; ResistenciaAoDeslizamentoENV12633: Class 1; ResistenciaAoEscorregamentoANSIA1371: ≥0,42; ResistenciaAoEscorregamentoENV12633: Class 1; ResistenciaAsManchas: Class 5; ResistenciaABaixasConcentracoesDeAcidosEAlcalis: Classe LA; ResistenciaAAltasConcentracoesDeAcidosEAlcalis: Classe HA; LibertacaoDeCadmio: 0; LibertacaoDeChumbo: 0
Type - IFC.REVIGRÉS-Dados de especificação-Wall Sweeps - VariacaoTonalidade: 2; NivelDeTrafego: 0; EPavimento: Não; ERevestimento: Sim; EExterno: Sim
Type - IFC.REVIGRÉS-Dados geométricos-Wall Sweeps - AlturaNominal: 7.7 mm; ComprimentoNominal: 9.5 mm; LarguraNominal: 295 mm
Type - IFC.REVIGRÉS-Dados de sustentabilidade-Wall Sweeps - PotencialPrivacaoDeAguaConsumoDeAguaPonderado: 4.5; EnergiaTermicaExportada: 0; ItemENovo: Sim; ItemEParcialmenteReciclado: 0.03; ItemEReciclado: Sim; VidaÚtilEsperada: 50; SubstanciasPerigosas: Não; PotencialDeEsgotamentoAbioticoDosRecursosFosseis: 203; PotencialDeEsgotamentoAbioticoDosRecursosNaoFosseisMineraisEMetais: 0.000701; PotencialDeAquecimentoGlobalBiogenico: -0.48; CombustiveisFosseisComPotencialDeAquecimentoGlobal: 13.9; PotencialDeAquecimentoGlobalUsoDoSoloEMudancaDeUsoDoSolo: 0.0246; PotencialDeEutrofizacaoFraccaoDeNutrientesQueAtingemOCompartimentoFinalDeAguaDoce: 0.000189; PotencialDeEutrofizacaoFraccaoDeNutrientesQueAtingemOCompartimentoFinalMarinho: 0.0122; EnergiaRecuperada: 0.00739; ConsumoDeAguaDoce: 0.113; UtilizacaoLiquidaDeAguaDoce: 0.113; ResiduosPerigososEliminados: 0.00221; ResiduosNaoPerigososEliminados: 1.83; MassaTotalDeResiduosRadioactivosEliminados: 0.000394; EnergiaElectricaExportada: 1.55; MateriaisParaRecuperacaoDeEnergia: 0.00739; MateriaisParaReciclagem: 0.0253; UnidadeEPD: 1 m²
Type - IFC.REVIGRÉS-Dados gerais-Wall Sweeps - Nome: REVIGRÉS-URBAN-RB-9,5X30-RECT-URBAN BONE; TipoProduto: Prensado a seco: grupo BIa UGL | Grés porcelânico técnico; NumeroDeRegistoDAP: EPD-REV-20240006-CCC1-EN; ReferenciaDAP: -; UrlDOP: -
Pset_ProvisionForVoid - Shape: Undefined; Width: 1000 mm; Depth: 1000 mm
IFC.REVIGRÉS-Dados do fabricante-Wall Sweeps - Type: Wall Sweep: REVIGRÉS-URBAN-RB-9.5X30-RECT-BONE
IFC.REVIGRÉS-Dados de desempenho-Wall Sweeps - Type: Wall Sweep: REVIGRÉS-URBAN-RB-9.5X30-RECT-BONE
IFC.REVIGRÉS-Dados de especificação-Wall Sweeps - Type: Wall Sweep: REVIGRÉS-URBAN-RB-9.5X30-RECT-BONE
IFC.REVIGRÉS-Dados geométricos-Wall Sweeps - Type: Wall Sweep: REVIGRÉS-URBAN-RB-9.5X30-RECT-BONE
IFC.REVIGRÉS-Dados de sustentabilidade-Wall Sweeps - Type: Wall Sweep: REVIGRÉS-URBAN-RB-9.5X30-RECT-BONE

# IfcBuildingElementProxy: Wall Sweep:REVIGRÉS-URBAN-RB-9.5X30-RECT-CRAFT, Wall Sweep:REVIGRÉS-URBAN-RB-9.5X30-RECT-CRAFT:182766
In: Level 1
Type - Pset_ManufacturerTypeInformation - Manufacturer: REVIGRÉS
Type - Pset_ProductRequirements - Category: Wall Sweeps
Type - IFC.REVIGRÉS-Dados do fabricante-Wall Sweeps - FabricanteURL: https://www.revigres.pt/; ReferenciaModelo: Urban; Acabamento: NAT; IdentificadorDoOperadorEconomico: 501840856; UrlFabricanteArtigo: https://www.revigres.pt/colecoes/urban; PaisOrigem: Portugal
Type - IFC.REVIGRÉS-Dados de desempenho-Wall Sweeps - Rectilinearidade: ± 0.3% máx. ± 1.5 mm; Ortogonalidade: ± 0.3% máx. ± 1.8 mm; PlanaridadeDaSuperficie: ± 0.3% máx. ± 1.8 mm; AbsorcaoDeAgua: < 0.05%; ModuloDeRuptura: > 45 N/mm²; ResistenciaAFlexao: > 2000 N; ResistenciaAAbrasaoProfunda: < 120 mm³; DilatacaoTermicaLinear: ≤ 8,0x10-6 °C-1; ResistenciaAoChoqueTermico: Resiste; DurabilidadeResistenciaAoGeloDegelo: Resiste; ResistenciaAoEscorregamentoDIN51130: R9; ResistenciaAoEscorregamentoDIN51097: A; ResistenciaAoEscorregamentoENV51097: A; ResistenciaAoDeslizamentoENV12633: Class 1; ResistenciaAoEscorregamentoANSIA1371: ≥0,42; ResistenciaAoEscorregamentoENV12633: Class 1; ResistenciaAsManchas: Class 5; ResistenciaABaixasConcentracoesDeAcidosEAlcalis: Classe LA; ResistenciaAAltasConcentracoesDeAcidosEAlcalis: Classe HA; LibertacaoDeCadmio: 0; LibertacaoDeChumbo: 0
Type - IFC.REVIGRÉS-Dados de especificação-Wall Sweeps - VariacaoTonalidade: 2; NivelDeTrafego: 0; EPavimento: Não; ERevestimento: Sim; EExterno: Sim
Type - IFC.REVIGRÉS-Dados geométricos-Wall Sweeps - AlturaNominal: 7.7 mm; ComprimentoNominal: 9.5 mm; LarguraNominal: 295 mm
Type - IFC.REVIGRÉS-Dados de sustentabilidade-Wall Sweeps - PotencialPrivacaoDeAguaConsumoDeAguaPonderado: 4.5; EnergiaTermicaExportada: 0; ItemENovo: Sim; ItemEParcialmenteReciclado: 0.19; ItemEReciclado: Sim; VidaÚtilEsperada: 50; SubstanciasPerigosas: Não; PotencialDeEsgotamentoAbioticoDosRecursosFosseis: 203; PotencialDeEsgotamentoAbioticoDosRecursosNaoFosseisMineraisEMetais: 0.000701; PotencialDeAquecimentoGlobalBiogenico: -0.48; CombustiveisFosseisComPotencialDeAquecimentoGlobal: 13.9; PotencialDeAquecimentoGlobalUsoDoSoloEMudancaDeUsoDoSolo: 0.0246; PotencialDeEutrofizacaoFraccaoDeNutrientesQueAtingemOCompartimentoFinalDeAguaDoce: 0.000189; PotencialDeEutrofizacaoFraccaoDeNutrientesQueAtingemOCompartimentoFinalMarinho: 0.0122; EnergiaRecuperada: 0.00739; ConsumoDeAguaDoce: 0.113; UtilizacaoLiquidaDeAguaDoce: 0.113; ResiduosPerigososEliminados: 0.00221; ResiduosNaoPerigososEliminados: 1.83; MassaTotalDeResiduosRadioactivosEliminados: 0.000394; EnergiaElectricaExportada: 1.55; MateriaisParaRecuperacaoDeEnergia: 0.00739; MateriaisParaReciclagem: 0.0253; UnidadeEPD: 1 m²
Type - IFC.REVIGRÉS-Dados gerais-Wall Sweeps - Nome: REVIGRÉS-URBAN-RB-9,5X30-RECT-URBAN CRAFT; TipoProduto: Prensado a seco: grupo BIa UGL | Grés porcelânico técnico; NumeroDeRegistoDAP: EPD-REV-20240006-CCC1-EN; ReferenciaDAP: -; UrlDOP: -
Pset_ProvisionForVoid - Shape: Undefined; Width: 1000 mm; Depth: 1000 mm
IFC.REVIGRÉS-Dados do fabricante-Wall Sweeps - Type: Wall Sweep: REVIGRÉS-URBAN-RB-9.5X30-RECT-CRAFT
IFC.REVIGRÉS-Dados de desempenho-Wall Sweeps - Type: Wall Sweep: REVIGRÉS-URBAN-RB-9.5X30-RECT-CRAFT
IFC.REVIGRÉS-Dados de especificação-Wall Sweeps - Type: Wall Sweep: REVIGRÉS-URBAN-RB-9.5X30-RECT-CRAFT
IFC.REVIGRÉS-Dados geométricos-Wall Sweeps - Type: Wall Sweep: REVIGRÉS-URBAN-RB-9.5X30-RECT-CRAFT
IFC.REVIGRÉS-Dados de sustentabilidade-Wall Sweeps - Type: Wall Sweep: REVIGRÉS-URBAN-RB-9.5X30-RECT-CRAFT

# IfcBuildingElementProxy: Wall Sweep:REVIGRÉS-URBAN-RB-9.5X30-RECT-FOG, Wall Sweep:REVIGRÉS-URBAN-RB-9.5X30-RECT-FOG:182776
In: Level 1
Type - Pset_ManufacturerTypeInformation - Manufacturer: REVIGRÉS
Type - Pset_ProductRequirements - Category: Wall Sweeps
Type - IFC.REVIGRÉS-Dados do fabricante-Wall Sweeps - FabricanteURL: https://www.revigres.pt/; ReferenciaModelo: Urban; Acabamento: NAT; IdentificadorDoOperadorEconomico: 501840856; UrlFabricanteArtigo: https://www.revigres.pt/colecoes/urban; PaisOrigem: Portugal
Type - IFC.REVIGRÉS-Dados de desempenho-Wall Sweeps - Rectilinearidade: ± 0.3% máx. ± 1.5 mm; Ortogonalidade: ± 0.3% máx. ± 1.8 mm; PlanaridadeDaSuperficie: ± 0.3% máx. ± 1.8 mm; AbsorcaoDeAgua: < 0.05%; ModuloDeRuptura: > 45 N/mm²; ResistenciaAFlexao: > 2000 N; ResistenciaAAbrasaoProfunda: < 120 mm³; DilatacaoTermicaLinear: ≤ 8,0x10-6 °C-1; ResistenciaAoChoqueTermico: Resiste; DurabilidadeResistenciaAoGeloDegelo: Resiste; ResistenciaAoEscorregamentoDIN51130: R9; ResistenciaAoEscorregamentoDIN51097: A; ResistenciaAoEscorregamentoENV51097: A; ResistenciaAoDeslizamentoENV12633: Class 1; ResistenciaAoEscorregamentoANSIA1371: ≥0,42; ResistenciaAoEscorregamentoENV12633: Class 1; ResistenciaAsManchas: Class 5; ResistenciaABaixasConcentracoesDeAcidosEAlcalis: Classe LA; ResistenciaAAltasConcentracoesDeAcidosEAlcalis: Classe HA; LibertacaoDeCadmio: 0; LibertacaoDeChumbo: 0
Type - IFC.REVIGRÉS-Dados de especificação-Wall Sweeps - VariacaoTonalidade: 2; NivelDeTrafego: 0; EPavimento: Não; ERevestimento: Sim; EExterno: Sim
Type - IFC.REVIGRÉS-Dados geométricos-Wall Sweeps - AlturaNominal: 7.7 mm; ComprimentoNominal: 9.5 mm; LarguraNominal: 295 mm
Type - IFC.REVIGRÉS-Dados de sustentabilidade-Wall Sweeps - PotencialPrivacaoDeAguaConsumoDeAguaPonderado: 4.5; EnergiaTermicaExportada: 0; ItemENovo: Sim; ItemEParcialmenteReciclado: 0.23; ItemEReciclado: Sim; VidaÚtilEsperada: 50; SubstanciasPerigosas: Não; PotencialDeEsgotamentoAbioticoDosRecursosFosseis: 203; PotencialDeEsgotamentoAbioticoDosRecursosNaoFosseisMineraisEMetais: 0.000701; PotencialDeAquecimentoGlobalBiogenico: -0.48; CombustiveisFosseisComPotencialDeAquecimentoGlobal: 13.9; PotencialDeAquecimentoGlobalUsoDoSoloEMudancaDeUsoDoSolo: 0.0246; PotencialDeEutrofizacaoFraccaoDeNutrientesQueAtingemOCompartimentoFinalDeAguaDoce: 0.000189; PotencialDeEutrofizacaoFraccaoDeNutrientesQueAtingemOCompartimentoFinalMarinho: 0.0122; EnergiaRecuperada: 0.00739; ConsumoDeAguaDoce: 0.113; UtilizacaoLiquidaDeAguaDoce: 0.113; ResiduosPerigososEliminados: 0.00221; ResiduosNaoPerigososEliminados: 1.83; MassaTotalDeResiduosRadioactivosEliminados: 0.000394; EnergiaElectricaExportada: 1.55; MateriaisParaRecuperacaoDeEnergia: 0.00739; MateriaisParaReciclagem: 0.0253; UnidadeEPD: 1 m²
Type - IFC.REVIGRÉS-Dados gerais-Wall Sweeps - Nome: REVIGRÉS-URBAN-RB-9,5X30-RECT-URBAN FOG; TipoProduto: Prensado a seco: grupo BIa UGL | Grés porcelânico técnico; NumeroDeRegistoDAP: EPD-REV-20240006-CCC1-EN; ReferenciaDAP: -; UrlDOP: -
Pset_ProvisionForVoid - Shape: Undefined; Width: 1000 mm; Depth: 1000 mm
IFC.REVIGRÉS-Dados do fabricante-Wall Sweeps - Type: Wall Sweep: REVIGRÉS-URBAN-RB-9.5X30-RECT-FOG
IFC.REVIGRÉS-Dados de desempenho-Wall Sweeps - Type: Wall Sweep: REVIGRÉS-URBAN-RB-9.5X30-RECT-FOG
IFC.REVIGRÉS-Dados de especificação-Wall Sweeps - Type: Wall Sweep: REVIGRÉS-URBAN-RB-9.5X30-RECT-FOG
IFC.REVIGRÉS-Dados geométricos-Wall Sweeps - Type: Wall Sweep: REVIGRÉS-URBAN-RB-9.5X30-RECT-FOG
IFC.REVIGRÉS-Dados de sustentabilidade-Wall Sweeps - Type: Wall Sweep: REVIGRÉS-URBAN-RB-9.5X30-RECT-FOG

# IfcBuildingElementProxy: Wall Sweep:REVIGRÉS-URBAN-RB-9.5X30-RECT-GRIS, Wall Sweep:REVIGRÉS-URBAN-RB-9.5X30-RECT-GRIS:182786
In: Level 1
Type - Pset_ManufacturerTypeInformation - Manufacturer: REVIGRÉS
Type - Pset_ProductRequirements - Category: Wall Sweeps
Type - IFC.REVIGRÉS-Dados do fabricante-Wall Sweeps - FabricanteURL: https://www.revigres.pt/; ReferenciaModelo: Urban; Acabamento: NAT; IdentificadorDoOperadorEconomico: 501840856; UrlFabricanteArtigo: https://www.revigres.pt/colecoes/urban; PaisOrigem: Portugal
Type - IFC.REVIGRÉS-Dados de desempenho-Wall Sweeps - Rectilinearidade: ± 0.3% máx. ± 1.5 mm; Ortogonalidade: ± 0.3% máx. ± 1.8 mm; PlanaridadeDaSuperficie: ± 0.3% máx. ± 1.8 mm; AbsorcaoDeAgua: < 0.05%; ModuloDeRuptura: > 45 N/mm²; ResistenciaAFlexao: > 2000 N; ResistenciaAAbrasaoProfunda: < 120 mm³; DilatacaoTermicaLinear: ≤ 8,0x10-6 °C-1; ResistenciaAoChoqueTermico: Resiste; DurabilidadeResistenciaAoGeloDegelo: Resiste; ResistenciaAoEscorregamentoDIN51130: R9; ResistenciaAoEscorregamentoDIN51097: A; ResistenciaAoEscorregamentoENV51097: A; ResistenciaAoDeslizamentoENV12633: Class 1; ResistenciaAoEscorregamentoANSIA1371: ≥0,42; ResistenciaAoEscorregamentoENV12633: Class 1; ResistenciaAsManchas: Class 5; ResistenciaABaixasConcentracoesDeAcidosEAlcalis: Classe LA; ResistenciaAAltasConcentracoesDeAcidosEAlcalis: Classe HA; LibertacaoDeCadmio: 0; LibertacaoDeChumbo: 0
Type - IFC.REVIGRÉS-Dados de especificação-Wall Sweeps - VariacaoTonalidade: 2; NivelDeTrafego: 0; EPavimento: Não; ERevestimento: Sim; EExterno: Sim
Type - IFC.REVIGRÉS-Dados geométricos-Wall Sweeps - AlturaNominal: 7.7 mm; ComprimentoNominal: 9.5 mm; LarguraNominal: 295 mm
Type - IFC.REVIGRÉS-Dados de sustentabilidade-Wall Sweeps - PotencialPrivacaoDeAguaConsumoDeAguaPonderado: 4.5; EnergiaTermicaExportada: 0; ItemENovo: Sim; ItemEParcialmenteReciclado: 0.23; ItemEReciclado: Sim; VidaÚtilEsperada: 50; SubstanciasPerigosas: Não; PotencialDeEsgotamentoAbioticoDosRecursosFosseis: 203; PotencialDeEsgotamentoAbioticoDosRecursosNaoFosseisMineraisEMetais: 0.000701; PotencialDeAquecimentoGlobalBiogenico: -0.48; CombustiveisFosseisComPotencialDeAquecimentoGlobal: 13.9; PotencialDeAquecimentoGlobalUsoDoSoloEMudancaDeUsoDoSolo: 0.0246; PotencialDeEutrofizacaoFraccaoDeNutrientesQueAtingemOCompartimentoFinalDeAguaDoce: 0.000189; PotencialDeEutrofizacaoFraccaoDeNutrientesQueAtingemOCompartimentoFinalMarinho: 0.0122; EnergiaRecuperada: 0.00739; ConsumoDeAguaDoce: 0.113; UtilizacaoLiquidaDeAguaDoce: 0.113; ResiduosPerigososEliminados: 0.00221; ResiduosNaoPerigososEliminados: 1.83; MassaTotalDeResiduosRadioactivosEliminados: 0.000394; EnergiaElectricaExportada: 1.55; MateriaisParaRecuperacaoDeEnergia: 0.00739; MateriaisParaReciclagem: 0.0253; UnidadeEPD: 1 m²
Type - IFC.REVIGRÉS-Dados gerais-Wall Sweeps - Nome: REVIGRÉS-URBAN-RB-9,5X30-RECT-URBAN GRIS; TipoProduto: Prensado a seco: grupo BIa UGL | Grés porcelânico técnico; NumeroDeRegistoDAP: EPD-REV-20240006-CCC1-EN; ReferenciaDAP: -; UrlDOP: -
Pset_ProvisionForVoid - Shape: Undefined; Width: 1000 mm; Depth: 1000 mm
IFC.REVIGRÉS-Dados do fabricante-Wall Sweeps - Type: Wall Sweep: REVIGRÉS-URBAN-RB-9.5X30-RECT-GRIS
IFC.REVIGRÉS-Dados de desempenho-Wall Sweeps - Type: Wall Sweep: REVIGRÉS-URBAN-RB-9.5X30-RECT-GRIS
IFC.REVIGRÉS-Dados de especificação-Wall Sweeps - Type: Wall Sweep: REVIGRÉS-URBAN-RB-9.5X30-RECT-GRIS
IFC.REVIGRÉS-Dados geométricos-Wall Sweeps - Type: Wall Sweep: REVIGRÉS-URBAN-RB-9.5X30-RECT-GRIS
IFC.REVIGRÉS-Dados de sustentabilidade-Wall Sweeps - Type: Wall Sweep: REVIGRÉS-URBAN-RB-9.5X30-RECT-GRIS

# IfcBuildingElementProxy: Wall Sweep:REVIGRÉS-URBAN-RB-9.5X30-RECT-OFFWHITE, Wall Sweep:REVIGRÉS-URBAN-RB-9.5X30-RECT-OFFWHITE:182796
In: Level 1
Type - Pset_ManufacturerTypeInformation - Manufacturer: REVIGRÉS
Type - Pset_ProductRequirements - Category: Wall Sweeps
Type - IFC.REVIGRÉS-Dados do fabricante-Wall Sweeps - FabricanteURL: https://www.revigres.pt/; ReferenciaModelo: Urban; Acabamento: NAT; IdentificadorDoOperadorEconomico: 501840856; UrlFabricanteArtigo: https://www.revigres.pt/colecoes/urban; PaisOrigem: Portugal
Type - IFC.REVIGRÉS-Dados de desempenho-Wall Sweeps - Rectilinearidade: ± 0.3% máx. ± 1.5 mm; Ortogonalidade: ± 0.3% máx. ± 1.8 mm; PlanaridadeDaSuperficie: ± 0.3% máx. ± 1.8 mm; AbsorcaoDeAgua: < 0.05%; ModuloDeRuptura: > 45 N/mm²; ResistenciaAFlexao: > 2000 N; ResistenciaAAbrasaoProfunda: < 120 mm³; DilatacaoTermicaLinear: ≤ 8,0x10-6 °C-1; ResistenciaAoChoqueTermico: Resiste; DurabilidadeResistenciaAoGeloDegelo: Resiste; ResistenciaAoEscorregamentoDIN51130: R9; ResistenciaAoEscorregamentoDIN51097: A; ResistenciaAoEscorregamentoENV51097: A; ResistenciaAoDeslizamentoENV12633: Class 1; ResistenciaAoEscorregamentoANSIA1371: ≥0,42; ResistenciaAoEscorregamentoENV12633: Class 1; ResistenciaAsManchas: Class 5; ResistenciaABaixasConcentracoesDeAcidosEAlcalis: Classe LA; ResistenciaAAltasConcentracoesDeAcidosEAlcalis: Classe HA; LibertacaoDeCadmio: 0; LibertacaoDeChumbo: 0
Type - IFC.REVIGRÉS-Dados de especificação-Wall Sweeps - VariacaoTonalidade: 2; NivelDeTrafego: 0; EPavimento: Não; ERevestimento: Sim; EExterno: Sim
Type - IFC.REVIGRÉS-Dados geométricos-Wall Sweeps - AlturaNominal: 7.7 mm; ComprimentoNominal: 9.5 mm; LarguraNominal: 295 mm
Type - IFC.REVIGRÉS-Dados de sustentabilidade-Wall Sweeps - PotencialPrivacaoDeAguaConsumoDeAguaPonderado: 4.5; EnergiaTermicaExportada: 0; ItemENovo: Sim; ItemEParcialmenteReciclado: 0.03; ItemEReciclado: Sim; VidaÚtilEsperada: 50; SubstanciasPerigosas: Não; PotencialDeEsgotamentoAbioticoDosRecursosFosseis: 203; PotencialDeEsgotamentoAbioticoDosRecursosNaoFosseisMineraisEMetais: 0.000701; PotencialDeAquecimentoGlobalBiogenico: -0.48; CombustiveisFosseisComPotencialDeAquecimentoGlobal: 13.9; PotencialDeAquecimentoGlobalUsoDoSoloEMudancaDeUsoDoSolo: 0.0246; PotencialDeEutrofizacaoFraccaoDeNutrientesQueAtingemOCompartimentoFinalDeAguaDoce: 0.000189; PotencialDeEutrofizacaoFraccaoDeNutrientesQueAtingemOCompartimentoFinalMarinho: 0.0122; EnergiaRecuperada: 0.00739; ConsumoDeAguaDoce: 0.113; UtilizacaoLiquidaDeAguaDoce: 0.113; ResiduosPerigososEliminados: 0.00221; ResiduosNaoPerigososEliminados: 1.83; MassaTotalDeResiduosRadioactivosEliminados: 0.000394; EnergiaElectricaExportada: 1.55; MateriaisParaRecuperacaoDeEnergia: 0.00739; MateriaisParaReciclagem: 0.0253; UnidadeEPD: 1 m²
Type - IFC.REVIGRÉS-Dados gerais-Wall Sweeps - Nome: REVIGRÉS-URBAN-RB-9,5X30-RECT-URBAN OFFWHITE; TipoProduto: Prensado a seco: grupo BIa UGL | Grés porcelânico técnico; NumeroDeRegistoDAP: EPD-REV-20240006-CCC1-EN; ReferenciaDAP: -; UrlDOP: -
Pset_ProvisionForVoid - Shape: Undefined; Width: 1000 mm; Depth: 1000 mm
IFC.REVIGRÉS-Dados do fabricante-Wall Sweeps - Type: Wall Sweep: REVIGRÉS-URBAN-RB-9.5X30-RECT-OFFWHITE
IFC.REVIGRÉS-Dados de desempenho-Wall Sweeps - Type: Wall Sweep: REVIGRÉS-URBAN-RB-9.5X30-RECT-OFFWHITE
IFC.REVIGRÉS-Dados de especificação-Wall Sweeps - Type: Wall Sweep: REVIGRÉS-URBAN-RB-9.5X30-RECT-OFFWHITE
IFC.REVIGRÉS-Dados geométricos-Wall Sweeps - Type: Wall Sweep: REVIGRÉS-URBAN-RB-9.5X30-RECT-OFFWHITE
IFC.REVIGRÉS-Dados de sustentabilidade-Wall Sweeps - Type: Wall Sweep: REVIGRÉS-URBAN-RB-9.5X30-RECT-OFFWHITE

# IfcWallStandardCase: Basic Wall:Wall 1 (12)
In: Level 1
Type - PredefinedType: STANDARD
Type - Pset_ElementShading - Roughness: 304.8 mm
Type - Pset_ProductRequirements - Category: Walls
Type - Pset_QuantityTakeOff - Reference: Wall 1
Type - Pset_ReinforcementBarPitchOfWall - Reference: Wall 1
Type - Pset_WallCommon - Reference: Wall 1; IsExternal: no
Pset_QuantityTakeOff - sets with these values: 2
Pset_WallCommon - IsExternal: yes; ExtendToStructure: no; LoadBearing: no
Name (Basic Wall:Wall 1:...)
104322
158840
158991
159220
159471
159483
159823
160038
180458
180460
180461
180462
